VERSION 5.5 ;
NAMESCASESENSITIVE ON ;
BUSBITCHARS "[]" ;
DIVIDERCHAR "/" ;

PROPERTYDEFINITIONS
  LAYER routingPitch REAL ;
END PROPERTYDEFINITIONS

UNITS
  DATABASE MICRONS 1000 ;
END UNITS
MANUFACTURINGGRID 0.01 ;
LAYER POLY1
  TYPE MASTERSLICE ;
END POLY1

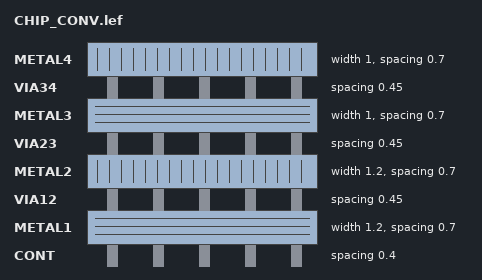
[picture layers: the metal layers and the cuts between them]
LAYER CONT
  TYPE CUT ;
  SPACING 0.4 ;
END CONT

LAYER METAL1
  TYPE ROUTING ;
  DIRECTION HORIZONTAL ;
  PITCH 0 ;
  WIDTH 1.2 ;
  SPACING 0.7 ;
  PROPERTY routingPitch 1.25 ;
END METAL1

LAYER VIA12
  TYPE CUT ;
  SPACING 0.45 ;
END VIA12

LAYER METAL2
  TYPE ROUTING ;
  DIRECTION VERTICAL ;
  PITCH 0 ;
  WIDTH 1.2 ;
  SPACING 0.7 ;
  PROPERTY routingPitch 1.4 ;
END METAL2

LAYER VIA23
  TYPE CUT ;
  SPACING 0.45 ;
END VIA23

LAYER METAL3
  TYPE ROUTING ;
  DIRECTION HORIZONTAL ;
  PITCH 0 ;
  WIDTH 1 ;
  SPACING 0.7 ;
  PROPERTY routingPitch 1.25 ;
END METAL3

LAYER VIA34
  TYPE CUT ;
  SPACING 0.45 ;
END VIA34

LAYER METAL4
  TYPE ROUTING ;
  DIRECTION VERTICAL ;
  PITCH 0 ;
  WIDTH 1 ;
  SPACING 0.7 ;
  PROPERTY routingPitch 1.4 ;
END METAL4

LAYER OVERLAP
  TYPE OVERLAP ;
END OVERLAP

VIARULE M4_M3 GENERATE
  LAYER METAL3 ;
    ENCLOSURE 0.2 0.2 ;
  LAYER METAL4 ;
    ENCLOSURE 0.15 0.15 ;
  LAYER VIA34 ;
    RECT -0.25 -0.25 0.25 0.25 ;
    SPACING 1 BY 1 ;
END M4_M3

VIARULE M3_M2 GENERATE
  LAYER METAL2 ;
    ENCLOSURE 0.2 0.2 ;
  LAYER METAL3 ;
    ENCLOSURE 0.15 0.15 ;
  LAYER VIA23 ;
    RECT -0.25 -0.25 0.25 0.25 ;
    SPACING 1 BY 1 ;
END M3_M2

VIARULE M2_M1 GENERATE
  LAYER METAL1 ;
    ENCLOSURE 0.2 0.2 ;
  LAYER METAL2 ;
    ENCLOSURE 0.15 0.15 ;
  LAYER VIA12 ;
    RECT -0.25 -0.25 0.25 0.25 ;
    SPACING 1 BY 1 ;
END M2_M1

VIARULE M1_POLY1 GENERATE
  LAYER POLY1 ;
    ENCLOSURE 0.2 0.2 ;
  LAYER METAL1 ;
    ENCLOSURE 0.15 0.15 ;
  LAYER CONT ;
    RECT -0.2 -0.2 0.2 0.2 ;
    SPACING 1 BY 1 ;
END M1_POLY1

VIA M1_POLY1
  LAYER CONT ;
    RECT -0.2 -0.2 0.2 0.2 ;
  LAYER POLY1 ;
    RECT -0.4 -0.4 0.4 0.4 ;
  LAYER METAL1 ;
    RECT -0.35 -0.35 0.35 0.35 ;
END M1_POLY1

VIA M2_M1
  LAYER VIA12 ;
    RECT -0.25 -0.25 0.25 0.25 ;
  LAYER METAL2 ;
    RECT -0.4 -0.4 0.4 0.4 ;
  LAYER METAL1 ;
    RECT -0.45 -0.45 0.45 0.45 ;
END M2_M1

VIA M3_M2
  LAYER VIA23 ;
    RECT -0.25 -0.25 0.25 0.25 ;
  LAYER METAL3 ;
    RECT -0.4 -0.4 0.4 0.4 ;
  LAYER METAL2 ;
    RECT -0.45 -0.45 0.45 0.45 ;
END M3_M2

VIA M4_M3
  LAYER VIA34 ;
    RECT -0.25 -0.25 0.25 0.25 ;
  LAYER METAL4 ;
    RECT -0.4 -0.4 0.4 0.4 ;
  LAYER METAL3 ;
    RECT -0.45 -0.45 0.45 0.45 ;
END M4_M3


MACRO Full_Macro_2p0_abstract
  PIN smclk_per_ext
    DIRECTION INOUT ;
    USE SIGNAL ;
    PORT
      LAYER METAL2 ;
        RECT 4738.52 82.5 4739.52 83.5 ;
    END
  END smclk_per_ext
  PIN unused_AN_MUX
    DIRECTION INOUT ;
    USE SIGNAL ;
    PORT
      LAYER METAL2 ;
        RECT 4784.2 45.0 4784.8 45.6 ;
    END
  END unused_AN_MUX
  PIN SystemDrainline<0>
    DIRECTION INOUT ;
    USE SIGNAL ;
    PORT
      LAYER METAL2 ;
        RECT 5600.2 45.0 5601.2 46.0 ;
    END
  END SystemDrainline<0>
  PIN SystemDrainline<1>
    DIRECTION INOUT ;
    USE SIGNAL ;
    PORT
      LAYER METAL2 ;
        RECT 5551.2 45.0 5552.2 46.0 ;
    END
  END SystemDrainline<1>
  PIN SystemDrainline<2>
    DIRECTION INOUT ;
    USE SIGNAL ;
    PORT
      LAYER METAL2 ;
        RECT 5500.8 45.0 5501.8 46.0 ;
    END
  END SystemDrainline<2>
  PIN V_IO
    DIRECTION INOUT ;
    USE SIGNAL ;
    PORT
      LAYER METAL2 ;
        RECT 5649.2 45.0 5650.2 46.0 ;
    END
  END V_IO
  PIN VTUN_AM
    DIRECTION INOUT ;
    USE SIGNAL ;
    PORT
      LAYER METAL2 ;
        RECT 5699.6 45.0 5700.6 46.0 ;
    END
  END VTUN_AM
  PIN VG_IO
    DIRECTION INOUT ;
    USE SIGNAL ;
    PORT
      LAYER METAL2 ;
        RECT 5748.6 45.0 5749.6 46.0 ;
    END
  END VG_IO
  PIN VGRUN
    DIRECTION INOUT ;
    USE SIGNAL ;
    PORT
      LAYER METAL2 ;
        RECT 5799.0 45.0 5800.0 46.0 ;
    END
  END VGRUN
  PIN VGPROG_IO
    DIRECTION INOUT ;
    USE SIGNAL ;
    PORT
      LAYER METAL2 ;
        RECT 5848.0 45.0 5849.0 46.0 ;
    END
  END VGPROG_IO
  PIN VGPROG
    DIRECTION INOUT ;
    USE SIGNAL ;
    PORT
      LAYER METAL2 ;
        RECT 5897.0 45.0 5898.0 46.0 ;
    END
  END VGPROG
  PIN VD_IO
    DIRECTION INOUT ;
    USE SIGNAL ;
    PORT
      LAYER METAL2 ;
        RECT 5947.4 45.0 5948.4 46.0 ;
    END
  END VD_IO
  PIN I_IO
    DIRECTION INOUT ;
    USE SIGNAL ;
    PORT
      LAYER METAL2 ;
        RECT 5996.4 45.0 5997.4 46.0 ;
    END
  END I_IO
  PIN Debug_IO
    DIRECTION INOUT ;
    USE SIGNAL ;
    PORT
      LAYER METAL2 ;
        RECT 6046.8 45.0 6047.8 46.0 ;
    END
  END Debug_IO
  PIN Cal_Vin
    DIRECTION INOUT ;
    USE SIGNAL ;
    PORT
      LAYER METAL2 ;
        RECT 6095.8 45.0 6096.8 46.0 ;
    END
  END Cal_Vin
  PIN Cal_IO
    DIRECTION INOUT ;
    USE SIGNAL ;
    PORT
      LAYER METAL2 ;
        RECT 6269.4 293.75 6270.4 294.35 ;
    END
  END Cal_IO
  PIN Bias_Trim
    DIRECTION INOUT ;
    USE SIGNAL ;
    PORT
      LAYER METAL2 ;
        RECT 6195.2 45.0 6196.2 46.0 ;
    END
  END Bias_Trim
  PIN AVDD
    DIRECTION INOUT ;
    USE SIGNAL ;
    PORT
      LAYER METAL2 ;
        RECT 6293.2 293.75 6294.2 294.75 ;
    END
  END AVDD
  PIN VINJ
    DIRECTION INOUT ;
    USE SIGNAL ;
    PORT
      LAYER METAL2 ;
        RECT 6253.39 293.75 6254.39 294.75 ;
    END
  END VINJ
  PIN DVDD
    DIRECTION INOUT ;
    USE SIGNAL ;
    PORT
      LAYER METAL2 ;
        RECT 4833.0 45.0 4834.0 46.0 ;
    END
  END DVDD
  PIN VTUN_fgmem
    DIRECTION INOUT ;
    USE SIGNAL ;
    PORT
      LAYER METAL2 ;
        RECT 4856.8 45.0 4857.8 46.0 ;
    END
  END VTUN_fgmem
  PIN Signal_DAC_out<0>
    DIRECTION INOUT ;
    USE SIGNAL ;
    PORT
      LAYER METAL2 ;
        RECT 5401.4 45.0 5402.4 46.0 ;
    END
  END Signal_DAC_out<0>
  PIN Signal_DAC_out<1>
    DIRECTION INOUT ;
    USE SIGNAL ;
    PORT
      LAYER METAL2 ;
        RECT 5352.4 45.0 5353.4 46.0 ;
    END
  END Signal_DAC_out<1>
  PIN Signal_DAC_out<2>
    DIRECTION INOUT ;
    USE SIGNAL ;
    PORT
      LAYER METAL2 ;
        RECT 5303.4 45.0 5304.4 46.0 ;
    END
  END Signal_DAC_out<2>
  PIN RUN_HV
    DIRECTION INOUT ;
    USE SIGNAL ;
    PORT
      LAYER METAL2 ;
        RECT 1.6 195.0 2.6 196.0 ;
    END
  END RUN_HV
  PIN PROG_HV
    DIRECTION INOUT ;
    USE SIGNAL ;
    PORT
      LAYER METAL2 ;
        RECT 50.6 195.0 51.6 196.0 ;
    END
  END PROG_HV
  PIN pulse_fr_drain
    DIRECTION INOUT ;
    USE SIGNAL ;
    PORT
      LAYER METAL2 ;
        RECT 5451.8 45.0 5452.8 46.0 ;
    END
  END pulse_fr_drain
  PIN mmio_reg_10_bout<0>
    DIRECTION INOUT ;
    USE SIGNAL ;
    PORT
      LAYER METAL2 ;
        RECT 3518.4 82.5 3519.4 83.5 ;
    END
  END mmio_reg_10_bout<0>
  PIN mmio_reg_10_bout<1>
    DIRECTION INOUT ;
    USE SIGNAL ;
    PORT
      LAYER METAL2 ;
        RECT 3469.4 82.5 3470.4 83.5 ;
    END
  END mmio_reg_10_bout<1>
  PIN mmio_reg_10_bout<2>
    DIRECTION INOUT ;
    USE SIGNAL ;
    PORT
      LAYER METAL2 ;
        RECT 3420.4 82.5 3421.4 83.5 ;
    END
  END mmio_reg_10_bout<2>
  PIN mmio_reg_10_bout<3>
    DIRECTION INOUT ;
    USE SIGNAL ;
    PORT
      LAYER METAL2 ;
        RECT 3370.0 82.5 3371.0 83.5 ;
    END
  END mmio_reg_10_bout<3>
  PIN mmio_reg_10_bout<4>
    DIRECTION INOUT ;
    USE SIGNAL ;
    PORT
      LAYER METAL2 ;
        RECT 3321.0 82.5 3322.0 83.5 ;
    END
  END mmio_reg_10_bout<4>
  PIN mmio_reg_10_bout<5>
    DIRECTION INOUT ;
    USE SIGNAL ;
    PORT
      LAYER METAL2 ;
        RECT 3270.6 82.5 3271.6 83.5 ;
    END
  END mmio_reg_10_bout<5>
  PIN mmio_reg_10_bout<6>
    DIRECTION INOUT ;
    USE SIGNAL ;
    PORT
      LAYER METAL2 ;
        RECT 3221.6 82.5 3222.6 83.5 ;
    END
  END mmio_reg_10_bout<6>
  PIN mmio_reg_10_bout<7>
    DIRECTION INOUT ;
    USE SIGNAL ;
    PORT
      LAYER METAL2 ;
        RECT 3172.6 82.5 3173.6 83.5 ;
    END
  END mmio_reg_10_bout<7>
  PIN mmio_reg_10_bout<8>
    DIRECTION INOUT ;
    USE SIGNAL ;
    PORT
      LAYER METAL2 ;
        RECT 3122.2 82.5 3123.2 83.5 ;
    END
  END mmio_reg_10_bout<8>
  PIN mmio_reg_10_bout<9>
    DIRECTION INOUT ;
    USE SIGNAL ;
    PORT
      LAYER METAL2 ;
        RECT 3073.2 82.5 3074.2 83.5 ;
    END
  END mmio_reg_10_bout<9>
  PIN mmio_reg_10_bout<10>
    DIRECTION INOUT ;
    USE SIGNAL ;
    PORT
      LAYER METAL2 ;
        RECT 3024.2 82.5 3025.2 83.5 ;
    END
  END mmio_reg_10_bout<10>
  PIN mmio_reg_10_bout<11>
    DIRECTION INOUT ;
    USE SIGNAL ;
    PORT
      LAYER METAL2 ;
        RECT 2973.8 82.5 2974.8 83.5 ;
    END
  END mmio_reg_10_bout<11>
  PIN mmio_reg_10_bout<12>
    DIRECTION INOUT ;
    USE SIGNAL ;
    PORT
      LAYER METAL2 ;
        RECT 2924.8 82.5 2925.8 83.5 ;
    END
  END mmio_reg_10_bout<12>
  PIN mmio_reg_10_bout<13>
    DIRECTION INOUT ;
    USE SIGNAL ;
    PORT
      LAYER METAL2 ;
        RECT 2874.4 82.5 2875.4 83.5 ;
    END
  END mmio_reg_10_bout<13>
  PIN mmio_reg_10_bout<14>
    DIRECTION INOUT ;
    USE SIGNAL ;
    PORT
      LAYER METAL2 ;
        RECT 2825.4 82.5 2826.4 83.5 ;
    END
  END mmio_reg_10_bout<14>
  PIN mmio_reg_10_bout<15>
    DIRECTION INOUT ;
    USE SIGNAL ;
    PORT
      LAYER METAL2 ;
        RECT 2776.4 82.5 2777.4 83.5 ;
    END
  END mmio_reg_10_bout<15>
  PIN mmio_reg_9_bout<0>
    DIRECTION INOUT ;
    USE SIGNAL ;
    PORT
      LAYER METAL2 ;
        RECT 4312.2 82.5 4313.2 83.5 ;
    END
  END mmio_reg_9_bout<0>
  PIN mmio_reg_9_bout<1>
    DIRECTION INOUT ;
    USE SIGNAL ;
    PORT
      LAYER METAL2 ;
        RECT 4261.8 82.5 4262.8 83.5 ;
    END
  END mmio_reg_9_bout<1>
  PIN mmio_reg_9_bout<2>
    DIRECTION INOUT ;
    USE SIGNAL ;
    PORT
      LAYER METAL2 ;
        RECT 4212.8 82.5 4213.8 83.5 ;
    END
  END mmio_reg_9_bout<2>
  PIN mmio_reg_9_bout<3>
    DIRECTION INOUT ;
    USE SIGNAL ;
    PORT
      LAYER METAL2 ;
        RECT 4163.8 82.5 4164.8 83.5 ;
    END
  END mmio_reg_9_bout<3>
  PIN mmio_reg_9_bout<4>
    DIRECTION INOUT ;
    USE SIGNAL ;
    PORT
      LAYER METAL2 ;
        RECT 4113.4 82.5 4114.4 83.5 ;
    END
  END mmio_reg_9_bout<4>
  PIN mmio_reg_9_bout<5>
    DIRECTION INOUT ;
    USE SIGNAL ;
    PORT
      LAYER METAL2 ;
        RECT 4064.4 82.5 4065.4 83.5 ;
    END
  END mmio_reg_9_bout<5>
  PIN mmio_reg_9_bout<6>
    DIRECTION INOUT ;
    USE SIGNAL ;
    PORT
      LAYER METAL2 ;
        RECT 4014.0 82.5 4015.0 83.5 ;
    END
  END mmio_reg_9_bout<6>
  PIN mmio_reg_9_bout<7>
    DIRECTION INOUT ;
    USE SIGNAL ;
    PORT
      LAYER METAL2 ;
        RECT 3965.0 82.5 3966.0 83.5 ;
    END
  END mmio_reg_9_bout<7>
  PIN mmio_reg_9_bout<8>
    DIRECTION INOUT ;
    USE SIGNAL ;
    PORT
      LAYER METAL2 ;
        RECT 3916.0 82.5 3917.0 83.5 ;
    END
  END mmio_reg_9_bout<8>
  PIN mmio_reg_9_bout<9>
    DIRECTION INOUT ;
    USE SIGNAL ;
    PORT
      LAYER METAL2 ;
        RECT 3865.6 82.5 3866.6 83.5 ;
    END
  END mmio_reg_9_bout<9>
  PIN mmio_reg_9_bout<10>
    DIRECTION INOUT ;
    USE SIGNAL ;
    PORT
      LAYER METAL2 ;
        RECT 3816.6 82.5 3817.6 83.5 ;
    END
  END mmio_reg_9_bout<10>
  PIN mmio_reg_9_bout<11>
    DIRECTION INOUT ;
    USE SIGNAL ;
    PORT
      LAYER METAL2 ;
        RECT 3766.2 82.5 3767.2 83.5 ;
    END
  END mmio_reg_9_bout<11>
  PIN mmio_reg_9_bout<12>
    DIRECTION INOUT ;
    USE SIGNAL ;
    PORT
      LAYER METAL2 ;
        RECT 3717.2 82.5 3718.2 83.5 ;
    END
  END mmio_reg_9_bout<12>
  PIN mmio_reg_9_bout<13>
    DIRECTION INOUT ;
    USE SIGNAL ;
    PORT
      LAYER METAL2 ;
        RECT 3668.2 82.5 3669.2 83.5 ;
    END
  END mmio_reg_9_bout<13>
  PIN mmio_reg_9_bout<14>
    DIRECTION INOUT ;
    USE SIGNAL ;
    PORT
      LAYER METAL2 ;
        RECT 3617.8 82.5 3618.8 83.5 ;
    END
  END mmio_reg_9_bout<14>
  PIN mmio_reg_9_bout<15>
    DIRECTION INOUT ;
    USE SIGNAL ;
    PORT
      LAYER METAL2 ;
        RECT 3568.8 82.5 3569.8 83.5 ;
    END
  END mmio_reg_9_bout<15>
  PIN mmio_reg_5_vinj<0>
    DIRECTION INOUT ;
    USE SIGNAL ;
    PORT
      LAYER METAL2 ;
        RECT 4807.8 45.0 4808.8 46.0 ;
    END
  END mmio_reg_5_vinj<0>
  PIN mmio_reg_5_vinj<1>
    DIRECTION INOUT ;
    USE SIGNAL ;
    PORT
      LAYER METAL2 ;
        RECT 4757.4 82.5 4758.4 83.5 ;
    END
  END mmio_reg_5_vinj<1>
  PIN mmio_reg_5_vinj<2>
    DIRECTION INOUT ;
    USE SIGNAL ;
    PORT
      LAYER METAL2 ;
        RECT 4708.4 82.5 4709.4 83.5 ;
    END
  END mmio_reg_5_vinj<2>
  PIN mmio_reg_5_vinj<3>
    DIRECTION INOUT ;
    USE SIGNAL ;
    PORT
      LAYER METAL2 ;
        RECT 4659.4 82.5 4660.4 83.5 ;
    END
  END mmio_reg_5_vinj<3>
  PIN mmio_reg_5_vinj<4>
    DIRECTION INOUT ;
    USE SIGNAL ;
    PORT
      LAYER METAL2 ;
        RECT 4609.0 82.5 4610.0 83.5 ;
    END
  END mmio_reg_5_vinj<4>
  PIN mmio_reg_5_vinj<5>
    DIRECTION INOUT ;
    USE SIGNAL ;
    PORT
      LAYER METAL2 ;
        RECT 4560.0 82.5 4561.0 83.5 ;
    END
  END mmio_reg_5_vinj<5>
  PIN mmio_reg_5_vinj<6>
    DIRECTION INOUT ;
    USE SIGNAL ;
    PORT
      LAYER METAL2 ;
        RECT 4509.6 82.5 4510.6 83.5 ;
    END
  END mmio_reg_5_vinj<6>
  PIN mmio_reg_5_vinj<7>
    DIRECTION INOUT ;
    USE SIGNAL ;
    PORT
      LAYER METAL2 ;
        RECT 4460.6 82.5 4461.6 83.5 ;
    END
  END mmio_reg_5_vinj<7>
  PIN mmio_reg_5_vinj<8>
    DIRECTION INOUT ;
    USE SIGNAL ;
    PORT
      LAYER METAL2 ;
        RECT 4411.6 82.5 4412.6 83.5 ;
    END
  END mmio_reg_5_vinj<8>
  PIN mmio_reg_5_vinj<9>
    DIRECTION INOUT ;
    USE SIGNAL ;
    PORT
      LAYER METAL2 ;
        RECT 4361.2 82.5 4362.2 83.5 ;
    END
  END mmio_reg_5_vinj<9>
  PIN prog_lv
    DIRECTION INOUT ;
    USE SIGNAL ;
    PORT
      LAYER METAL2 ;
        RECT 99.6 195.0 100.6 196.0 ;
    END
  END prog_lv
  PIN puc_rst_bout
    DIRECTION INOUT ;
    USE SIGNAL ;
    PORT
      LAYER METAL2 ;
        RECT 2726.0 82.5 2727.0 83.5 ;
    END
  END puc_rst_bout
  PIN per_we_bout<0>
    DIRECTION INOUT ;
    USE SIGNAL ;
    PORT
      LAYER METAL2 ;
        RECT 2626.6 82.5 2627.6 83.5 ;
    END
  END per_we_bout<0>
  PIN per_we_bout<1>
    DIRECTION INOUT ;
    USE SIGNAL ;
    PORT
      LAYER METAL2 ;
        RECT 2577.6 82.5 2578.6 83.5 ;
    END
  END per_we_bout<1>
  PIN per_en_bout
    DIRECTION INOUT ;
    USE SIGNAL ;
    PORT
      LAYER METAL2 ;
        RECT 2677.0 82.5 2678.0 83.5 ;
    END
  END per_en_bout
  PIN per_din_bout<0>
    DIRECTION INOUT ;
    USE SIGNAL ;
    PORT
      LAYER METAL2 ;
        RECT 2528.6 82.5 2529.6 83.5 ;
    END
  END per_din_bout<0>
  PIN per_din_bout<1>
    DIRECTION INOUT ;
    USE SIGNAL ;
    PORT
      LAYER METAL2 ;
        RECT 2478.2 82.5 2479.2 83.5 ;
    END
  END per_din_bout<1>
  PIN per_din_bout<2>
    DIRECTION INOUT ;
    USE SIGNAL ;
    PORT
      LAYER METAL2 ;
        RECT 2429.2 82.5 2430.2 83.5 ;
    END
  END per_din_bout<2>
  PIN per_din_bout<3>
    DIRECTION INOUT ;
    USE SIGNAL ;
    PORT
      LAYER METAL2 ;
        RECT 2378.8 82.5 2379.8 83.5 ;
    END
  END per_din_bout<3>
  PIN per_din_bout<4>
    DIRECTION INOUT ;
    USE SIGNAL ;
    PORT
      LAYER METAL2 ;
        RECT 2329.8 82.5 2330.8 83.5 ;
    END
  END per_din_bout<4>
  PIN per_din_bout<5>
    DIRECTION INOUT ;
    USE SIGNAL ;
    PORT
      LAYER METAL2 ;
        RECT 2280.8 82.5 2281.8 83.5 ;
    END
  END per_din_bout<5>
  PIN per_din_bout<6>
    DIRECTION INOUT ;
    USE SIGNAL ;
    PORT
      LAYER METAL2 ;
        RECT 2230.4 82.5 2231.4 83.5 ;
    END
  END per_din_bout<6>
  PIN per_din_bout<7>
    DIRECTION INOUT ;
    USE SIGNAL ;
    PORT
      LAYER METAL2 ;
        RECT 2181.4 82.5 2182.4 83.5 ;
    END
  END per_din_bout<7>
  PIN per_din_bout<8>
    DIRECTION INOUT ;
    USE SIGNAL ;
    PORT
      LAYER METAL2 ;
        RECT 2131.0 82.5 2132.0 83.5 ;
    END
  END per_din_bout<8>
  PIN per_din_bout<9>
    DIRECTION INOUT ;
    USE SIGNAL ;
    PORT
      LAYER METAL2 ;
        RECT 2082.0 82.5 2083.0 83.5 ;
    END
  END per_din_bout<9>
  PIN per_din_bout<10>
    DIRECTION INOUT ;
    USE SIGNAL ;
    PORT
      LAYER METAL2 ;
        RECT 2033.0 82.5 2034.0 83.5 ;
    END
  END per_din_bout<10>
  PIN per_din_bout<11>
    DIRECTION INOUT ;
    USE SIGNAL ;
    PORT
      LAYER METAL2 ;
        RECT 1982.6 82.5 1983.6 83.5 ;
    END
  END per_din_bout<11>
  PIN per_din_bout<12>
    DIRECTION INOUT ;
    USE SIGNAL ;
    PORT
      LAYER METAL2 ;
        RECT 1933.6 82.5 1934.6 83.5 ;
    END
  END per_din_bout<12>
  PIN per_din_bout<13>
    DIRECTION INOUT ;
    USE SIGNAL ;
    PORT
      LAYER METAL2 ;
        RECT 1883.2 82.5 1884.2 83.5 ;
    END
  END per_din_bout<13>
  PIN per_din_bout<14>
    DIRECTION INOUT ;
    USE SIGNAL ;
    PORT
      LAYER METAL2 ;
        RECT 1834.2 82.5 1835.2 83.5 ;
    END
  END per_din_bout<14>
  PIN per_din_bout<15>
    DIRECTION INOUT ;
    USE SIGNAL ;
    PORT
      LAYER METAL2 ;
        RECT 1785.2 82.5 1786.2 83.5 ;
    END
  END per_din_bout<15>
  PIN per_addr_bout<0>
    DIRECTION INOUT ;
    USE SIGNAL ;
    PORT
      LAYER METAL2 ;
        RECT 1734.8 82.5 1735.8 83.5 ;
    END
  END per_addr_bout<0>
  PIN per_addr_bout<1>
    DIRECTION INOUT ;
    USE SIGNAL ;
    PORT
      LAYER METAL2 ;
        RECT 1685.8 82.5 1686.8 83.5 ;
    END
  END per_addr_bout<1>
  PIN per_addr_bout<2>
    DIRECTION INOUT ;
    USE SIGNAL ;
    PORT
      LAYER METAL2 ;
        RECT 1635.4 82.5 1636.4 83.5 ;
    END
  END per_addr_bout<2>
  PIN per_addr_bout<3>
    DIRECTION INOUT ;
    USE SIGNAL ;
    PORT
      LAYER METAL2 ;
        RECT 1586.4 82.5 1587.4 83.5 ;
    END
  END per_addr_bout<3>
  PIN per_addr_bout<4>
    DIRECTION INOUT ;
    USE SIGNAL ;
    PORT
      LAYER METAL2 ;
        RECT 1537.4 82.5 1538.4 83.5 ;
    END
  END per_addr_bout<4>
  PIN per_addr_bout<5>
    DIRECTION INOUT ;
    USE SIGNAL ;
    PORT
      LAYER METAL2 ;
        RECT 1487.0 82.5 1488.0 83.5 ;
    END
  END per_addr_bout<5>
  PIN per_addr_bout<6>
    DIRECTION INOUT ;
    USE SIGNAL ;
    PORT
      LAYER METAL2 ;
        RECT 1438.0 82.5 1439.0 83.5 ;
    END
  END per_addr_bout<6>
  PIN per_addr_bout<7>
    DIRECTION INOUT ;
    USE SIGNAL ;
    PORT
      LAYER METAL2 ;
        RECT 1389.0 195.0 1390.0 196.0 ;
    END
  END per_addr_bout<7>
  PIN per_addr_bout<8>
    DIRECTION INOUT ;
    USE SIGNAL ;
    PORT
      LAYER METAL2 ;
        RECT 1338.6 195.0 1339.6 196.0 ;
    END
  END per_addr_bout<8>
  PIN per_addr_bout<9>
    DIRECTION INOUT ;
    USE SIGNAL ;
    PORT
      LAYER METAL2 ;
        RECT 1289.6 195.0 1290.6 196.0 ;
    END
  END per_addr_bout<9>
  PIN per_addr_bout<10>
    DIRECTION INOUT ;
    USE SIGNAL ;
    PORT
      LAYER METAL2 ;
        RECT 1239.2 195.0 1240.2 196.0 ;
    END
  END per_addr_bout<10>
  PIN per_addr_bout<11>
    DIRECTION INOUT ;
    USE SIGNAL ;
    PORT
      LAYER METAL2 ;
        RECT 1190.2 195.0 1191.2 196.0 ;
    END
  END per_addr_bout<11>
  PIN per_addr_bout<12>
    DIRECTION INOUT ;
    USE SIGNAL ;
    PORT
      LAYER METAL2 ;
        RECT 1141.2 195.0 1142.2 196.0 ;
    END
  END per_addr_bout<12>
  PIN per_addr_bout<13>
    DIRECTION INOUT ;
    USE SIGNAL ;
    PORT
      LAYER METAL2 ;
        RECT 1090.8 195.0 1091.8 196.0 ;
    END
  END per_addr_bout<13>
  PIN dbg_uart_txd
    DIRECTION INOUT ;
    USE SIGNAL ;
    PORT
      LAYER METAL2 ;
        RECT 4194.6 1414.0 4195.6 1415.0 ;
    END
  END dbg_uart_txd
  PIN Signal_RampADC_inp<0>
    DIRECTION INOUT ;
    USE SIGNAL ;
    PORT
      LAYER METAL2 ;
        RECT 5153.6 45.0 5154.6 46.0 ;
    END
  END Signal_RampADC_inp<0>
  PIN Signal_RampADC_inp<1>
    DIRECTION INOUT ;
    USE SIGNAL ;
    PORT
      LAYER METAL2 ;
        RECT 5104.6 45.0 5105.6 46.0 ;
    END
  END Signal_RampADC_inp<1>
  PIN Signal_RampADC_inp<2>
    DIRECTION INOUT ;
    USE SIGNAL ;
    PORT
      LAYER METAL2 ;
        RECT 5055.6 45.0 5056.6 46.0 ;
    END
  END Signal_RampADC_inp<2>
  PIN Signal_RampADC_inp<3>
    DIRECTION INOUT ;
    USE SIGNAL ;
    PORT
      LAYER METAL2 ;
        RECT 5005.2 45.0 5006.2 46.0 ;
    END
  END Signal_RampADC_inp<3>
  PIN Signal_RampADC_inp<4>
    DIRECTION INOUT ;
    USE SIGNAL ;
    PORT
      LAYER METAL2 ;
        RECT 4956.2 45.0 4957.2 46.0 ;
    END
  END Signal_RampADC_inp<4>
  PIN Signal_RampADC_inp<5>
    DIRECTION INOUT ;
    USE SIGNAL ;
    PORT
      LAYER METAL2 ;
        RECT 4905.8 45.0 4906.8 46.0 ;
    END
  END Signal_RampADC_inp<5>
  PIN fast_clk
    DIRECTION INOUT ;
    USE SIGNAL ;
    PORT
      LAYER METAL2 ;
        RECT 418.8 1414.0 419.8 1415.0 ;
    END
  END fast_clk
  PIN scan_in2
    DIRECTION INOUT ;
    USE SIGNAL ;
    PORT
      LAYER METAL2 ;
        RECT 5873.2 1414.0 5874.2 1415.0 ;
    END
  END scan_in2
  PIN scan_in1
    DIRECTION INOUT ;
    USE SIGNAL ;
    PORT
      LAYER METAL2 ;
        RECT 5453.2 1414.0 5454.2 1415.0 ;
    END
  END scan_in1
  PIN wkup
    DIRECTION INOUT ;
    USE SIGNAL ;
    PORT
      LAYER METAL2 ;
        RECT 5033.2 1414.0 5034.2 1415.0 ;
    END
  END wkup
  PIN scan_mode
    DIRECTION INOUT ;
    USE SIGNAL ;
    PORT
      LAYER METAL2 ;
        RECT 4614.6 1414.0 4615.6 1415.0 ;
    END
  END scan_mode
  PIN scan_enable
    DIRECTION INOUT ;
    USE SIGNAL ;
    PORT
      LAYER METAL2 ;
        RECT 3776.0 1414.0 3777.0 1415.0 ;
    END
  END scan_enable
  PIN reset_n
    DIRECTION INOUT ;
    USE SIGNAL ;
    PORT
      LAYER METAL2 ;
        RECT 3356.0 1414.0 3357.0 1415.0 ;
    END
  END reset_n
  PIN per_dout_ext<0>
    DIRECTION INOUT ;
    USE SIGNAL ;
    PORT
      LAYER METAL2 ;
        RECT 1041.8 195.0 1042.8 196.0 ;
    END
  END per_dout_ext<0>
  PIN per_dout_ext<1>
    DIRECTION INOUT ;
    USE SIGNAL ;
    PORT
      LAYER METAL2 ;
        RECT 991.4 195.0 992.4 196.0 ;
    END
  END per_dout_ext<1>
  PIN per_dout_ext<2>
    DIRECTION INOUT ;
    USE SIGNAL ;
    PORT
      LAYER METAL2 ;
        RECT 942.4 195.0 943.4 196.0 ;
    END
  END per_dout_ext<2>
  PIN per_dout_ext<3>
    DIRECTION INOUT ;
    USE SIGNAL ;
    PORT
      LAYER METAL2 ;
        RECT 893.4 195.0 894.4 196.0 ;
    END
  END per_dout_ext<3>
  PIN per_dout_ext<4>
    DIRECTION INOUT ;
    USE SIGNAL ;
    PORT
      LAYER METAL2 ;
        RECT 843.0 195.0 844.0 196.0 ;
    END
  END per_dout_ext<4>
  PIN per_dout_ext<5>
    DIRECTION INOUT ;
    USE SIGNAL ;
    PORT
      LAYER METAL2 ;
        RECT 794.0 195.0 795.0 196.0 ;
    END
  END per_dout_ext<5>
  PIN per_dout_ext<6>
    DIRECTION INOUT ;
    USE SIGNAL ;
    PORT
      LAYER METAL2 ;
        RECT 743.6 195.0 744.6 196.0 ;
    END
  END per_dout_ext<6>
  PIN per_dout_ext<7>
    DIRECTION INOUT ;
    USE SIGNAL ;
    PORT
      LAYER METAL2 ;
        RECT 694.6 195.0 695.6 196.0 ;
    END
  END per_dout_ext<7>
  PIN per_dout_ext<8>
    DIRECTION INOUT ;
    USE SIGNAL ;
    PORT
      LAYER METAL2 ;
        RECT 645.6 195.0 646.6 196.0 ;
    END
  END per_dout_ext<8>
  PIN per_dout_ext<9>
    DIRECTION INOUT ;
    USE SIGNAL ;
    PORT
      LAYER METAL2 ;
        RECT 595.2 195.0 596.2 196.0 ;
    END
  END per_dout_ext<9>
  PIN per_dout_ext<10>
    DIRECTION INOUT ;
    USE SIGNAL ;
    PORT
      LAYER METAL2 ;
        RECT 546.2 195.0 547.2 196.0 ;
    END
  END per_dout_ext<10>
  PIN per_dout_ext<11>
    DIRECTION INOUT ;
    USE SIGNAL ;
    PORT
      LAYER METAL2 ;
        RECT 495.8 195.0 496.8 196.0 ;
    END
  END per_dout_ext<11>
  PIN per_dout_ext<12>
    DIRECTION INOUT ;
    USE SIGNAL ;
    PORT
      LAYER METAL2 ;
        RECT 446.8 195.0 447.8 196.0 ;
    END
  END per_dout_ext<12>
  PIN per_dout_ext<13>
    DIRECTION INOUT ;
    USE SIGNAL ;
    PORT
      LAYER METAL2 ;
        RECT 397.8 195.0 398.8 196.0 ;
    END
  END per_dout_ext<13>
  PIN per_dout_ext<14>
    DIRECTION INOUT ;
    USE SIGNAL ;
    PORT
      LAYER METAL2 ;
        RECT 347.4 195.0 348.4 196.0 ;
    END
  END per_dout_ext<14>
  PIN per_dout_ext<15>
    DIRECTION INOUT ;
    USE SIGNAL ;
    PORT
      LAYER METAL2 ;
        RECT 298.4 195.0 299.4 196.0 ;
    END
  END per_dout_ext<15>
  PIN nmi
    DIRECTION INOUT ;
    USE SIGNAL ;
    PORT
      LAYER METAL2 ;
        RECT 2936.0 1414.0 2937.0 1415.0 ;
    END
  END nmi
  PIN lfxt_clk
    DIRECTION INOUT ;
    USE SIGNAL ;
    PORT
      LAYER METAL2 ;
        RECT 0.2 1414.0 1.2 1415.0 ;
    END
  END lfxt_clk
  PIN irq<0>
    DIRECTION INOUT ;
    USE SIGNAL ;
    PORT
      LAYER METAL2 ;
        RECT 838.8 1414.0 839.8 1415.0 ;
    END
  END irq<0>
  PIN irq<1>
    DIRECTION INOUT ;
    USE SIGNAL ;
    PORT
      LAYER METAL2 ;
        RECT 1258.8 1414.0 1259.8 1415.0 ;
    END
  END irq<1>
  PIN irq<2>
    DIRECTION INOUT ;
    USE SIGNAL ;
    PORT
      LAYER METAL2 ;
        RECT 248.0 195.0 249.0 196.0 ;
    END
  END irq<2>
  PIN irq<3>
    DIRECTION INOUT ;
    USE SIGNAL ;
    PORT
      LAYER METAL2 ;
        RECT 199.0 195.0 200.0 196.0 ;
    END
  END irq<3>
  PIN irq<4>
    DIRECTION INOUT ;
    USE SIGNAL ;
    PORT
      LAYER METAL2 ;
        RECT 150.0 195.0 151.0 196.0 ;
    END
  END irq<4>
  PIN dco_clk
    DIRECTION INOUT ;
    USE SIGNAL ;
    PORT
      LAYER METAL2 ;
        RECT 6293.2 1414.0 6294.2 1415.0 ;
    END
  END dco_clk
  PIN dbg_uart_rxd
    DIRECTION INOUT ;
    USE SIGNAL ;
    PORT
      LAYER METAL2 ;
        RECT 2517.4 1414.0 2518.4 1415.0 ;
    END
  END dbg_uart_rxd
  PIN dbg_en
    DIRECTION INOUT ;
    USE SIGNAL ;
    PORT
      LAYER METAL2 ;
        RECT 2097.4 1414.0 2098.4 1415.0 ;
    END
  END dbg_en
  PIN cpu_en
    DIRECTION INOUT ;
    USE SIGNAL ;
    PORT
      LAYER METAL2 ;
        RECT 1677.4 1414.0 1678.4 1415.0 ;
    END
  END cpu_en
  PIN sram_CS_VBIAS
    DIRECTION INOUT ;
    USE SIGNAL ;
    PORT
      LAYER METAL3 ;
        RECT 4779.6 48.25 4780.6 49.25 ;
    END
  END sram_CS_VBIAS
  PIN fgmem_CS_VBIAS
    DIRECTION INOUT ;
    USE SIGNAL ;
    PORT
      LAYER METAL3 ;
        RECT 0.0 1005.75 1.0 1006.75 ;
    END
  END fgmem_CS_VBIAS
  PIN Macro_dbg_Scan_Vout
    DIRECTION INOUT ;
    USE SIGNAL ;
    PORT
      LAYER METAL3 ;
        RECT 0.0 742.0 1.0 743.0 ;
    END
  END Macro_dbg_Scan_Vout
  PIN mmio_reg_7_bout<0>
    DIRECTION INOUT ;
    USE SIGNAL ;
    PORT
      LAYER METAL3 ;
        RECT 0.0 383.25 1.0 384.25 ;
    END
  END mmio_reg_7_bout<0>
  PIN mmio_reg_7_bout<1>
    DIRECTION INOUT ;
    USE SIGNAL ;
    PORT
      LAYER METAL3 ;
        RECT 0.0 407.0 1.0 408.0 ;
    END
  END mmio_reg_7_bout<1>
  PIN mmio_reg_7_bout<2>
    DIRECTION INOUT ;
    USE SIGNAL ;
    PORT
      LAYER METAL3 ;
        RECT 0.0 430.75 1.0 431.75 ;
    END
  END mmio_reg_7_bout<2>
  PIN mmio_reg_7_bout<3>
    DIRECTION INOUT ;
    USE SIGNAL ;
    PORT
      LAYER METAL3 ;
        RECT 0.0 454.5 1.0 455.5 ;
    END
  END mmio_reg_7_bout<3>
  PIN mmio_reg_7_bout<4>
    DIRECTION INOUT ;
    USE SIGNAL ;
    PORT
      LAYER METAL3 ;
        RECT 0.0 479.5 1.0 480.5 ;
    END
  END mmio_reg_7_bout<4>
  PIN mmio_reg_7_bout<5>
    DIRECTION INOUT ;
    USE SIGNAL ;
    PORT
      LAYER METAL3 ;
        RECT 0.0 503.25 1.0 504.25 ;
    END
  END mmio_reg_7_bout<5>
  PIN mmio_reg_7_bout<6>
    DIRECTION INOUT ;
    USE SIGNAL ;
    PORT
      LAYER METAL3 ;
        RECT 0.0 527.0 1.0 528.0 ;
    END
  END mmio_reg_7_bout<6>
  PIN mmio_reg_7_bout<7>
    DIRECTION INOUT ;
    USE SIGNAL ;
    PORT
      LAYER METAL3 ;
        RECT 0.0 550.75 1.0 551.75 ;
    END
  END mmio_reg_7_bout<7>
  PIN mmio_reg_7_bout<8>
    DIRECTION INOUT ;
    USE SIGNAL ;
    PORT
      LAYER METAL3 ;
        RECT 0.0 574.5 1.0 575.5 ;
    END
  END mmio_reg_7_bout<8>
  PIN mmio_reg_7_bout<9>
    DIRECTION INOUT ;
    USE SIGNAL ;
    PORT
      LAYER METAL3 ;
        RECT 0.0 598.25 1.0 599.25 ;
    END
  END mmio_reg_7_bout<9>
  PIN mmio_reg_7_bout<10>
    DIRECTION INOUT ;
    USE SIGNAL ;
    PORT
      LAYER METAL3 ;
        RECT 0.0 622.0 1.0 623.0 ;
    END
  END mmio_reg_7_bout<10>
  PIN mmio_reg_7_bout<11>
    DIRECTION INOUT ;
    USE SIGNAL ;
    PORT
      LAYER METAL3 ;
        RECT 0.0 647.0 1.0 648.0 ;
    END
  END mmio_reg_7_bout<11>
  PIN mmio_reg_7_bout<12>
    DIRECTION INOUT ;
    USE SIGNAL ;
    PORT
      LAYER METAL3 ;
        RECT 0.0 670.75 1.0 671.75 ;
    END
  END mmio_reg_7_bout<12>
  PIN mmio_reg_7_bout<13>
    DIRECTION INOUT ;
    USE SIGNAL ;
    PORT
      LAYER METAL3 ;
        RECT 0.0 694.5 1.0 695.5 ;
    END
  END mmio_reg_7_bout<13>
  PIN mmio_reg_7_bout<14>
    DIRECTION INOUT ;
    USE SIGNAL ;
    PORT
      LAYER METAL3 ;
        RECT 0.0 718.25 1.0 719.25 ;
    END
  END mmio_reg_7_bout<14>
  PIN mmio_reg_3_vinj_b0
    DIRECTION INOUT ;
    USE SIGNAL ;
    PORT
      LAYER METAL3 ;
        RECT 0.0 1413.25 1.0 1414.25 ;
    END
  END mmio_reg_3_vinj_b0
  PIN peri_spi_mstr_cs_n_3
    DIRECTION INOUT ;
    USE SIGNAL ;
    PORT
      LAYER METAL3 ;
        RECT 0.0 359.5 1.0 360.5 ;
    END
  END peri_spi_mstr_cs_n_3
  PIN peri_spi_mstr_cs_n_2
    DIRECTION INOUT ;
    USE SIGNAL ;
    PORT
      LAYER METAL3 ;
        RECT 0.0 335.75 1.0 336.75 ;
    END
  END peri_spi_mstr_cs_n_2
  PIN peri_spi_mstr_cs_n_1
    DIRECTION INOUT ;
    USE SIGNAL ;
    PORT
      LAYER METAL3 ;
        RECT 0.0 310.75 1.0 311.75 ;
    END
  END peri_spi_mstr_cs_n_1
  PIN peri_spi_mstr_cs_n_0
    DIRECTION INOUT ;
    USE SIGNAL ;
    PORT
      LAYER METAL3 ;
        RECT 0.0 287.0 1.0 288.0 ;
    END
  END peri_spi_mstr_cs_n_0
  PIN peri_spi_mstr_mosi
    DIRECTION INOUT ;
    USE SIGNAL ;
    PORT
      LAYER METAL3 ;
        RECT 0.0 263.25 1.0 264.25 ;
    END
  END peri_spi_mstr_mosi
  PIN peri_spi_mstr_spiclk
    DIRECTION INOUT ;
    USE SIGNAL ;
    PORT
      LAYER METAL3 ;
        RECT 0.0 215.75 1.0 216.75 ;
    END
  END peri_spi_mstr_spiclk
  PIN peri_spi_slave_miso
    DIRECTION INOUT ;
    USE SIGNAL ;
    PORT
      LAYER METAL3 ;
        RECT 1411.2 143.25 1412.2 144.25 ;
    END
  END peri_spi_slave_miso
  PIN scan_out2_bout
    DIRECTION INOUT ;
    USE SIGNAL ;
    PORT
      LAYER METAL3 ;
        RECT 0.0 958.25 1.0 959.25 ;
    END
  END scan_out2_bout
  PIN scan_out1_bout
    DIRECTION INOUT ;
    USE SIGNAL ;
    PORT
      LAYER METAL3 ;
        RECT 0.0 982.0 1.0 983.0 ;
    END
  END scan_out1_bout
  PIN lfxt_wkup_bout
    DIRECTION INOUT ;
    USE SIGNAL ;
    PORT
      LAYER METAL3 ;
        RECT 0.0 933.25 1.0 934.25 ;
    END
  END lfxt_wkup_bout
  PIN lfxt_enable_bout
    DIRECTION INOUT ;
    USE SIGNAL ;
    PORT
      LAYER METAL3 ;
        RECT 0.0 909.5 1.0 910.5 ;
    END
  END lfxt_enable_bout
  PIN dco_wkup_bout
    DIRECTION INOUT ;
    USE SIGNAL ;
    PORT
      LAYER METAL3 ;
        RECT 0.0 885.75 1.0 886.75 ;
    END
  END dco_wkup_bout
  PIN dco_enable_bout
    DIRECTION INOUT ;
    USE SIGNAL ;
    PORT
      LAYER METAL3 ;
        RECT 0.0 862.0 1.0 863.0 ;
    END
  END dco_enable_bout
  PIN dbg_freeze_bout
    DIRECTION INOUT ;
    USE SIGNAL ;
    PORT
      LAYER METAL3 ;
        RECT 0.0 838.25 1.0 839.25 ;
    END
  END dbg_freeze_bout
  PIN Macro_dbg_Scan_RST
    DIRECTION INOUT ;
    USE SIGNAL ;
    PORT
      LAYER METAL3 ;
        RECT 0.0 814.5 1.0 815.5 ;
    END
  END Macro_dbg_Scan_RST
  PIN Macro_dbg_Scan_Din
    DIRECTION INOUT ;
    USE SIGNAL ;
    PORT
      LAYER METAL3 ;
        RECT 0.0 790.75 1.0 791.75 ;
    END
  END Macro_dbg_Scan_Din
  PIN Macro_dbg_Scan_CLK
    DIRECTION INOUT ;
    USE SIGNAL ;
    PORT
      LAYER METAL3 ;
        RECT 0.0 765.75 1.0 766.75 ;
    END
  END Macro_dbg_Scan_CLK
  PIN mmio_reg_in_5<0>
    DIRECTION INOUT ;
    USE SIGNAL ;
    PORT
      LAYER METAL3 ;
        RECT 0.0 1029.5 1.0 1030.5 ;
    END
  END mmio_reg_in_5<0>
  PIN mmio_reg_in_5<1>
    DIRECTION INOUT ;
    USE SIGNAL ;
    PORT
      LAYER METAL3 ;
        RECT 0.0 1053.25 1.0 1054.25 ;
    END
  END mmio_reg_in_5<1>
  PIN mmio_reg_in_5<2>
    DIRECTION INOUT ;
    USE SIGNAL ;
    PORT
      LAYER METAL3 ;
        RECT 0.0 1077.0 1.0 1078.0 ;
    END
  END mmio_reg_in_5<2>
  PIN mmio_reg_in_5<3>
    DIRECTION INOUT ;
    USE SIGNAL ;
    PORT
      LAYER METAL3 ;
        RECT 0.0 1102.0 1.0 1103.0 ;
    END
  END mmio_reg_in_5<3>
  PIN mmio_reg_in_5<4>
    DIRECTION INOUT ;
    USE SIGNAL ;
    PORT
      LAYER METAL3 ;
        RECT 0.0 1125.75 1.0 1126.75 ;
    END
  END mmio_reg_in_5<4>
  PIN mmio_reg_in_5<5>
    DIRECTION INOUT ;
    USE SIGNAL ;
    PORT
      LAYER METAL3 ;
        RECT 0.0 1149.5 1.0 1150.5 ;
    END
  END mmio_reg_in_5<5>
  PIN mmio_reg_in_5<6>
    DIRECTION INOUT ;
    USE SIGNAL ;
    PORT
      LAYER METAL3 ;
        RECT 0.0 1173.25 1.0 1174.25 ;
    END
  END mmio_reg_in_5<6>
  PIN mmio_reg_in_5<7>
    DIRECTION INOUT ;
    USE SIGNAL ;
    PORT
      LAYER METAL3 ;
        RECT 0.0 1197.0 1.0 1198.0 ;
    END
  END mmio_reg_in_5<7>
  PIN mmio_reg_in_5<8>
    DIRECTION INOUT ;
    USE SIGNAL ;
    PORT
      LAYER METAL3 ;
        RECT 0.0 1220.75 1.0 1221.75 ;
    END
  END mmio_reg_in_5<8>
  PIN mmio_reg_in_5<9>
    DIRECTION INOUT ;
    USE SIGNAL ;
    PORT
      LAYER METAL3 ;
        RECT 0.0 1244.5 1.0 1245.5 ;
    END
  END mmio_reg_in_5<9>
  PIN mmio_reg_in_5<10>
    DIRECTION INOUT ;
    USE SIGNAL ;
    PORT
      LAYER METAL3 ;
        RECT 0.0 1269.5 1.0 1270.5 ;
    END
  END mmio_reg_in_5<10>
  PIN mmio_reg_in_5<11>
    DIRECTION INOUT ;
    USE SIGNAL ;
    PORT
      LAYER METAL3 ;
        RECT 0.0 1293.25 1.0 1294.25 ;
    END
  END mmio_reg_in_5<11>
  PIN mmio_reg_in_5<12>
    DIRECTION INOUT ;
    USE SIGNAL ;
    PORT
      LAYER METAL3 ;
        RECT 0.0 1317.0 1.0 1318.0 ;
    END
  END mmio_reg_in_5<12>
  PIN mmio_reg_in_5<13>
    DIRECTION INOUT ;
    USE SIGNAL ;
    PORT
      LAYER METAL3 ;
        RECT 0.0 1340.75 1.0 1341.75 ;
    END
  END mmio_reg_in_5<13>
  PIN mmio_reg_in_5<14>
    DIRECTION INOUT ;
    USE SIGNAL ;
    PORT
      LAYER METAL3 ;
        RECT 0.0 1364.5 1.0 1365.5 ;
    END
  END mmio_reg_in_5<14>
  PIN mmio_reg_in_5<15>
    DIRECTION INOUT ;
    USE SIGNAL ;
    PORT
      LAYER METAL3 ;
        RECT 0.0 1388.25 1.0 1389.25 ;
    END
  END mmio_reg_in_5<15>
  PIN peri_spi_mstr_miso
    DIRECTION INOUT ;
    USE SIGNAL ;
    PORT
      LAYER METAL3 ;
        RECT 0.0 239.5 1.0 240.5 ;
    END
  END peri_spi_mstr_miso
  PIN peri_spi_slave_cs_n
    DIRECTION INOUT ;
    USE SIGNAL ;
    PORT
      LAYER METAL3 ;
        RECT 1411.2 192.0 1412.2 193.0 ;
    END
  END peri_spi_slave_cs_n
  PIN peri_spi_slave_mosi
    DIRECTION INOUT ;
    USE SIGNAL ;
    PORT
      LAYER METAL3 ;
        RECT 1411.2 168.25 1412.2 169.25 ;
    END
  END peri_spi_slave_mosi
  PIN peri_spi_slave_clk
    DIRECTION INOUT ;
    USE SIGNAL ;
    PORT
      LAYER METAL3 ;
        RECT 1411.2 119.5 1412.2 120.5 ;
    END
  END peri_spi_slave_clk
  PIN peri_spi_cpu_clk
    DIRECTION INOUT ;
    USE SIGNAL ;
    PORT
      LAYER METAL3 ;
        RECT 1411.2 95.75 1412.2 96.75 ;
    END
  END peri_spi_cpu_clk
  PIN peri_use_uP
    DIRECTION INOUT ;
    USE SIGNAL ;
    PORT
      LAYER METAL3 ;
        RECT 4779.6 72.0 4780.6 73.0 ;
    END
  END peri_use_uP
  PIN ADC_Trim
    DIRECTION INOUT ;
    USE SIGNAL ;
    PORT
      LAYER METAL4 ;
        RECT 6241.24 293.75 6242.24 294.75 ;
    END
  END ADC_Trim
  PIN GND
    DIRECTION INOUT ;
    USE SIGNAL ;
    PORT
      LAYER METAL4 ;
        RECT 4879.46 45.0 4880.46 46.0 ;
    END
  END GND
END Full_Macro_2p0_abstract

MACRO ConvNN_AvgPool
  PIN n_Kvmm_AP_Dr_bit<9>
    DIRECTION INOUT ;
    USE SIGNAL ;
    PORT
      LAYER METAL3 ;
        RECT 671.3 1946.49 672.7 1948.73 ;
    END
  END n_Kvmm_AP_Dr_bit<9>
  PIN n_Kvmm_AP_Dr_bit<8>
    DIRECTION INOUT ;
    USE SIGNAL ;
    PORT
      LAYER METAL3 ;
        RECT 657.3 1946.49 658.7 1948.73 ;
    END
  END n_Kvmm_AP_Dr_bit<8>
  PIN n_SR_k_col_CLKB
    DIRECTION INOUT ;
    USE SIGNAL ;
    PORT
      LAYER METAL3 ;
        RECT 643.3 1946.49 644.7 1948.73 ;
    END
  END n_SR_k_col_CLKB
  PIN e_sub_img_out<37>
    DIRECTION INOUT ;
    USE SIGNAL ;
    PORT
      LAYER METAL3 ;
        RECT 1894.72 1375.24 1897.02 1376.64 ;
    END
  END e_sub_img_out<37>
  PIN e_sub_img_out<36>
    DIRECTION INOUT ;
    USE SIGNAL ;
    PORT
      LAYER METAL3 ;
        RECT 1894.72 1389.24 1897.02 1390.64 ;
    END
  END e_sub_img_out<36>
  PIN e_sub_img_out<35>
    DIRECTION INOUT ;
    USE SIGNAL ;
    PORT
      LAYER METAL3 ;
        RECT 1894.72 1403.24 1897.02 1404.64 ;
    END
  END e_sub_img_out<35>
  PIN e_sub_img_out<34>
    DIRECTION INOUT ;
    USE SIGNAL ;
    PORT
      LAYER METAL3 ;
        RECT 1894.72 1417.24 1897.02 1418.64 ;
    END
  END e_sub_img_out<34>
  PIN e_sub_img_out<33>
    DIRECTION INOUT ;
    USE SIGNAL ;
    PORT
      LAYER METAL3 ;
        RECT 1894.72 1431.24 1897.02 1432.64 ;
    END
  END e_sub_img_out<33>
  PIN e_sub_img_out<32>
    DIRECTION INOUT ;
    USE SIGNAL ;
    PORT
      LAYER METAL3 ;
        RECT 1894.72 1445.24 1897.02 1446.64 ;
    END
  END e_sub_img_out<32>
  PIN e_sub_img_out<31>
    DIRECTION INOUT ;
    USE SIGNAL ;
    PORT
      LAYER METAL3 ;
        RECT 1894.72 1459.24 1897.02 1460.64 ;
    END
  END e_sub_img_out<31>
  PIN e_sub_img_out<30>
    DIRECTION INOUT ;
    USE SIGNAL ;
    PORT
      LAYER METAL3 ;
        RECT 1894.72 1473.24 1897.02 1474.64 ;
    END
  END e_sub_img_out<30>
  PIN e_sub_img_out<29>
    DIRECTION INOUT ;
    USE SIGNAL ;
    PORT
      LAYER METAL3 ;
        RECT 1894.72 1487.24 1897.02 1488.64 ;
    END
  END e_sub_img_out<29>
  PIN e_sub_img_out<28>
    DIRECTION INOUT ;
    USE SIGNAL ;
    PORT
      LAYER METAL3 ;
        RECT 1894.72 1501.24 1897.02 1502.64 ;
    END
  END e_sub_img_out<28>
  PIN e_sub_img_out<27>
    DIRECTION INOUT ;
    USE SIGNAL ;
    PORT
      LAYER METAL3 ;
        RECT 1894.72 1515.24 1897.02 1516.64 ;
    END
  END e_sub_img_out<27>
  PIN e_sub_img_out<26>
    DIRECTION INOUT ;
    USE SIGNAL ;
    PORT
      LAYER METAL3 ;
        RECT 1894.72 1529.24 1897.02 1530.64 ;
    END
  END e_sub_img_out<26>
  PIN e_sub_img_out<25>
    DIRECTION INOUT ;
    USE SIGNAL ;
    PORT
      LAYER METAL3 ;
        RECT 1894.72 1543.24 1897.02 1544.64 ;
    END
  END e_sub_img_out<25>
  PIN e_sub_img_out<24>
    DIRECTION INOUT ;
    USE SIGNAL ;
    PORT
      LAYER METAL3 ;
        RECT 1894.72 1557.24 1897.02 1558.64 ;
    END
  END e_sub_img_out<24>
  PIN e_sub_img_out<23>
    DIRECTION INOUT ;
    USE SIGNAL ;
    PORT
      LAYER METAL3 ;
        RECT 1894.72 1571.24 1897.02 1572.64 ;
    END
  END e_sub_img_out<23>
  PIN e_sub_img_out<22>
    DIRECTION INOUT ;
    USE SIGNAL ;
    PORT
      LAYER METAL3 ;
        RECT 1894.72 1585.24 1897.02 1586.64 ;
    END
  END e_sub_img_out<22>
  PIN e_sub_img_out<21>
    DIRECTION INOUT ;
    USE SIGNAL ;
    PORT
      LAYER METAL3 ;
        RECT 1894.72 1599.24 1897.02 1600.64 ;
    END
  END e_sub_img_out<21>
  PIN e_sub_img_out<20>
    DIRECTION INOUT ;
    USE SIGNAL ;
    PORT
      LAYER METAL3 ;
        RECT 1894.72 1613.24 1897.02 1614.64 ;
    END
  END e_sub_img_out<20>
  PIN e_sub_img_out<19>
    DIRECTION INOUT ;
    USE SIGNAL ;
    PORT
      LAYER METAL3 ;
        RECT 1894.72 1627.24 1897.02 1628.64 ;
    END
  END e_sub_img_out<19>
  PIN e_sub_img_out<18>
    DIRECTION INOUT ;
    USE SIGNAL ;
    PORT
      LAYER METAL3 ;
        RECT 1894.72 1641.24 1897.02 1642.64 ;
    END
  END e_sub_img_out<18>
  PIN e_sub_img_out<17>
    DIRECTION INOUT ;
    USE SIGNAL ;
    PORT
      LAYER METAL3 ;
        RECT 1894.72 1655.24 1897.02 1656.64 ;
    END
  END e_sub_img_out<17>
  PIN e_sub_img_out<16>
    DIRECTION INOUT ;
    USE SIGNAL ;
    PORT
      LAYER METAL3 ;
        RECT 1894.72 1669.24 1897.02 1670.64 ;
    END
  END e_sub_img_out<16>
  PIN e_sub_img_out<15>
    DIRECTION INOUT ;
    USE SIGNAL ;
    PORT
      LAYER METAL3 ;
        RECT 1894.72 1683.24 1897.02 1684.64 ;
    END
  END e_sub_img_out<15>
  PIN e_sub_img_out<14>
    DIRECTION INOUT ;
    USE SIGNAL ;
    PORT
      LAYER METAL3 ;
        RECT 1894.72 1697.24 1897.02 1698.64 ;
    END
  END e_sub_img_out<14>
  PIN e_sub_img_out<13>
    DIRECTION INOUT ;
    USE SIGNAL ;
    PORT
      LAYER METAL3 ;
        RECT 1894.72 1711.24 1897.02 1712.64 ;
    END
  END e_sub_img_out<13>
  PIN e_sub_img_out<12>
    DIRECTION INOUT ;
    USE SIGNAL ;
    PORT
      LAYER METAL3 ;
        RECT 1894.72 1725.24 1897.02 1726.64 ;
    END
  END e_sub_img_out<12>
  PIN e_sub_img_out<11>
    DIRECTION INOUT ;
    USE SIGNAL ;
    PORT
      LAYER METAL3 ;
        RECT 1894.72 1739.24 1897.02 1740.64 ;
    END
  END e_sub_img_out<11>
  PIN e_sub_img_out<10>
    DIRECTION INOUT ;
    USE SIGNAL ;
    PORT
      LAYER METAL3 ;
        RECT 1894.72 1753.24 1897.02 1754.64 ;
    END
  END e_sub_img_out<10>
  PIN e_sub_img_out<9>
    DIRECTION INOUT ;
    USE SIGNAL ;
    PORT
      LAYER METAL3 ;
        RECT 1894.72 1767.24 1897.02 1768.64 ;
    END
  END e_sub_img_out<9>
  PIN e_sub_img_out<8>
    DIRECTION INOUT ;
    USE SIGNAL ;
    PORT
      LAYER METAL3 ;
        RECT 1894.72 1781.24 1897.02 1782.64 ;
    END
  END e_sub_img_out<8>
  PIN e_sub_img_out<7>
    DIRECTION INOUT ;
    USE SIGNAL ;
    PORT
      LAYER METAL3 ;
        RECT 1894.72 1795.24 1897.02 1796.64 ;
    END
  END e_sub_img_out<7>
  PIN e_sub_img_out<6>
    DIRECTION INOUT ;
    USE SIGNAL ;
    PORT
      LAYER METAL3 ;
        RECT 1894.72 1809.24 1897.02 1810.64 ;
    END
  END e_sub_img_out<6>
  PIN e_sub_img_out<5>
    DIRECTION INOUT ;
    USE SIGNAL ;
    PORT
      LAYER METAL3 ;
        RECT 1894.72 1823.24 1897.02 1824.64 ;
    END
  END e_sub_img_out<5>
  PIN e_sub_img_out<4>
    DIRECTION INOUT ;
    USE SIGNAL ;
    PORT
      LAYER METAL3 ;
        RECT 1894.72 1837.24 1897.02 1838.64 ;
    END
  END e_sub_img_out<4>
  PIN e_sub_img_out<3>
    DIRECTION INOUT ;
    USE SIGNAL ;
    PORT
      LAYER METAL3 ;
        RECT 1894.72 1851.24 1897.02 1852.64 ;
    END
  END e_sub_img_out<3>
  PIN e_sub_img_out<2>
    DIRECTION INOUT ;
    USE SIGNAL ;
    PORT
      LAYER METAL3 ;
        RECT 1894.72 1865.24 1897.02 1866.64 ;
    END
  END e_sub_img_out<2>
  PIN e_sub_img_out<1>
    DIRECTION INOUT ;
    USE SIGNAL ;
    PORT
      LAYER METAL3 ;
        RECT 1894.72 1879.24 1897.02 1880.64 ;
    END
  END e_sub_img_out<1>
  PIN e_sub_img_out<0>
    DIRECTION INOUT ;
    USE SIGNAL ;
    PORT
      LAYER METAL3 ;
        RECT 1894.72 1893.24 1897.02 1894.64 ;
    END
  END e_sub_img_out<0>
  PIN n_Global_rst_b
    DIRECTION INOUT ;
    USE SIGNAL ;
    PORT
      LAYER METAL3 ;
        RECT 629.3 1946.49 630.7 1948.73 ;
    END
  END n_Global_rst_b
  PIN n_AVDD_by_2
    DIRECTION INOUT ;
    USE SIGNAL ;
    PORT
      LAYER METAL3 ;
        RECT 615.3 1946.49 616.7 1948.73 ;
    END
  END n_AVDD_by_2
  PIN n_run_hv
    DIRECTION INOUT ;
    USE SIGNAL ;
    PORT
      LAYER METAL3 ;
        RECT 601.3 1946.49 602.7 1948.73 ;
    END
  END n_run_hv
  PIN n_prog_hv
    DIRECTION INOUT ;
    USE SIGNAL ;
    PORT
      LAYER METAL3 ;
        RECT 587.3 1946.49 588.7 1948.73 ;
    END
  END n_prog_hv
  PIN n_VGPROG
    DIRECTION INOUT ;
    USE SIGNAL ;
    PORT
      LAYER METAL3 ;
        RECT 573.3 1946.49 574.7 1948.73 ;
    END
  END n_VGPROG
  PIN n_VINJ
    DIRECTION INOUT ;
    USE SIGNAL ;
    PORT
      LAYER METAL3 ;
        RECT 559.3 1946.49 560.7 1948.73 ;
    END
  END n_VINJ
  PIN n_GND
    DIRECTION INOUT ;
    USE SIGNAL ;
    PORT
      LAYER METAL3 ;
        RECT 545.3 1946.49 546.7 1948.73 ;
    END
  END n_GND
  PIN n_AVDD
    DIRECTION INOUT ;
    USE SIGNAL ;
    PORT
      LAYER METAL3 ;
        RECT 531.3 1946.49 532.7 1948.73 ;
    END
  END n_AVDD
  PIN n_DVDD
    DIRECTION INOUT ;
    USE SIGNAL ;
    PORT
      LAYER METAL3 ;
        RECT 517.3 1946.49 518.7 1948.73 ;
    END
  END n_DVDD
  PIN n_VTUN
    DIRECTION INOUT ;
    USE SIGNAL ;
    PORT
      LAYER METAL3 ;
        RECT 503.3 1946.49 504.7 1948.73 ;
    END
  END n_VTUN
  PIN n_AP_Relu_Vb
    DIRECTION INOUT ;
    USE SIGNAL ;
    PORT
      LAYER METAL3 ;
        RECT 489.3 1946.49 490.7 1948.73 ;
    END
  END n_AP_Relu_Vb
  PIN n_SR_k_rw_CLK
    DIRECTION INOUT ;
    USE SIGNAL ;
    PORT
      LAYER METAL3 ;
        RECT 475.3 1946.49 476.7 1948.73 ;
    END
  END n_SR_k_rw_CLK
  PIN n_SR_k_rw_RST_B
    DIRECTION INOUT ;
    USE SIGNAL ;
    PORT
      LAYER METAL3 ;
        RECT 461.3 1946.49 462.7 1948.73 ;
    END
  END n_SR_k_rw_RST_B
  PIN n_SR_k_rw_CLKB
    DIRECTION INOUT ;
    USE SIGNAL ;
    PORT
      LAYER METAL3 ;
        RECT 447.3 1946.49 448.7 1948.73 ;
    END
  END n_SR_k_rw_CLKB
  PIN n_SR_k_rw_Din
    DIRECTION INOUT ;
    USE SIGNAL ;
    PORT
      LAYER METAL3 ;
        RECT 433.3 1946.49 434.7 1948.73 ;
    END
  END n_SR_k_rw_Din
  PIN n_SR_Intg_CLKB
    DIRECTION INOUT ;
    USE SIGNAL ;
    PORT
      LAYER METAL3 ;
        RECT 419.3 1946.49 420.7 1948.73 ;
    END
  END n_SR_Intg_CLKB
  PIN n_SR_Intg_CLK
    DIRECTION INOUT ;
    USE SIGNAL ;
    PORT
      LAYER METAL3 ;
        RECT 405.3 1946.49 406.7 1948.73 ;
    END
  END n_SR_Intg_CLK
  PIN n_SR_Intg_Din
    DIRECTION INOUT ;
    USE SIGNAL ;
    PORT
      LAYER METAL3 ;
        RECT 391.3 1946.49 392.7 1948.73 ;
    END
  END n_SR_Intg_Din
  PIN n_SR_Intg_RST_B
    DIRECTION INOUT ;
    USE SIGNAL ;
    PORT
      LAYER METAL3 ;
        RECT 377.3 1946.49 378.7 1948.73 ;
    END
  END n_SR_Intg_RST_B
  PIN n_Vin_inp_Ch<2>
    DIRECTION INOUT ;
    USE SIGNAL ;
    PORT
      LAYER METAL3 ;
        RECT 363.3 1946.49 364.7 1948.73 ;
    END
  END n_Vin_inp_Ch<2>
  PIN n_Vin_inp_Ch<1>
    DIRECTION INOUT ;
    USE SIGNAL ;
    PORT
      LAYER METAL3 ;
        RECT 349.3 1946.49 350.7 1948.73 ;
    END
  END n_Vin_inp_Ch<1>
  PIN n_Vin_inp_Ch<0>
    DIRECTION INOUT ;
    USE SIGNAL ;
    PORT
      LAYER METAL3 ;
        RECT 335.3 1946.49 336.7 1948.73 ;
    END
  END n_Vin_inp_Ch<0>
  PIN n_SR_k_col_CLK
    DIRECTION INOUT ;
    USE SIGNAL ;
    PORT
      LAYER METAL3 ;
        RECT 321.3 1946.49 322.7 1948.73 ;
    END
  END n_SR_k_col_CLK
  PIN n_SR_k_col_RST_B
    DIRECTION INOUT ;
    USE SIGNAL ;
    PORT
      LAYER METAL3 ;
        RECT 307.3 1946.49 308.7 1948.73 ;
    END
  END n_SR_k_col_RST_B
  PIN n_SR_k_col_Din
    DIRECTION INOUT ;
    USE SIGNAL ;
    PORT
      LAYER METAL3 ;
        RECT 293.3 1946.49 294.7 1948.73 ;
    END
  END n_SR_k_col_Din
  PIN n_Kvmm_AP_Run_Drln
    DIRECTION INOUT ;
    USE SIGNAL ;
    PORT
      LAYER METAL3 ;
        RECT 279.3 1946.49 280.7 1948.73 ;
    END
  END n_Kvmm_AP_Run_Drln
  PIN n_Kvmm_AP_Prog_Drln
    DIRECTION INOUT ;
    USE SIGNAL ;
    PORT
      LAYER METAL3 ;
        RECT 265.3 1946.49 266.7 1948.73 ;
    END
  END n_Kvmm_AP_Prog_Drln
  PIN n_Kvmm_AP_Dr_bit<7>
    DIRECTION INOUT ;
    USE SIGNAL ;
    PORT
      LAYER METAL3 ;
        RECT 251.3 1946.49 252.7 1948.73 ;
    END
  END n_Kvmm_AP_Dr_bit<7>
  PIN n_Kvmm_AP_Dr_bit<6>
    DIRECTION INOUT ;
    USE SIGNAL ;
    PORT
      LAYER METAL3 ;
        RECT 237.3 1946.49 238.7 1948.73 ;
    END
  END n_Kvmm_AP_Dr_bit<6>
  PIN n_Kvmm_AP_Dr_bit<5>
    DIRECTION INOUT ;
    USE SIGNAL ;
    PORT
      LAYER METAL3 ;
        RECT 223.3 1946.49 224.7 1948.73 ;
    END
  END n_Kvmm_AP_Dr_bit<5>
  PIN n_Kvmm_AP_Dr_bit<4>
    DIRECTION INOUT ;
    USE SIGNAL ;
    PORT
      LAYER METAL3 ;
        RECT 209.3 1946.49 210.7 1948.73 ;
    END
  END n_Kvmm_AP_Dr_bit<4>
  PIN n_Kvmm_AP_Dr_bit<3>
    DIRECTION INOUT ;
    USE SIGNAL ;
    PORT
      LAYER METAL3 ;
        RECT 195.3 1946.49 196.7 1948.73 ;
    END
  END n_Kvmm_AP_Dr_bit<3>
  PIN n_Kvmm_AP_Dr_bit<2>
    DIRECTION INOUT ;
    USE SIGNAL ;
    PORT
      LAYER METAL3 ;
        RECT 181.3 1946.49 182.7 1948.73 ;
    END
  END n_Kvmm_AP_Dr_bit<2>
  PIN n_Kvmm_AP_Dr_bit<1>
    DIRECTION INOUT ;
    USE SIGNAL ;
    PORT
      LAYER METAL3 ;
        RECT 167.3 1946.49 168.7 1948.73 ;
    END
  END n_Kvmm_AP_Dr_bit<1>
  PIN n_Kvmm_AP_Dr_bit<0>
    DIRECTION INOUT ;
    USE SIGNAL ;
    PORT
      LAYER METAL3 ;
        RECT 153.3 1946.49 154.7 1948.73 ;
    END
  END n_Kvmm_AP_Dr_bit<0>
  PIN n_Kvmm_AP_Dr_En
    DIRECTION INOUT ;
    USE SIGNAL ;
    PORT
      LAYER METAL3 ;
        RECT 139.3 1946.49 140.7 1948.73 ;
    END
  END n_Kvmm_AP_Dr_En
  PIN n_AP_G_bit<2>
    DIRECTION INOUT ;
    USE SIGNAL ;
    PORT
      LAYER METAL3 ;
        RECT 125.3 1946.49 126.7 1948.73 ;
    END
  END n_AP_G_bit<2>
  PIN n_AP_G_bit<1>
    DIRECTION INOUT ;
    USE SIGNAL ;
    PORT
      LAYER METAL3 ;
        RECT 111.3 1946.49 112.7 1948.73 ;
    END
  END n_AP_G_bit<1>
  PIN n_AP_G_bit<0>
    DIRECTION INOUT ;
    USE SIGNAL ;
    PORT
      LAYER METAL3 ;
        RECT 97.3 1946.49 98.7 1948.73 ;
    END
  END n_AP_G_bit<0>
  PIN n_AP_G_En
    DIRECTION INOUT ;
    USE SIGNAL ;
    PORT
      LAYER METAL3 ;
        RECT 83.3 1946.49 84.7 1948.73 ;
    END
  END n_AP_G_En
  PIN n_Kvmm_G_bit<3>
    DIRECTION INOUT ;
    USE SIGNAL ;
    PORT
      LAYER METAL3 ;
        RECT 69.3 1946.49 70.7 1948.73 ;
    END
  END n_Kvmm_G_bit<3>
  PIN n_Kvmm_G_bit<2>
    DIRECTION INOUT ;
    USE SIGNAL ;
    PORT
      LAYER METAL3 ;
        RECT 55.3 1946.49 56.7 1948.73 ;
    END
  END n_Kvmm_G_bit<2>
  PIN n_Kvmm_G_bit<1>
    DIRECTION INOUT ;
    USE SIGNAL ;
    PORT
      LAYER METAL3 ;
        RECT 41.3 1946.49 42.7 1948.73 ;
    END
  END n_Kvmm_G_bit<1>
  PIN n_Kvmm_G_bit<0>
    DIRECTION INOUT ;
    USE SIGNAL ;
    PORT
      LAYER METAL3 ;
        RECT 27.3 1946.49 28.7 1948.73 ;
    END
  END n_Kvmm_G_bit<0>
  PIN n_Kvmm_G_En
    DIRECTION INOUT ;
    USE SIGNAL ;
    PORT
      LAYER METAL3 ;
        RECT 13.3 1946.49 14.7 1948.73 ;
    END
  END n_Kvmm_G_En
  PIN n_Final_rw_dbg
    DIRECTION INOUT ;
    USE SIGNAL ;
    PORT
      LAYER METAL3 ;
        RECT 769.3 1946.49 770.7 1948.73 ;
    END
  END n_Final_rw_dbg
  PIN n_AP_col_ctrl_dbg<0>
    DIRECTION INOUT ;
    USE SIGNAL ;
    PORT
      LAYER METAL3 ;
        RECT 685.3 1946.49 686.7 1948.73 ;
    END
  END n_AP_col_ctrl_dbg<0>
  PIN n_AP_col_ctrl_dbg<1>
    DIRECTION INOUT ;
    USE SIGNAL ;
    PORT
      LAYER METAL3 ;
        RECT 699.3 1946.49 700.7 1948.73 ;
    END
  END n_AP_col_ctrl_dbg<1>
  PIN n_Relu_en_b_dbg<0>
    DIRECTION INOUT ;
    USE SIGNAL ;
    PORT
      LAYER METAL3 ;
        RECT 713.3 1946.49 714.7 1948.73 ;
    END
  END n_Relu_en_b_dbg<0>
  PIN n_Relu_en_b_dbg<1>
    DIRECTION INOUT ;
    USE SIGNAL ;
    PORT
      LAYER METAL3 ;
        RECT 727.3 1946.49 728.7 1948.73 ;
    END
  END n_Relu_en_b_dbg<1>
  PIN n_intg_nxt_rw_dbg
    DIRECTION INOUT ;
    USE SIGNAL ;
    PORT
      LAYER METAL3 ;
        RECT 783.3 1946.49 784.7 1948.73 ;
    END
  END n_intg_nxt_rw_dbg
  PIN n_int_rst_dbg<0>
    DIRECTION INOUT ;
    USE SIGNAL ;
    PORT
      LAYER METAL3 ;
        RECT 741.3 1946.49 742.7 1948.73 ;
    END
  END n_int_rst_dbg<0>
  PIN n_int_rst_dbg<1>
    DIRECTION INOUT ;
    USE SIGNAL ;
    PORT
      LAYER METAL3 ;
        RECT 755.3 1946.49 756.7 1948.73 ;
    END
  END n_int_rst_dbg<1>
  PIN n_SR_int_dbg_Q<2>
    DIRECTION INOUT ;
    USE SIGNAL ;
    PORT
      LAYER METAL3 ;
        RECT 825.3 1946.49 826.7 1948.73 ;
    END
  END n_SR_int_dbg_Q<2>
  PIN n_SR_int_dbg_Q<3>
    DIRECTION INOUT ;
    USE SIGNAL ;
    PORT
      LAYER METAL3 ;
        RECT 839.3 1946.49 840.7 1948.73 ;
    END
  END n_SR_int_dbg_Q<3>
  PIN n_SR_int_dbg_Q<1>
    DIRECTION INOUT ;
    USE SIGNAL ;
    PORT
      LAYER METAL3 ;
        RECT 811.3 1946.49 812.7 1948.73 ;
    END
  END n_SR_int_dbg_Q<1>
  PIN n_SR_int_dbg_Q<0>
    DIRECTION INOUT ;
    USE SIGNAL ;
    PORT
      LAYER METAL3 ;
        RECT 797.3 1946.49 798.7 1948.73 ;
    END
  END n_SR_int_dbg_Q<0>
  PIN n_Vint_dbg<0>
    DIRECTION INOUT ;
    USE SIGNAL ;
    PORT
      LAYER METAL3 ;
        RECT 853.3 1946.49 854.7 1948.73 ;
    END
  END n_Vint_dbg<0>
  PIN n_Vint_dbg<1>
    DIRECTION INOUT ;
    USE SIGNAL ;
    PORT
      LAYER METAL3 ;
        RECT 867.3 1946.49 868.7 1948.73 ;
    END
  END n_Vint_dbg<1>
END ConvNN_AvgPool

MACRO ConvNN
  PIN n_SR_k_col_CLKB
    DIRECTION INOUT ;
    USE SIGNAL ;
    PORT
      LAYER METAL3 ;
        RECT 601.3 1527.93 602.7 1530.17 ;
    END
  END n_SR_k_col_CLKB
  PIN n_Global_rst_b
    DIRECTION INOUT ;
    USE SIGNAL ;
    PORT
      LAYER METAL3 ;
        RECT 559.3 1527.93 560.7 1530.17 ;
    END
  END n_Global_rst_b
  PIN n_AVDD_by_2
    DIRECTION INOUT ;
    USE SIGNAL ;
    PORT
      LAYER METAL3 ;
        RECT 545.3 1527.93 546.7 1530.17 ;
    END
  END n_AVDD_by_2
  PIN n_int_rst_dbg<1>
    DIRECTION INOUT ;
    USE SIGNAL ;
    PORT
      LAYER METAL3 ;
        RECT 657.3 1527.93 658.7 1530.17 ;
    END
  END n_int_rst_dbg<1>
  PIN n_SR_int_0_Q2_dbg
    DIRECTION INOUT ;
    USE SIGNAL ;
    PORT
      LAYER METAL3 ;
        RECT 629.3 1527.93 630.7 1530.17 ;
    END
  END n_SR_int_0_Q2_dbg
  PIN n_SR_Intg_dbg_Q<0>
    DIRECTION INOUT ;
    USE SIGNAL ;
    PORT
      LAYER METAL3 ;
        RECT 713.3 1527.93 714.7 1530.17 ;
    END
  END n_SR_Intg_dbg_Q<0>
  PIN n_sample_nxt_rw_dbg
    DIRECTION INOUT ;
    USE SIGNAL ;
    PORT
      LAYER METAL3 ;
        RECT 671.3 1527.93 672.7 1530.17 ;
    END
  END n_sample_nxt_rw_dbg
  PIN n_Out_En_dbg<0>
    DIRECTION INOUT ;
    USE SIGNAL ;
    PORT
      LAYER METAL3 ;
        RECT 685.3 1527.93 686.7 1530.17 ;
    END
  END n_Out_En_dbg<0>
  PIN n_Vint_dbg<1>
    DIRECTION INOUT ;
    USE SIGNAL ;
    PORT
      LAYER METAL3 ;
        RECT 755.3 1527.93 756.7 1530.17 ;
    END
  END n_Vint_dbg<1>
  PIN n_SR_Intg_dbg_Q<1>
    DIRECTION INOUT ;
    USE SIGNAL ;
    PORT
      LAYER METAL3 ;
        RECT 727.3 1527.93 728.7 1530.17 ;
    END
  END n_SR_Intg_dbg_Q<1>
  PIN n_Vint_dbg<0>
    DIRECTION INOUT ;
    USE SIGNAL ;
    PORT
      LAYER METAL3 ;
        RECT 741.3 1527.93 742.7 1530.17 ;
    END
  END n_Vint_dbg<0>
  PIN n_Rdout_flag_dbg
    DIRECTION INOUT ;
    USE SIGNAL ;
    PORT
      LAYER METAL3 ;
        RECT 615.3 1527.93 616.7 1530.17 ;
    END
  END n_Rdout_flag_dbg
  PIN n_Out_En_dbg<1>
    DIRECTION INOUT ;
    USE SIGNAL ;
    PORT
      LAYER METAL3 ;
        RECT 699.3 1527.93 700.7 1530.17 ;
    END
  END n_Out_En_dbg<1>
  PIN n_int_rst_dbg<0>
    DIRECTION INOUT ;
    USE SIGNAL ;
    PORT
      LAYER METAL3 ;
        RECT 643.3 1527.93 644.7 1530.17 ;
    END
  END n_int_rst_dbg<0>
  PIN n_sample_buf_Vb
    DIRECTION INOUT ;
    USE SIGNAL ;
    PORT
      LAYER METAL3 ;
        RECT 573.3 1527.93 574.7 1530.17 ;
    END
  END n_sample_buf_Vb
  PIN n_Relu_Vb
    DIRECTION INOUT ;
    USE SIGNAL ;
    PORT
      LAYER METAL3 ;
        RECT 587.3 1527.93 588.7 1530.17 ;
    END
  END n_Relu_Vb
  PIN w_Vin_inp_Ch<8>
    DIRECTION INOUT ;
    USE SIGNAL ;
    PORT
      LAYER METAL3 ;
        RECT 0.0 1369.52 2.8 1370.92 ;
    END
  END w_Vin_inp_Ch<8>
  PIN w_Vin_inp_Ch<7>
    DIRECTION INOUT ;
    USE SIGNAL ;
    PORT
      LAYER METAL3 ;
        RECT 0.0 1383.52 2.8 1384.92 ;
    END
  END w_Vin_inp_Ch<7>
  PIN w_Vin_inp_Ch<6>
    DIRECTION INOUT ;
    USE SIGNAL ;
    PORT
      LAYER METAL3 ;
        RECT 0.0 1397.52 2.8 1398.92 ;
    END
  END w_Vin_inp_Ch<6>
  PIN w_Vin_inp_Ch<5>
    DIRECTION INOUT ;
    USE SIGNAL ;
    PORT
      LAYER METAL3 ;
        RECT 0.0 1411.52 2.8 1412.92 ;
    END
  END w_Vin_inp_Ch<5>
  PIN w_Vin_inp_Ch<4>
    DIRECTION INOUT ;
    USE SIGNAL ;
    PORT
      LAYER METAL3 ;
        RECT 0.0 1425.52 2.8 1426.92 ;
    END
  END w_Vin_inp_Ch<4>
  PIN w_Vin_inp_Ch<3>
    DIRECTION INOUT ;
    USE SIGNAL ;
    PORT
      LAYER METAL3 ;
        RECT 0.0 1439.52 2.8 1440.92 ;
    END
  END w_Vin_inp_Ch<3>
  PIN w_Vin_inp_Ch<2>
    DIRECTION INOUT ;
    USE SIGNAL ;
    PORT
      LAYER METAL3 ;
        RECT 0.0 1453.52 2.8 1454.92 ;
    END
  END w_Vin_inp_Ch<2>
  PIN w_Vin_inp_Ch<1>
    DIRECTION INOUT ;
    USE SIGNAL ;
    PORT
      LAYER METAL3 ;
        RECT 0.0 1467.52 2.8 1468.92 ;
    END
  END w_Vin_inp_Ch<1>
  PIN w_Vin_inp_Ch<0>
    DIRECTION INOUT ;
    USE SIGNAL ;
    PORT
      LAYER METAL3 ;
        RECT 0.0 1481.52 2.8 1482.92 ;
    END
  END w_Vin_inp_Ch<0>
  PIN w_Vin_inp_Ch<23>
    DIRECTION INOUT ;
    USE SIGNAL ;
    PORT
      LAYER METAL3 ;
        RECT 0.0 1159.52 2.8 1160.92 ;
    END
  END w_Vin_inp_Ch<23>
  PIN w_Vin_inp_Ch<22>
    DIRECTION INOUT ;
    USE SIGNAL ;
    PORT
      LAYER METAL3 ;
        RECT 0.0 1173.52 2.8 1174.92 ;
    END
  END w_Vin_inp_Ch<22>
  PIN n_run_hv
    DIRECTION INOUT ;
    USE SIGNAL ;
    PORT
      LAYER METAL3 ;
        RECT 531.3 1527.93 532.7 1530.17 ;
    END
  END n_run_hv
  PIN n_prog_hv
    DIRECTION INOUT ;
    USE SIGNAL ;
    PORT
      LAYER METAL3 ;
        RECT 517.3 1527.93 518.7 1530.17 ;
    END
  END n_prog_hv
  PIN n_VGPROG
    DIRECTION INOUT ;
    USE SIGNAL ;
    PORT
      LAYER METAL3 ;
        RECT 503.3 1527.93 504.7 1530.17 ;
    END
  END n_VGPROG
  PIN n_VINJ
    DIRECTION INOUT ;
    USE SIGNAL ;
    PORT
      LAYER METAL3 ;
        RECT 489.3 1527.93 490.7 1530.17 ;
    END
  END n_VINJ
  PIN n_GND
    DIRECTION INOUT ;
    USE SIGNAL ;
    PORT
      LAYER METAL3 ;
        RECT 475.3 1527.93 476.7 1530.17 ;
    END
  END n_GND
  PIN n_AVDD
    DIRECTION INOUT ;
    USE SIGNAL ;
    PORT
      LAYER METAL3 ;
        RECT 461.3 1527.93 462.7 1530.17 ;
    END
  END n_AVDD
  PIN n_DVDD
    DIRECTION INOUT ;
    USE SIGNAL ;
    PORT
      LAYER METAL3 ;
        RECT 447.3 1527.93 448.7 1530.17 ;
    END
  END n_DVDD
  PIN n_VTUN
    DIRECTION INOUT ;
    USE SIGNAL ;
    PORT
      LAYER METAL3 ;
        RECT 433.3 1527.93 434.7 1530.17 ;
    END
  END n_VTUN
  PIN n_SR_k_rw_CLK
    DIRECTION INOUT ;
    USE SIGNAL ;
    PORT
      LAYER METAL3 ;
        RECT 419.3 1527.93 420.7 1530.17 ;
    END
  END n_SR_k_rw_CLK
  PIN n_SR_k_rw_RST_B
    DIRECTION INOUT ;
    USE SIGNAL ;
    PORT
      LAYER METAL3 ;
        RECT 405.3 1527.93 406.7 1530.17 ;
    END
  END n_SR_k_rw_RST_B
  PIN n_SR_k_rw_CLKB
    DIRECTION INOUT ;
    USE SIGNAL ;
    PORT
      LAYER METAL3 ;
        RECT 391.3 1527.93 392.7 1530.17 ;
    END
  END n_SR_k_rw_CLKB
  PIN n_SR_k_rw_Din
    DIRECTION INOUT ;
    USE SIGNAL ;
    PORT
      LAYER METAL3 ;
        RECT 377.3 1527.93 378.7 1530.17 ;
    END
  END n_SR_k_rw_Din
  PIN n_SR_Intg_CLKB
    DIRECTION INOUT ;
    USE SIGNAL ;
    PORT
      LAYER METAL3 ;
        RECT 363.3 1527.93 364.7 1530.17 ;
    END
  END n_SR_Intg_CLKB
  PIN n_SR_Intg_CLK
    DIRECTION INOUT ;
    USE SIGNAL ;
    PORT
      LAYER METAL3 ;
        RECT 349.3 1527.93 350.7 1530.17 ;
    END
  END n_SR_Intg_CLK
  PIN n_SR_Intg_Din
    DIRECTION INOUT ;
    USE SIGNAL ;
    PORT
      LAYER METAL3 ;
        RECT 335.3 1527.93 336.7 1530.17 ;
    END
  END n_SR_Intg_Din
  PIN n_SR_Intg_RST_B
    DIRECTION INOUT ;
    USE SIGNAL ;
    PORT
      LAYER METAL3 ;
        RECT 321.3 1527.93 322.7 1530.17 ;
    END
  END n_SR_Intg_RST_B
  PIN n_SR_k_col_CLK
    DIRECTION INOUT ;
    USE SIGNAL ;
    PORT
      LAYER METAL3 ;
        RECT 307.3 1527.93 308.7 1530.17 ;
    END
  END n_SR_k_col_CLK
  PIN n_SR_k_col_RST_B
    DIRECTION INOUT ;
    USE SIGNAL ;
    PORT
      LAYER METAL3 ;
        RECT 293.3 1527.93 294.7 1530.17 ;
    END
  END n_SR_k_col_RST_B
  PIN n_SR_k_col_Din
    DIRECTION INOUT ;
    USE SIGNAL ;
    PORT
      LAYER METAL3 ;
        RECT 279.3 1527.93 280.7 1530.17 ;
    END
  END n_SR_k_col_Din
  PIN n_Kvmm_Run_Drln
    DIRECTION INOUT ;
    USE SIGNAL ;
    PORT
      LAYER METAL3 ;
        RECT 265.3 1527.93 266.7 1530.17 ;
    END
  END n_Kvmm_Run_Drln
  PIN n_Kvmm_Prog_Drln
    DIRECTION INOUT ;
    USE SIGNAL ;
    PORT
      LAYER METAL3 ;
        RECT 251.3 1527.93 252.7 1530.17 ;
    END
  END n_Kvmm_Prog_Drln
  PIN n_Kvmm_Dr_bit<7>
    DIRECTION INOUT ;
    USE SIGNAL ;
    PORT
      LAYER METAL3 ;
        RECT 237.3 1527.93 238.7 1530.17 ;
    END
  END n_Kvmm_Dr_bit<7>
  PIN n_Kvmm_Dr_bit<6>
    DIRECTION INOUT ;
    USE SIGNAL ;
    PORT
      LAYER METAL3 ;
        RECT 223.3 1527.93 224.7 1530.17 ;
    END
  END n_Kvmm_Dr_bit<6>
  PIN n_Kvmm_Dr_bit<5>
    DIRECTION INOUT ;
    USE SIGNAL ;
    PORT
      LAYER METAL3 ;
        RECT 209.3 1527.93 210.7 1530.17 ;
    END
  END n_Kvmm_Dr_bit<5>
  PIN n_Kvmm_Dr_bit<4>
    DIRECTION INOUT ;
    USE SIGNAL ;
    PORT
      LAYER METAL3 ;
        RECT 195.3 1527.93 196.7 1530.17 ;
    END
  END n_Kvmm_Dr_bit<4>
  PIN n_Kvmm_Dr_bit<3>
    DIRECTION INOUT ;
    USE SIGNAL ;
    PORT
      LAYER METAL3 ;
        RECT 181.3 1527.93 182.7 1530.17 ;
    END
  END n_Kvmm_Dr_bit<3>
  PIN n_Kvmm_Dr_bit<2>
    DIRECTION INOUT ;
    USE SIGNAL ;
    PORT
      LAYER METAL3 ;
        RECT 167.3 1527.93 168.7 1530.17 ;
    END
  END n_Kvmm_Dr_bit<2>
  PIN n_Kvmm_Dr_bit<1>
    DIRECTION INOUT ;
    USE SIGNAL ;
    PORT
      LAYER METAL3 ;
        RECT 153.3 1527.93 154.7 1530.17 ;
    END
  END n_Kvmm_Dr_bit<1>
  PIN n_Kvmm_Dr_bit<0>
    DIRECTION INOUT ;
    USE SIGNAL ;
    PORT
      LAYER METAL3 ;
        RECT 139.3 1527.93 140.7 1530.17 ;
    END
  END n_Kvmm_Dr_bit<0>
  PIN n_Kvmm_Dr_En
    DIRECTION INOUT ;
    USE SIGNAL ;
    PORT
      LAYER METAL3 ;
        RECT 125.3 1527.93 126.7 1530.17 ;
    END
  END n_Kvmm_Dr_En
  PIN n_Kvmm_G_bit<6>
    DIRECTION INOUT ;
    USE SIGNAL ;
    PORT
      LAYER METAL3 ;
        RECT 111.3 1527.93 112.7 1530.17 ;
    END
  END n_Kvmm_G_bit<6>
  PIN n_Kvmm_G_bit<5>
    DIRECTION INOUT ;
    USE SIGNAL ;
    PORT
      LAYER METAL3 ;
        RECT 97.3 1527.93 98.7 1530.17 ;
    END
  END n_Kvmm_G_bit<5>
  PIN n_Kvmm_G_bit<4>
    DIRECTION INOUT ;
    USE SIGNAL ;
    PORT
      LAYER METAL3 ;
        RECT 83.3 1527.93 84.7 1530.17 ;
    END
  END n_Kvmm_G_bit<4>
  PIN n_Kvmm_G_bit<3>
    DIRECTION INOUT ;
    USE SIGNAL ;
    PORT
      LAYER METAL3 ;
        RECT 69.3 1527.93 70.7 1530.17 ;
    END
  END n_Kvmm_G_bit<3>
  PIN n_Kvmm_G_bit<2>
    DIRECTION INOUT ;
    USE SIGNAL ;
    PORT
      LAYER METAL3 ;
        RECT 55.3 1527.93 56.7 1530.17 ;
    END
  END n_Kvmm_G_bit<2>
  PIN n_Kvmm_G_bit<1>
    DIRECTION INOUT ;
    USE SIGNAL ;
    PORT
      LAYER METAL3 ;
        RECT 41.3 1527.93 42.7 1530.17 ;
    END
  END n_Kvmm_G_bit<1>
  PIN n_Kvmm_G_bit<0>
    DIRECTION INOUT ;
    USE SIGNAL ;
    PORT
      LAYER METAL3 ;
        RECT 27.3 1527.93 28.7 1530.17 ;
    END
  END n_Kvmm_G_bit<0>
  PIN n_Kvmm_G_En
    DIRECTION INOUT ;
    USE SIGNAL ;
    PORT
      LAYER METAL3 ;
        RECT 13.3 1527.93 14.7 1530.17 ;
    END
  END n_Kvmm_G_En
  PIN w_Vin_inp_Ch<21>
    DIRECTION INOUT ;
    USE SIGNAL ;
    PORT
      LAYER METAL3 ;
        RECT 0.0 1187.52 2.8 1188.92 ;
    END
  END w_Vin_inp_Ch<21>
  PIN w_Vin_inp_Ch<20>
    DIRECTION INOUT ;
    USE SIGNAL ;
    PORT
      LAYER METAL3 ;
        RECT 0.0 1201.52 2.8 1202.92 ;
    END
  END w_Vin_inp_Ch<20>
  PIN w_Vin_inp_Ch<19>
    DIRECTION INOUT ;
    USE SIGNAL ;
    PORT
      LAYER METAL3 ;
        RECT 0.0 1215.52 2.8 1216.92 ;
    END
  END w_Vin_inp_Ch<19>
  PIN w_Vin_inp_Ch<18>
    DIRECTION INOUT ;
    USE SIGNAL ;
    PORT
      LAYER METAL3 ;
        RECT 0.0 1229.52 2.8 1230.92 ;
    END
  END w_Vin_inp_Ch<18>
  PIN w_Vin_inp_Ch<17>
    DIRECTION INOUT ;
    USE SIGNAL ;
    PORT
      LAYER METAL3 ;
        RECT 0.0 1243.52 2.8 1244.92 ;
    END
  END w_Vin_inp_Ch<17>
  PIN w_Vin_inp_Ch<16>
    DIRECTION INOUT ;
    USE SIGNAL ;
    PORT
      LAYER METAL3 ;
        RECT 0.0 1257.52 2.8 1258.92 ;
    END
  END w_Vin_inp_Ch<16>
  PIN w_Vin_inp_Ch<15>
    DIRECTION INOUT ;
    USE SIGNAL ;
    PORT
      LAYER METAL3 ;
        RECT 0.0 1271.52 2.8 1272.92 ;
    END
  END w_Vin_inp_Ch<15>
  PIN w_Vin_inp_Ch<14>
    DIRECTION INOUT ;
    USE SIGNAL ;
    PORT
      LAYER METAL3 ;
        RECT 0.0 1285.52 2.8 1286.92 ;
    END
  END w_Vin_inp_Ch<14>
  PIN w_Vin_inp_Ch<13>
    DIRECTION INOUT ;
    USE SIGNAL ;
    PORT
      LAYER METAL3 ;
        RECT 0.0 1299.52 2.8 1300.92 ;
    END
  END w_Vin_inp_Ch<13>
  PIN w_Vin_inp_Ch<12>
    DIRECTION INOUT ;
    USE SIGNAL ;
    PORT
      LAYER METAL3 ;
        RECT 0.0 1313.52 2.8 1314.92 ;
    END
  END w_Vin_inp_Ch<12>
  PIN w_Vin_inp_Ch<11>
    DIRECTION INOUT ;
    USE SIGNAL ;
    PORT
      LAYER METAL3 ;
        RECT 0.0 1327.52 2.8 1328.92 ;
    END
  END w_Vin_inp_Ch<11>
  PIN w_Vin_inp_Ch<10>
    DIRECTION INOUT ;
    USE SIGNAL ;
    PORT
      LAYER METAL3 ;
        RECT 0.0 1341.52 2.8 1342.92 ;
    END
  END w_Vin_inp_Ch<10>
  PIN w_Vin_inp_Ch<9>
    DIRECTION INOUT ;
    USE SIGNAL ;
    PORT
      LAYER METAL3 ;
        RECT 0.0 1355.52 2.8 1356.92 ;
    END
  END w_Vin_inp_Ch<9>
  PIN w_Vin_inp_Ch<30>
    DIRECTION INOUT ;
    USE SIGNAL ;
    PORT
      LAYER METAL3 ;
        RECT 0.0 1061.52 2.8 1062.92 ;
    END
  END w_Vin_inp_Ch<30>
  PIN w_Vin_inp_Ch<29>
    DIRECTION INOUT ;
    USE SIGNAL ;
    PORT
      LAYER METAL3 ;
        RECT 0.0 1075.52 2.8 1076.92 ;
    END
  END w_Vin_inp_Ch<29>
  PIN w_Vin_inp_Ch<28>
    DIRECTION INOUT ;
    USE SIGNAL ;
    PORT
      LAYER METAL3 ;
        RECT 0.0 1089.52 2.8 1090.92 ;
    END
  END w_Vin_inp_Ch<28>
  PIN w_Vin_inp_Ch<27>
    DIRECTION INOUT ;
    USE SIGNAL ;
    PORT
      LAYER METAL3 ;
        RECT 0.0 1103.52 2.8 1104.92 ;
    END
  END w_Vin_inp_Ch<27>
  PIN w_Vin_inp_Ch<26>
    DIRECTION INOUT ;
    USE SIGNAL ;
    PORT
      LAYER METAL3 ;
        RECT 0.0 1117.52 2.8 1118.92 ;
    END
  END w_Vin_inp_Ch<26>
  PIN w_Vin_inp_Ch<25>
    DIRECTION INOUT ;
    USE SIGNAL ;
    PORT
      LAYER METAL3 ;
        RECT 0.0 1131.52 2.8 1132.92 ;
    END
  END w_Vin_inp_Ch<25>
  PIN w_Vin_inp_Ch<24>
    DIRECTION INOUT ;
    USE SIGNAL ;
    PORT
      LAYER METAL3 ;
        RECT 0.0 1145.52 2.8 1146.92 ;
    END
  END w_Vin_inp_Ch<24>
  PIN w_sub_img_out<15>
    DIRECTION INOUT ;
    USE SIGNAL ;
    PORT
      LAYER METAL3 ;
        RECT 0.0 767.52 2.8 768.92 ;
    END
  END w_sub_img_out<15>
  PIN w_sub_img_out<14>
    DIRECTION INOUT ;
    USE SIGNAL ;
    PORT
      LAYER METAL3 ;
        RECT 0.0 781.52 2.8 782.92 ;
    END
  END w_sub_img_out<14>
  PIN w_sub_img_out<13>
    DIRECTION INOUT ;
    USE SIGNAL ;
    PORT
      LAYER METAL3 ;
        RECT 0.0 795.52 2.8 796.92 ;
    END
  END w_sub_img_out<13>
  PIN w_sub_img_out<12>
    DIRECTION INOUT ;
    USE SIGNAL ;
    PORT
      LAYER METAL3 ;
        RECT 0.0 809.52 2.8 810.92 ;
    END
  END w_sub_img_out<12>
  PIN w_sub_img_out<11>
    DIRECTION INOUT ;
    USE SIGNAL ;
    PORT
      LAYER METAL3 ;
        RECT 0.0 823.52 2.8 824.92 ;
    END
  END w_sub_img_out<11>
  PIN w_sub_img_out<10>
    DIRECTION INOUT ;
    USE SIGNAL ;
    PORT
      LAYER METAL3 ;
        RECT 0.0 837.52 2.8 838.92 ;
    END
  END w_sub_img_out<10>
  PIN w_sub_img_out<9>
    DIRECTION INOUT ;
    USE SIGNAL ;
    PORT
      LAYER METAL3 ;
        RECT 0.0 851.52 2.8 852.92 ;
    END
  END w_sub_img_out<9>
  PIN w_sub_img_out<8>
    DIRECTION INOUT ;
    USE SIGNAL ;
    PORT
      LAYER METAL3 ;
        RECT 0.0 865.52 2.8 866.92 ;
    END
  END w_sub_img_out<8>
  PIN w_sub_img_out<7>
    DIRECTION INOUT ;
    USE SIGNAL ;
    PORT
      LAYER METAL3 ;
        RECT 0.0 879.52 2.8 880.92 ;
    END
  END w_sub_img_out<7>
  PIN w_sub_img_out<6>
    DIRECTION INOUT ;
    USE SIGNAL ;
    PORT
      LAYER METAL3 ;
        RECT 0.0 893.52 2.8 894.92 ;
    END
  END w_sub_img_out<6>
  PIN w_sub_img_out<5>
    DIRECTION INOUT ;
    USE SIGNAL ;
    PORT
      LAYER METAL3 ;
        RECT 0.0 907.52 2.8 908.92 ;
    END
  END w_sub_img_out<5>
  PIN w_sub_img_out<4>
    DIRECTION INOUT ;
    USE SIGNAL ;
    PORT
      LAYER METAL3 ;
        RECT 0.0 921.52 2.8 922.92 ;
    END
  END w_sub_img_out<4>
  PIN w_sub_img_out<3>
    DIRECTION INOUT ;
    USE SIGNAL ;
    PORT
      LAYER METAL3 ;
        RECT 0.0 935.52 2.8 936.92 ;
    END
  END w_sub_img_out<3>
  PIN w_sub_img_out<2>
    DIRECTION INOUT ;
    USE SIGNAL ;
    PORT
      LAYER METAL3 ;
        RECT 0.0 949.52 2.8 950.92 ;
    END
  END w_sub_img_out<2>
  PIN w_sub_img_out<1>
    DIRECTION INOUT ;
    USE SIGNAL ;
    PORT
      LAYER METAL3 ;
        RECT 0.0 963.52 2.8 964.92 ;
    END
  END w_sub_img_out<1>
  PIN w_sub_img_out<0>
    DIRECTION INOUT ;
    USE SIGNAL ;
    PORT
      LAYER METAL3 ;
        RECT 0.0 977.52 2.8 978.92 ;
    END
  END w_sub_img_out<0>
  PIN w_Vin_inp_Ch<35>
    DIRECTION INOUT ;
    USE SIGNAL ;
    PORT
      LAYER METAL3 ;
        RECT 0.0 991.52 2.8 992.92 ;
    END
  END w_Vin_inp_Ch<35>
  PIN w_Vin_inp_Ch<34>
    DIRECTION INOUT ;
    USE SIGNAL ;
    PORT
      LAYER METAL3 ;
        RECT 0.0 1005.52 2.8 1006.92 ;
    END
  END w_Vin_inp_Ch<34>
  PIN w_Vin_inp_Ch<33>
    DIRECTION INOUT ;
    USE SIGNAL ;
    PORT
      LAYER METAL3 ;
        RECT 0.0 1019.52 2.8 1020.92 ;
    END
  END w_Vin_inp_Ch<33>
  PIN w_Vin_inp_Ch<32>
    DIRECTION INOUT ;
    USE SIGNAL ;
    PORT
      LAYER METAL3 ;
        RECT 0.0 1033.52 2.8 1034.92 ;
    END
  END w_Vin_inp_Ch<32>
  PIN w_Vin_inp_Ch<31>
    DIRECTION INOUT ;
    USE SIGNAL ;
    PORT
      LAYER METAL3 ;
        RECT 0.0 1047.52 2.8 1048.92 ;
    END
  END w_Vin_inp_Ch<31>
  PIN s_sub_img_out<37>
    DIRECTION INOUT ;
    USE SIGNAL ;
    PORT
      LAYER METAL3 ;
        RECT 531.3 0.0 532.7 2.82 ;
    END
  END s_sub_img_out<37>
  PIN s_sub_img_out<36>
    DIRECTION INOUT ;
    USE SIGNAL ;
    PORT
      LAYER METAL3 ;
        RECT 517.3 0.0 518.7 2.82 ;
    END
  END s_sub_img_out<36>
  PIN s_sub_img_out<35>
    DIRECTION INOUT ;
    USE SIGNAL ;
    PORT
      LAYER METAL3 ;
        RECT 503.3 0.0 504.7 2.82 ;
    END
  END s_sub_img_out<35>
  PIN s_sub_img_out<34>
    DIRECTION INOUT ;
    USE SIGNAL ;
    PORT
      LAYER METAL3 ;
        RECT 489.3 0.0 490.7 2.82 ;
    END
  END s_sub_img_out<34>
  PIN s_sub_img_out<33>
    DIRECTION INOUT ;
    USE SIGNAL ;
    PORT
      LAYER METAL3 ;
        RECT 475.3 0.0 476.7 2.82 ;
    END
  END s_sub_img_out<33>
  PIN s_sub_img_out<32>
    DIRECTION INOUT ;
    USE SIGNAL ;
    PORT
      LAYER METAL3 ;
        RECT 461.3 0.0 462.7 2.82 ;
    END
  END s_sub_img_out<32>
  PIN s_sub_img_out<31>
    DIRECTION INOUT ;
    USE SIGNAL ;
    PORT
      LAYER METAL3 ;
        RECT 447.3 0.0 448.7 2.82 ;
    END
  END s_sub_img_out<31>
  PIN s_sub_img_out<30>
    DIRECTION INOUT ;
    USE SIGNAL ;
    PORT
      LAYER METAL3 ;
        RECT 433.3 0.0 434.7 2.82 ;
    END
  END s_sub_img_out<30>
  PIN s_sub_img_out<29>
    DIRECTION INOUT ;
    USE SIGNAL ;
    PORT
      LAYER METAL3 ;
        RECT 419.3 0.0 420.7 2.82 ;
    END
  END s_sub_img_out<29>
  PIN s_sub_img_out<28>
    DIRECTION INOUT ;
    USE SIGNAL ;
    PORT
      LAYER METAL3 ;
        RECT 405.3 0.0 406.7 2.82 ;
    END
  END s_sub_img_out<28>
  PIN s_sub_img_out<27>
    DIRECTION INOUT ;
    USE SIGNAL ;
    PORT
      LAYER METAL3 ;
        RECT 391.3 0.0 392.7 2.82 ;
    END
  END s_sub_img_out<27>
  PIN s_sub_img_out<26>
    DIRECTION INOUT ;
    USE SIGNAL ;
    PORT
      LAYER METAL3 ;
        RECT 377.3 0.0 378.7 2.82 ;
    END
  END s_sub_img_out<26>
  PIN s_sub_img_out<25>
    DIRECTION INOUT ;
    USE SIGNAL ;
    PORT
      LAYER METAL3 ;
        RECT 363.3 0.0 364.7 2.82 ;
    END
  END s_sub_img_out<25>
  PIN s_sub_img_out<24>
    DIRECTION INOUT ;
    USE SIGNAL ;
    PORT
      LAYER METAL3 ;
        RECT 349.3 0.0 350.7 2.82 ;
    END
  END s_sub_img_out<24>
  PIN s_sub_img_out<23>
    DIRECTION INOUT ;
    USE SIGNAL ;
    PORT
      LAYER METAL3 ;
        RECT 335.3 0.0 336.7 2.82 ;
    END
  END s_sub_img_out<23>
  PIN s_sub_img_out<22>
    DIRECTION INOUT ;
    USE SIGNAL ;
    PORT
      LAYER METAL3 ;
        RECT 321.3 0.0 322.7 2.82 ;
    END
  END s_sub_img_out<22>
  PIN s_sub_img_out<21>
    DIRECTION INOUT ;
    USE SIGNAL ;
    PORT
      LAYER METAL3 ;
        RECT 307.3 0.0 308.7 2.82 ;
    END
  END s_sub_img_out<21>
  PIN s_sub_img_out<20>
    DIRECTION INOUT ;
    USE SIGNAL ;
    PORT
      LAYER METAL3 ;
        RECT 293.3 0.0 294.7 2.82 ;
    END
  END s_sub_img_out<20>
  PIN s_sub_img_out<19>
    DIRECTION INOUT ;
    USE SIGNAL ;
    PORT
      LAYER METAL3 ;
        RECT 279.3 0.0 280.7 2.82 ;
    END
  END s_sub_img_out<19>
  PIN s_sub_img_out<18>
    DIRECTION INOUT ;
    USE SIGNAL ;
    PORT
      LAYER METAL3 ;
        RECT 265.3 0.0 266.7 2.82 ;
    END
  END s_sub_img_out<18>
  PIN s_sub_img_out<17>
    DIRECTION INOUT ;
    USE SIGNAL ;
    PORT
      LAYER METAL3 ;
        RECT 251.3 0.0 252.7 2.82 ;
    END
  END s_sub_img_out<17>
  PIN s_sub_img_out<16>
    DIRECTION INOUT ;
    USE SIGNAL ;
    PORT
      LAYER METAL3 ;
        RECT 237.3 0.0 238.7 2.82 ;
    END
  END s_sub_img_out<16>
  PIN s_sub_img_out<15>
    DIRECTION INOUT ;
    USE SIGNAL ;
    PORT
      LAYER METAL3 ;
        RECT 223.3 0.0 224.7 2.82 ;
    END
  END s_sub_img_out<15>
  PIN s_sub_img_out<14>
    DIRECTION INOUT ;
    USE SIGNAL ;
    PORT
      LAYER METAL3 ;
        RECT 209.3 0.0 210.7 2.82 ;
    END
  END s_sub_img_out<14>
  PIN s_sub_img_out<13>
    DIRECTION INOUT ;
    USE SIGNAL ;
    PORT
      LAYER METAL3 ;
        RECT 195.3 0.0 196.7 2.82 ;
    END
  END s_sub_img_out<13>
  PIN s_sub_img_out<12>
    DIRECTION INOUT ;
    USE SIGNAL ;
    PORT
      LAYER METAL3 ;
        RECT 181.3 0.0 182.7 2.82 ;
    END
  END s_sub_img_out<12>
  PIN s_sub_img_out<11>
    DIRECTION INOUT ;
    USE SIGNAL ;
    PORT
      LAYER METAL3 ;
        RECT 167.3 0.0 168.7 2.82 ;
    END
  END s_sub_img_out<11>
  PIN s_sub_img_out<10>
    DIRECTION INOUT ;
    USE SIGNAL ;
    PORT
      LAYER METAL3 ;
        RECT 153.3 0.0 154.7 2.82 ;
    END
  END s_sub_img_out<10>
  PIN s_sub_img_out<9>
    DIRECTION INOUT ;
    USE SIGNAL ;
    PORT
      LAYER METAL3 ;
        RECT 139.3 0.0 140.7 2.82 ;
    END
  END s_sub_img_out<9>
  PIN s_sub_img_out<8>
    DIRECTION INOUT ;
    USE SIGNAL ;
    PORT
      LAYER METAL3 ;
        RECT 125.3 0.0 126.7 2.82 ;
    END
  END s_sub_img_out<8>
  PIN s_sub_img_out<7>
    DIRECTION INOUT ;
    USE SIGNAL ;
    PORT
      LAYER METAL3 ;
        RECT 111.3 0.0 112.7 2.82 ;
    END
  END s_sub_img_out<7>
  PIN s_sub_img_out<6>
    DIRECTION INOUT ;
    USE SIGNAL ;
    PORT
      LAYER METAL3 ;
        RECT 97.3 0.0 98.7 2.82 ;
    END
  END s_sub_img_out<6>
  PIN s_sub_img_out<5>
    DIRECTION INOUT ;
    USE SIGNAL ;
    PORT
      LAYER METAL3 ;
        RECT 83.3 0.0 84.7 2.82 ;
    END
  END s_sub_img_out<5>
  PIN s_sub_img_out<4>
    DIRECTION INOUT ;
    USE SIGNAL ;
    PORT
      LAYER METAL3 ;
        RECT 69.3 0.0 70.7 2.82 ;
    END
  END s_sub_img_out<4>
  PIN s_sub_img_out<3>
    DIRECTION INOUT ;
    USE SIGNAL ;
    PORT
      LAYER METAL3 ;
        RECT 55.3 0.0 56.7 2.82 ;
    END
  END s_sub_img_out<3>
  PIN s_sub_img_out<2>
    DIRECTION INOUT ;
    USE SIGNAL ;
    PORT
      LAYER METAL3 ;
        RECT 41.3 0.0 42.7 2.82 ;
    END
  END s_sub_img_out<2>
  PIN s_sub_img_out<1>
    DIRECTION INOUT ;
    USE SIGNAL ;
    PORT
      LAYER METAL3 ;
        RECT 27.3 0.0 28.7 2.82 ;
    END
  END s_sub_img_out<1>
  PIN s_sub_img_out<0>
    DIRECTION INOUT ;
    USE SIGNAL ;
    PORT
      LAYER METAL3 ;
        RECT 13.3 0.0 14.7 2.82 ;
    END
  END s_sub_img_out<0>
  PIN w_sub_img_out<19>
    DIRECTION INOUT ;
    USE SIGNAL ;
    PORT
      LAYER METAL3 ;
        RECT 0.0 711.52 2.8 712.92 ;
    END
  END w_sub_img_out<19>
  PIN w_sub_img_out<18>
    DIRECTION INOUT ;
    USE SIGNAL ;
    PORT
      LAYER METAL3 ;
        RECT 0.0 725.52 2.8 726.92 ;
    END
  END w_sub_img_out<18>
  PIN w_sub_img_out<17>
    DIRECTION INOUT ;
    USE SIGNAL ;
    PORT
      LAYER METAL3 ;
        RECT 0.0 739.52 2.8 740.92 ;
    END
  END w_sub_img_out<17>
  PIN w_sub_img_out<16>
    DIRECTION INOUT ;
    USE SIGNAL ;
    PORT
      LAYER METAL3 ;
        RECT 0.0 753.52 2.8 754.92 ;
    END
  END w_sub_img_out<16>
  PIN w_sub_img_out<29>
    DIRECTION INOUT ;
    USE SIGNAL ;
    PORT
      LAYER METAL3 ;
        RECT 0.0 571.52 2.8 572.92 ;
    END
  END w_sub_img_out<29>
  PIN w_sub_img_out<28>
    DIRECTION INOUT ;
    USE SIGNAL ;
    PORT
      LAYER METAL3 ;
        RECT 0.0 585.52 2.8 586.92 ;
    END
  END w_sub_img_out<28>
  PIN w_sub_img_out<27>
    DIRECTION INOUT ;
    USE SIGNAL ;
    PORT
      LAYER METAL3 ;
        RECT 0.0 599.52 2.8 600.92 ;
    END
  END w_sub_img_out<27>
  PIN w_sub_img_out<26>
    DIRECTION INOUT ;
    USE SIGNAL ;
    PORT
      LAYER METAL3 ;
        RECT 0.0 613.52 2.8 614.92 ;
    END
  END w_sub_img_out<26>
  PIN w_sub_img_out<25>
    DIRECTION INOUT ;
    USE SIGNAL ;
    PORT
      LAYER METAL3 ;
        RECT 0.0 627.52 2.8 628.92 ;
    END
  END w_sub_img_out<25>
  PIN w_sub_img_out<24>
    DIRECTION INOUT ;
    USE SIGNAL ;
    PORT
      LAYER METAL3 ;
        RECT 0.0 641.52 2.8 642.92 ;
    END
  END w_sub_img_out<24>
  PIN w_sub_img_out<23>
    DIRECTION INOUT ;
    USE SIGNAL ;
    PORT
      LAYER METAL3 ;
        RECT 0.0 655.52 2.8 656.92 ;
    END
  END w_sub_img_out<23>
  PIN w_sub_img_out<22>
    DIRECTION INOUT ;
    USE SIGNAL ;
    PORT
      LAYER METAL3 ;
        RECT 0.0 669.52 2.8 670.92 ;
    END
  END w_sub_img_out<22>
  PIN w_sub_img_out<21>
    DIRECTION INOUT ;
    USE SIGNAL ;
    PORT
      LAYER METAL3 ;
        RECT 0.0 683.52 2.8 684.92 ;
    END
  END w_sub_img_out<21>
  PIN w_sub_img_out<20>
    DIRECTION INOUT ;
    USE SIGNAL ;
    PORT
      LAYER METAL3 ;
        RECT 0.0 697.52 2.8 698.92 ;
    END
  END w_sub_img_out<20>
  PIN s_sub_img_out<76>
    DIRECTION INOUT ;
    USE SIGNAL ;
    PORT
      LAYER METAL3 ;
        RECT 1077.3 0.0 1078.7 2.82 ;
    END
  END s_sub_img_out<76>
  PIN s_sub_img_out<75>
    DIRECTION INOUT ;
    USE SIGNAL ;
    PORT
      LAYER METAL3 ;
        RECT 1063.3 0.0 1064.7 2.82 ;
    END
  END s_sub_img_out<75>
  PIN s_sub_img_out<74>
    DIRECTION INOUT ;
    USE SIGNAL ;
    PORT
      LAYER METAL3 ;
        RECT 1049.3 0.0 1050.7 2.82 ;
    END
  END s_sub_img_out<74>
  PIN s_sub_img_out<73>
    DIRECTION INOUT ;
    USE SIGNAL ;
    PORT
      LAYER METAL3 ;
        RECT 1035.3 0.0 1036.7 2.82 ;
    END
  END s_sub_img_out<73>
  PIN s_sub_img_out<72>
    DIRECTION INOUT ;
    USE SIGNAL ;
    PORT
      LAYER METAL3 ;
        RECT 1021.3 0.0 1022.7 2.82 ;
    END
  END s_sub_img_out<72>
  PIN s_sub_img_out<71>
    DIRECTION INOUT ;
    USE SIGNAL ;
    PORT
      LAYER METAL3 ;
        RECT 1007.3 0.0 1008.7 2.82 ;
    END
  END s_sub_img_out<71>
  PIN s_sub_img_out<70>
    DIRECTION INOUT ;
    USE SIGNAL ;
    PORT
      LAYER METAL3 ;
        RECT 993.3 0.0 994.7 2.82 ;
    END
  END s_sub_img_out<70>
  PIN s_sub_img_out<69>
    DIRECTION INOUT ;
    USE SIGNAL ;
    PORT
      LAYER METAL3 ;
        RECT 979.3 0.0 980.7 2.82 ;
    END
  END s_sub_img_out<69>
  PIN s_sub_img_out<68>
    DIRECTION INOUT ;
    USE SIGNAL ;
    PORT
      LAYER METAL3 ;
        RECT 965.3 0.0 966.7 2.82 ;
    END
  END s_sub_img_out<68>
  PIN s_sub_img_out<67>
    DIRECTION INOUT ;
    USE SIGNAL ;
    PORT
      LAYER METAL3 ;
        RECT 951.3 0.0 952.7 2.82 ;
    END
  END s_sub_img_out<67>
  PIN s_sub_img_out<66>
    DIRECTION INOUT ;
    USE SIGNAL ;
    PORT
      LAYER METAL3 ;
        RECT 937.3 0.0 938.7 2.82 ;
    END
  END s_sub_img_out<66>
  PIN s_sub_img_out<65>
    DIRECTION INOUT ;
    USE SIGNAL ;
    PORT
      LAYER METAL3 ;
        RECT 923.3 0.0 924.7 2.82 ;
    END
  END s_sub_img_out<65>
  PIN s_sub_img_out<64>
    DIRECTION INOUT ;
    USE SIGNAL ;
    PORT
      LAYER METAL3 ;
        RECT 909.3 0.0 910.7 2.82 ;
    END
  END s_sub_img_out<64>
  PIN s_sub_img_out<63>
    DIRECTION INOUT ;
    USE SIGNAL ;
    PORT
      LAYER METAL3 ;
        RECT 895.3 0.0 896.7 2.82 ;
    END
  END s_sub_img_out<63>
  PIN s_sub_img_out<62>
    DIRECTION INOUT ;
    USE SIGNAL ;
    PORT
      LAYER METAL3 ;
        RECT 881.3 0.0 882.7 2.82 ;
    END
  END s_sub_img_out<62>
  PIN s_sub_img_out<61>
    DIRECTION INOUT ;
    USE SIGNAL ;
    PORT
      LAYER METAL3 ;
        RECT 867.3 0.0 868.7 2.82 ;
    END
  END s_sub_img_out<61>
  PIN s_sub_img_out<60>
    DIRECTION INOUT ;
    USE SIGNAL ;
    PORT
      LAYER METAL3 ;
        RECT 853.3 0.0 854.7 2.82 ;
    END
  END s_sub_img_out<60>
  PIN s_sub_img_out<59>
    DIRECTION INOUT ;
    USE SIGNAL ;
    PORT
      LAYER METAL3 ;
        RECT 839.3 0.0 840.7 2.82 ;
    END
  END s_sub_img_out<59>
  PIN s_sub_img_out<58>
    DIRECTION INOUT ;
    USE SIGNAL ;
    PORT
      LAYER METAL3 ;
        RECT 825.3 0.0 826.7 2.82 ;
    END
  END s_sub_img_out<58>
  PIN s_sub_img_out<57>
    DIRECTION INOUT ;
    USE SIGNAL ;
    PORT
      LAYER METAL3 ;
        RECT 811.3 0.0 812.7 2.82 ;
    END
  END s_sub_img_out<57>
  PIN s_sub_img_out<56>
    DIRECTION INOUT ;
    USE SIGNAL ;
    PORT
      LAYER METAL3 ;
        RECT 797.3 0.0 798.7 2.82 ;
    END
  END s_sub_img_out<56>
  PIN s_sub_img_out<55>
    DIRECTION INOUT ;
    USE SIGNAL ;
    PORT
      LAYER METAL3 ;
        RECT 783.3 0.0 784.7 2.82 ;
    END
  END s_sub_img_out<55>
  PIN s_sub_img_out<54>
    DIRECTION INOUT ;
    USE SIGNAL ;
    PORT
      LAYER METAL3 ;
        RECT 769.3 0.0 770.7 2.82 ;
    END
  END s_sub_img_out<54>
  PIN s_sub_img_out<53>
    DIRECTION INOUT ;
    USE SIGNAL ;
    PORT
      LAYER METAL3 ;
        RECT 755.3 0.0 756.7 2.82 ;
    END
  END s_sub_img_out<53>
  PIN s_sub_img_out<52>
    DIRECTION INOUT ;
    USE SIGNAL ;
    PORT
      LAYER METAL3 ;
        RECT 741.3 0.0 742.7 2.82 ;
    END
  END s_sub_img_out<52>
  PIN s_sub_img_out<51>
    DIRECTION INOUT ;
    USE SIGNAL ;
    PORT
      LAYER METAL3 ;
        RECT 727.3 0.0 728.7 2.82 ;
    END
  END s_sub_img_out<51>
  PIN s_sub_img_out<50>
    DIRECTION INOUT ;
    USE SIGNAL ;
    PORT
      LAYER METAL3 ;
        RECT 713.3 0.0 714.7 2.82 ;
    END
  END s_sub_img_out<50>
  PIN s_sub_img_out<49>
    DIRECTION INOUT ;
    USE SIGNAL ;
    PORT
      LAYER METAL3 ;
        RECT 699.3 0.0 700.7 2.82 ;
    END
  END s_sub_img_out<49>
  PIN s_sub_img_out<48>
    DIRECTION INOUT ;
    USE SIGNAL ;
    PORT
      LAYER METAL3 ;
        RECT 685.3 0.0 686.7 2.82 ;
    END
  END s_sub_img_out<48>
  PIN s_sub_img_out<47>
    DIRECTION INOUT ;
    USE SIGNAL ;
    PORT
      LAYER METAL3 ;
        RECT 671.3 0.0 672.7 2.82 ;
    END
  END s_sub_img_out<47>
  PIN s_sub_img_out<46>
    DIRECTION INOUT ;
    USE SIGNAL ;
    PORT
      LAYER METAL3 ;
        RECT 657.3 0.0 658.7 2.82 ;
    END
  END s_sub_img_out<46>
  PIN s_sub_img_out<45>
    DIRECTION INOUT ;
    USE SIGNAL ;
    PORT
      LAYER METAL3 ;
        RECT 643.3 0.0 644.7 2.82 ;
    END
  END s_sub_img_out<45>
  PIN s_sub_img_out<44>
    DIRECTION INOUT ;
    USE SIGNAL ;
    PORT
      LAYER METAL3 ;
        RECT 629.3 0.0 630.7 2.82 ;
    END
  END s_sub_img_out<44>
  PIN s_sub_img_out<43>
    DIRECTION INOUT ;
    USE SIGNAL ;
    PORT
      LAYER METAL3 ;
        RECT 615.3 0.0 616.7 2.82 ;
    END
  END s_sub_img_out<43>
  PIN s_sub_img_out<42>
    DIRECTION INOUT ;
    USE SIGNAL ;
    PORT
      LAYER METAL3 ;
        RECT 601.3 0.0 602.7 2.82 ;
    END
  END s_sub_img_out<42>
  PIN s_sub_img_out<41>
    DIRECTION INOUT ;
    USE SIGNAL ;
    PORT
      LAYER METAL3 ;
        RECT 587.3 0.0 588.7 2.82 ;
    END
  END s_sub_img_out<41>
  PIN s_sub_img_out<40>
    DIRECTION INOUT ;
    USE SIGNAL ;
    PORT
      LAYER METAL3 ;
        RECT 573.3 0.0 574.7 2.82 ;
    END
  END s_sub_img_out<40>
  PIN s_sub_img_out<39>
    DIRECTION INOUT ;
    USE SIGNAL ;
    PORT
      LAYER METAL3 ;
        RECT 559.3 0.0 560.7 2.82 ;
    END
  END s_sub_img_out<39>
  PIN s_sub_img_out<38>
    DIRECTION INOUT ;
    USE SIGNAL ;
    PORT
      LAYER METAL3 ;
        RECT 545.3 0.0 546.7 2.82 ;
    END
  END s_sub_img_out<38>
  PIN s_sub_img_out<100>
    DIRECTION INOUT ;
    USE SIGNAL ;
    PORT
      LAYER METAL3 ;
        RECT 1413.3 0.0 1414.7 2.82 ;
    END
  END s_sub_img_out<100>
  PIN s_sub_img_out<99>
    DIRECTION INOUT ;
    USE SIGNAL ;
    PORT
      LAYER METAL3 ;
        RECT 1399.3 0.0 1400.7 2.82 ;
    END
  END s_sub_img_out<99>
  PIN s_sub_img_out<98>
    DIRECTION INOUT ;
    USE SIGNAL ;
    PORT
      LAYER METAL3 ;
        RECT 1385.3 0.0 1386.7 2.82 ;
    END
  END s_sub_img_out<98>
  PIN s_sub_img_out<97>
    DIRECTION INOUT ;
    USE SIGNAL ;
    PORT
      LAYER METAL3 ;
        RECT 1371.3 0.0 1372.7 2.82 ;
    END
  END s_sub_img_out<97>
  PIN s_sub_img_out<96>
    DIRECTION INOUT ;
    USE SIGNAL ;
    PORT
      LAYER METAL3 ;
        RECT 1357.3 0.0 1358.7 2.82 ;
    END
  END s_sub_img_out<96>
  PIN s_sub_img_out<95>
    DIRECTION INOUT ;
    USE SIGNAL ;
    PORT
      LAYER METAL3 ;
        RECT 1343.3 0.0 1344.7 2.82 ;
    END
  END s_sub_img_out<95>
  PIN s_sub_img_out<94>
    DIRECTION INOUT ;
    USE SIGNAL ;
    PORT
      LAYER METAL3 ;
        RECT 1329.3 0.0 1330.7 2.82 ;
    END
  END s_sub_img_out<94>
  PIN s_sub_img_out<93>
    DIRECTION INOUT ;
    USE SIGNAL ;
    PORT
      LAYER METAL3 ;
        RECT 1315.3 0.0 1316.7 2.82 ;
    END
  END s_sub_img_out<93>
  PIN s_sub_img_out<92>
    DIRECTION INOUT ;
    USE SIGNAL ;
    PORT
      LAYER METAL3 ;
        RECT 1301.3 0.0 1302.7 2.82 ;
    END
  END s_sub_img_out<92>
  PIN s_sub_img_out<91>
    DIRECTION INOUT ;
    USE SIGNAL ;
    PORT
      LAYER METAL3 ;
        RECT 1287.3 0.0 1288.7 2.82 ;
    END
  END s_sub_img_out<91>
  PIN s_sub_img_out<90>
    DIRECTION INOUT ;
    USE SIGNAL ;
    PORT
      LAYER METAL3 ;
        RECT 1273.3 0.0 1274.7 2.82 ;
    END
  END s_sub_img_out<90>
  PIN s_sub_img_out<89>
    DIRECTION INOUT ;
    USE SIGNAL ;
    PORT
      LAYER METAL3 ;
        RECT 1259.3 0.0 1260.7 2.82 ;
    END
  END s_sub_img_out<89>
  PIN s_sub_img_out<88>
    DIRECTION INOUT ;
    USE SIGNAL ;
    PORT
      LAYER METAL3 ;
        RECT 1245.3 0.0 1246.7 2.82 ;
    END
  END s_sub_img_out<88>
  PIN s_sub_img_out<87>
    DIRECTION INOUT ;
    USE SIGNAL ;
    PORT
      LAYER METAL3 ;
        RECT 1231.3 0.0 1232.7 2.82 ;
    END
  END s_sub_img_out<87>
  PIN s_sub_img_out<86>
    DIRECTION INOUT ;
    USE SIGNAL ;
    PORT
      LAYER METAL3 ;
        RECT 1217.3 0.0 1218.7 2.82 ;
    END
  END s_sub_img_out<86>
  PIN s_sub_img_out<85>
    DIRECTION INOUT ;
    USE SIGNAL ;
    PORT
      LAYER METAL3 ;
        RECT 1203.3 0.0 1204.7 2.82 ;
    END
  END s_sub_img_out<85>
  PIN s_sub_img_out<84>
    DIRECTION INOUT ;
    USE SIGNAL ;
    PORT
      LAYER METAL3 ;
        RECT 1189.3 0.0 1190.7 2.82 ;
    END
  END s_sub_img_out<84>
  PIN s_sub_img_out<83>
    DIRECTION INOUT ;
    USE SIGNAL ;
    PORT
      LAYER METAL3 ;
        RECT 1175.3 0.0 1176.7 2.82 ;
    END
  END s_sub_img_out<83>
  PIN s_sub_img_out<82>
    DIRECTION INOUT ;
    USE SIGNAL ;
    PORT
      LAYER METAL3 ;
        RECT 1161.3 0.0 1162.7 2.82 ;
    END
  END s_sub_img_out<82>
  PIN s_sub_img_out<81>
    DIRECTION INOUT ;
    USE SIGNAL ;
    PORT
      LAYER METAL3 ;
        RECT 1147.3 0.0 1148.7 2.82 ;
    END
  END s_sub_img_out<81>
  PIN s_sub_img_out<80>
    DIRECTION INOUT ;
    USE SIGNAL ;
    PORT
      LAYER METAL3 ;
        RECT 1133.3 0.0 1134.7 2.82 ;
    END
  END s_sub_img_out<80>
  PIN s_sub_img_out<79>
    DIRECTION INOUT ;
    USE SIGNAL ;
    PORT
      LAYER METAL3 ;
        RECT 1119.3 0.0 1120.7 2.82 ;
    END
  END s_sub_img_out<79>
  PIN s_sub_img_out<78>
    DIRECTION INOUT ;
    USE SIGNAL ;
    PORT
      LAYER METAL3 ;
        RECT 1105.3 0.0 1106.7 2.82 ;
    END
  END s_sub_img_out<78>
  PIN s_sub_img_out<77>
    DIRECTION INOUT ;
    USE SIGNAL ;
    PORT
      LAYER METAL3 ;
        RECT 1091.3 0.0 1092.7 2.82 ;
    END
  END s_sub_img_out<77>
  PIN s_sub_img_out<153>
    DIRECTION INOUT ;
    USE SIGNAL ;
    PORT
      LAYER METAL3 ;
        RECT 2155.3 0.0 2156.7 2.82 ;
    END
  END s_sub_img_out<153>
  PIN s_sub_img_out<152>
    DIRECTION INOUT ;
    USE SIGNAL ;
    PORT
      LAYER METAL3 ;
        RECT 2141.3 0.0 2142.7 2.82 ;
    END
  END s_sub_img_out<152>
  PIN s_sub_img_out<151>
    DIRECTION INOUT ;
    USE SIGNAL ;
    PORT
      LAYER METAL3 ;
        RECT 2127.3 0.0 2128.7 2.82 ;
    END
  END s_sub_img_out<151>
  PIN s_sub_img_out<150>
    DIRECTION INOUT ;
    USE SIGNAL ;
    PORT
      LAYER METAL3 ;
        RECT 2113.3 0.0 2114.7 2.82 ;
    END
  END s_sub_img_out<150>
  PIN s_sub_img_out<149>
    DIRECTION INOUT ;
    USE SIGNAL ;
    PORT
      LAYER METAL3 ;
        RECT 2099.3 0.0 2100.7 2.82 ;
    END
  END s_sub_img_out<149>
  PIN s_sub_img_out<148>
    DIRECTION INOUT ;
    USE SIGNAL ;
    PORT
      LAYER METAL3 ;
        RECT 2085.3 0.0 2086.7 2.82 ;
    END
  END s_sub_img_out<148>
  PIN s_sub_img_out<147>
    DIRECTION INOUT ;
    USE SIGNAL ;
    PORT
      LAYER METAL3 ;
        RECT 2071.3 0.0 2072.7 2.82 ;
    END
  END s_sub_img_out<147>
  PIN s_sub_img_out<146>
    DIRECTION INOUT ;
    USE SIGNAL ;
    PORT
      LAYER METAL3 ;
        RECT 2057.3 0.0 2058.7 2.82 ;
    END
  END s_sub_img_out<146>
  PIN s_sub_img_out<145>
    DIRECTION INOUT ;
    USE SIGNAL ;
    PORT
      LAYER METAL3 ;
        RECT 2043.3 0.0 2044.7 2.82 ;
    END
  END s_sub_img_out<145>
  PIN s_sub_img_out<144>
    DIRECTION INOUT ;
    USE SIGNAL ;
    PORT
      LAYER METAL3 ;
        RECT 2029.3 0.0 2030.7 2.82 ;
    END
  END s_sub_img_out<144>
  PIN s_sub_img_out<143>
    DIRECTION INOUT ;
    USE SIGNAL ;
    PORT
      LAYER METAL3 ;
        RECT 2015.3 0.0 2016.7 2.82 ;
    END
  END s_sub_img_out<143>
  PIN s_sub_img_out<142>
    DIRECTION INOUT ;
    USE SIGNAL ;
    PORT
      LAYER METAL3 ;
        RECT 2001.3 0.0 2002.7 2.82 ;
    END
  END s_sub_img_out<142>
  PIN s_sub_img_out<141>
    DIRECTION INOUT ;
    USE SIGNAL ;
    PORT
      LAYER METAL3 ;
        RECT 1987.3 0.0 1988.7 2.82 ;
    END
  END s_sub_img_out<141>
  PIN s_sub_img_out<140>
    DIRECTION INOUT ;
    USE SIGNAL ;
    PORT
      LAYER METAL3 ;
        RECT 1973.3 0.0 1974.7 2.82 ;
    END
  END s_sub_img_out<140>
  PIN s_sub_img_out<139>
    DIRECTION INOUT ;
    USE SIGNAL ;
    PORT
      LAYER METAL3 ;
        RECT 1959.3 0.0 1960.7 2.82 ;
    END
  END s_sub_img_out<139>
  PIN s_sub_img_out<138>
    DIRECTION INOUT ;
    USE SIGNAL ;
    PORT
      LAYER METAL3 ;
        RECT 1945.3 0.0 1946.7 2.82 ;
    END
  END s_sub_img_out<138>
  PIN s_sub_img_out<137>
    DIRECTION INOUT ;
    USE SIGNAL ;
    PORT
      LAYER METAL3 ;
        RECT 1931.3 0.0 1932.7 2.82 ;
    END
  END s_sub_img_out<137>
  PIN s_sub_img_out<136>
    DIRECTION INOUT ;
    USE SIGNAL ;
    PORT
      LAYER METAL3 ;
        RECT 1917.3 0.0 1918.7 2.82 ;
    END
  END s_sub_img_out<136>
  PIN s_sub_img_out<135>
    DIRECTION INOUT ;
    USE SIGNAL ;
    PORT
      LAYER METAL3 ;
        RECT 1903.3 0.0 1904.7 2.82 ;
    END
  END s_sub_img_out<135>
  PIN s_sub_img_out<134>
    DIRECTION INOUT ;
    USE SIGNAL ;
    PORT
      LAYER METAL3 ;
        RECT 1889.3 0.0 1890.7 2.82 ;
    END
  END s_sub_img_out<134>
  PIN s_sub_img_out<133>
    DIRECTION INOUT ;
    USE SIGNAL ;
    PORT
      LAYER METAL3 ;
        RECT 1875.3 0.0 1876.7 2.82 ;
    END
  END s_sub_img_out<133>
  PIN s_sub_img_out<132>
    DIRECTION INOUT ;
    USE SIGNAL ;
    PORT
      LAYER METAL3 ;
        RECT 1861.3 0.0 1862.7 2.82 ;
    END
  END s_sub_img_out<132>
  PIN s_sub_img_out<131>
    DIRECTION INOUT ;
    USE SIGNAL ;
    PORT
      LAYER METAL3 ;
        RECT 1847.3 0.0 1848.7 2.82 ;
    END
  END s_sub_img_out<131>
  PIN s_sub_img_out<130>
    DIRECTION INOUT ;
    USE SIGNAL ;
    PORT
      LAYER METAL3 ;
        RECT 1833.3 0.0 1834.7 2.82 ;
    END
  END s_sub_img_out<130>
  PIN s_sub_img_out<129>
    DIRECTION INOUT ;
    USE SIGNAL ;
    PORT
      LAYER METAL3 ;
        RECT 1819.3 0.0 1820.7 2.82 ;
    END
  END s_sub_img_out<129>
  PIN s_sub_img_out<128>
    DIRECTION INOUT ;
    USE SIGNAL ;
    PORT
      LAYER METAL3 ;
        RECT 1805.3 0.0 1806.7 2.82 ;
    END
  END s_sub_img_out<128>
  PIN s_sub_img_out<127>
    DIRECTION INOUT ;
    USE SIGNAL ;
    PORT
      LAYER METAL3 ;
        RECT 1791.3 0.0 1792.7 2.82 ;
    END
  END s_sub_img_out<127>
  PIN s_sub_img_out<126>
    DIRECTION INOUT ;
    USE SIGNAL ;
    PORT
      LAYER METAL3 ;
        RECT 1777.3 0.0 1778.7 2.82 ;
    END
  END s_sub_img_out<126>
  PIN s_sub_img_out<125>
    DIRECTION INOUT ;
    USE SIGNAL ;
    PORT
      LAYER METAL3 ;
        RECT 1763.3 0.0 1764.7 2.82 ;
    END
  END s_sub_img_out<125>
  PIN s_sub_img_out<124>
    DIRECTION INOUT ;
    USE SIGNAL ;
    PORT
      LAYER METAL3 ;
        RECT 1749.3 0.0 1750.7 2.82 ;
    END
  END s_sub_img_out<124>
  PIN s_sub_img_out<123>
    DIRECTION INOUT ;
    USE SIGNAL ;
    PORT
      LAYER METAL3 ;
        RECT 1735.3 0.0 1736.7 2.82 ;
    END
  END s_sub_img_out<123>
  PIN s_sub_img_out<122>
    DIRECTION INOUT ;
    USE SIGNAL ;
    PORT
      LAYER METAL3 ;
        RECT 1721.3 0.0 1722.7 2.82 ;
    END
  END s_sub_img_out<122>
  PIN s_sub_img_out<121>
    DIRECTION INOUT ;
    USE SIGNAL ;
    PORT
      LAYER METAL3 ;
        RECT 1707.3 0.0 1708.7 2.82 ;
    END
  END s_sub_img_out<121>
  PIN s_sub_img_out<120>
    DIRECTION INOUT ;
    USE SIGNAL ;
    PORT
      LAYER METAL3 ;
        RECT 1693.3 0.0 1694.7 2.82 ;
    END
  END s_sub_img_out<120>
  PIN s_sub_img_out<119>
    DIRECTION INOUT ;
    USE SIGNAL ;
    PORT
      LAYER METAL3 ;
        RECT 1679.3 0.0 1680.7 2.82 ;
    END
  END s_sub_img_out<119>
  PIN s_sub_img_out<118>
    DIRECTION INOUT ;
    USE SIGNAL ;
    PORT
      LAYER METAL3 ;
        RECT 1665.3 0.0 1666.7 2.82 ;
    END
  END s_sub_img_out<118>
  PIN s_sub_img_out<117>
    DIRECTION INOUT ;
    USE SIGNAL ;
    PORT
      LAYER METAL3 ;
        RECT 1651.3 0.0 1652.7 2.82 ;
    END
  END s_sub_img_out<117>
  PIN s_sub_img_out<116>
    DIRECTION INOUT ;
    USE SIGNAL ;
    PORT
      LAYER METAL3 ;
        RECT 1637.3 0.0 1638.7 2.82 ;
    END
  END s_sub_img_out<116>
  PIN s_sub_img_out<115>
    DIRECTION INOUT ;
    USE SIGNAL ;
    PORT
      LAYER METAL3 ;
        RECT 1623.3 0.0 1624.7 2.82 ;
    END
  END s_sub_img_out<115>
  PIN s_sub_img_out<114>
    DIRECTION INOUT ;
    USE SIGNAL ;
    PORT
      LAYER METAL3 ;
        RECT 1609.3 0.0 1610.7 2.82 ;
    END
  END s_sub_img_out<114>
  PIN s_sub_img_out<113>
    DIRECTION INOUT ;
    USE SIGNAL ;
    PORT
      LAYER METAL3 ;
        RECT 1595.3 0.0 1596.7 2.82 ;
    END
  END s_sub_img_out<113>
  PIN s_sub_img_out<112>
    DIRECTION INOUT ;
    USE SIGNAL ;
    PORT
      LAYER METAL3 ;
        RECT 1581.3 0.0 1582.7 2.82 ;
    END
  END s_sub_img_out<112>
  PIN s_sub_img_out<111>
    DIRECTION INOUT ;
    USE SIGNAL ;
    PORT
      LAYER METAL3 ;
        RECT 1567.3 0.0 1568.7 2.82 ;
    END
  END s_sub_img_out<111>
  PIN s_sub_img_out<110>
    DIRECTION INOUT ;
    USE SIGNAL ;
    PORT
      LAYER METAL3 ;
        RECT 1553.3 0.0 1554.7 2.82 ;
    END
  END s_sub_img_out<110>
  PIN s_sub_img_out<109>
    DIRECTION INOUT ;
    USE SIGNAL ;
    PORT
      LAYER METAL3 ;
        RECT 1539.3 0.0 1540.7 2.82 ;
    END
  END s_sub_img_out<109>
  PIN s_sub_img_out<108>
    DIRECTION INOUT ;
    USE SIGNAL ;
    PORT
      LAYER METAL3 ;
        RECT 1525.3 0.0 1526.7 2.82 ;
    END
  END s_sub_img_out<108>
  PIN s_sub_img_out<107>
    DIRECTION INOUT ;
    USE SIGNAL ;
    PORT
      LAYER METAL3 ;
        RECT 1511.3 0.0 1512.7 2.82 ;
    END
  END s_sub_img_out<107>
  PIN s_sub_img_out<106>
    DIRECTION INOUT ;
    USE SIGNAL ;
    PORT
      LAYER METAL3 ;
        RECT 1497.3 0.0 1498.7 2.82 ;
    END
  END s_sub_img_out<106>
  PIN s_sub_img_out<105>
    DIRECTION INOUT ;
    USE SIGNAL ;
    PORT
      LAYER METAL3 ;
        RECT 1483.3 0.0 1484.7 2.82 ;
    END
  END s_sub_img_out<105>
  PIN s_sub_img_out<104>
    DIRECTION INOUT ;
    USE SIGNAL ;
    PORT
      LAYER METAL3 ;
        RECT 1469.3 0.0 1470.7 2.82 ;
    END
  END s_sub_img_out<104>
  PIN s_sub_img_out<103>
    DIRECTION INOUT ;
    USE SIGNAL ;
    PORT
      LAYER METAL3 ;
        RECT 1455.3 0.0 1456.7 2.82 ;
    END
  END s_sub_img_out<103>
  PIN s_sub_img_out<102>
    DIRECTION INOUT ;
    USE SIGNAL ;
    PORT
      LAYER METAL3 ;
        RECT 1441.3 0.0 1442.7 2.82 ;
    END
  END s_sub_img_out<102>
  PIN s_sub_img_out<101>
    DIRECTION INOUT ;
    USE SIGNAL ;
    PORT
      LAYER METAL3 ;
        RECT 1427.3 0.0 1428.7 2.82 ;
    END
  END s_sub_img_out<101>
END ConvNN

MACRO FullyCon_NN
  PIN n_WTA_final_Vbias
    DIRECTION INOUT ;
    USE SIGNAL ;
    PORT
      LAYER METAL3 ;
        RECT 3274.45 1609.9 3275.85 1612.24 ;
    END
  END n_WTA_final_Vbias
  PIN n_WTA_final_Vmid
    DIRECTION INOUT ;
    USE SIGNAL ;
    PORT
      LAYER METAL3 ;
        RECT 3260.45 1609.9 3261.85 1612.24 ;
    END
  END n_WTA_final_Vmid
  PIN n_WTA_final_scan_Qout
    DIRECTION INOUT ;
    USE SIGNAL ;
    PORT
      LAYER METAL3 ;
        RECT 3246.45 1609.9 3247.85 1612.24 ;
    END
  END n_WTA_final_scan_Qout
  PIN n_WTA_final_scan_RSTB
    DIRECTION INOUT ;
    USE SIGNAL ;
    PORT
      LAYER METAL3 ;
        RECT 3232.45 1609.9 3233.85 1612.24 ;
    END
  END n_WTA_final_scan_RSTB
  PIN n_WTA_final_scan_CLK
    DIRECTION INOUT ;
    USE SIGNAL ;
    PORT
      LAYER METAL3 ;
        RECT 3218.45 1609.9 3219.85 1612.24 ;
    END
  END n_WTA_final_scan_CLK
  PIN n_WTA_final_scan_Din
    DIRECTION INOUT ;
    USE SIGNAL ;
    PORT
      LAYER METAL3 ;
        RECT 3204.45 1609.9 3205.85 1612.24 ;
    END
  END n_WTA_final_scan_Din
  PIN n_WTA_final_scan_out
    DIRECTION INOUT ;
    USE SIGNAL ;
    PORT
      LAYER METAL3 ;
        RECT 3190.45 1609.9 3191.85 1612.24 ;
    END
  END n_WTA_final_scan_out
  PIN n_FNN_final_Dr_En
    DIRECTION INOUT ;
    USE SIGNAL ;
    PORT
      LAYER METAL3 ;
        RECT 3176.45 1609.9 3177.85 1612.24 ;
    END
  END n_FNN_final_Dr_En
  PIN n_FNN_final_G_En
    DIRECTION INOUT ;
    USE SIGNAL ;
    PORT
      LAYER METAL3 ;
        RECT 3162.45 1609.9 3163.85 1612.24 ;
    END
  END n_FNN_final_G_En
  PIN n_Act_ly1_scan_Qout
    DIRECTION INOUT ;
    USE SIGNAL ;
    PORT
      LAYER METAL3 ;
        RECT 3148.45 1609.9 3149.85 1612.24 ;
    END
  END n_Act_ly1_scan_Qout
  PIN n_Act_ly1_scan_RSTB
    DIRECTION INOUT ;
    USE SIGNAL ;
    PORT
      LAYER METAL3 ;
        RECT 3134.45 1609.9 3135.85 1612.24 ;
    END
  END n_Act_ly1_scan_RSTB
  PIN n_Act_ly1_scan_CLK
    DIRECTION INOUT ;
    USE SIGNAL ;
    PORT
      LAYER METAL3 ;
        RECT 3120.45 1609.9 3121.85 1612.24 ;
    END
  END n_Act_ly1_scan_CLK
  PIN n_Act_ly1_scan_Din
    DIRECTION INOUT ;
    USE SIGNAL ;
    PORT
      LAYER METAL3 ;
        RECT 3106.45 1609.9 3107.85 1612.24 ;
    END
  END n_Act_ly1_scan_Din
  PIN n_Act_ly1_scan_out
    DIRECTION INOUT ;
    USE SIGNAL ;
    PORT
      LAYER METAL3 ;
        RECT 3092.45 1609.9 3093.85 1612.24 ;
    END
  END n_Act_ly1_scan_out
  PIN n_FNN_ly1_ActF_G_En
    DIRECTION INOUT ;
    USE SIGNAL ;
    PORT
      LAYER METAL3 ;
        RECT 3078.45 1609.9 3079.85 1612.24 ;
    END
  END n_FNN_ly1_ActF_G_En
  PIN n_FNN_ly1_Dr_En
    DIRECTION INOUT ;
    USE SIGNAL ;
    PORT
      LAYER METAL3 ;
        RECT 3064.45 1609.9 3065.85 1612.24 ;
    END
  END n_FNN_ly1_Dr_En
  PIN n_FNN_ly1_G_En
    DIRECTION INOUT ;
    USE SIGNAL ;
    PORT
      LAYER METAL3 ;
        RECT 3050.45 1609.9 3051.85 1612.24 ;
    END
  END n_FNN_ly1_G_En
  PIN n_Act_ly0_scan_Qout
    DIRECTION INOUT ;
    USE SIGNAL ;
    PORT
      LAYER METAL3 ;
        RECT 3036.45 1609.9 3037.85 1612.24 ;
    END
  END n_Act_ly0_scan_Qout
  PIN n_Act_ly0_scan_RSTB
    DIRECTION INOUT ;
    USE SIGNAL ;
    PORT
      LAYER METAL3 ;
        RECT 3022.45 1609.9 3023.85 1612.24 ;
    END
  END n_Act_ly0_scan_RSTB
  PIN n_Act_ly0_scan_CLK
    DIRECTION INOUT ;
    USE SIGNAL ;
    PORT
      LAYER METAL3 ;
        RECT 3008.45 1609.9 3009.85 1612.24 ;
    END
  END n_Act_ly0_scan_CLK
  PIN n_Act_ly0_scan_Din
    DIRECTION INOUT ;
    USE SIGNAL ;
    PORT
      LAYER METAL3 ;
        RECT 2994.45 1609.9 2995.85 1612.24 ;
    END
  END n_Act_ly0_scan_Din
  PIN n_Act_ly0_scan_out
    DIRECTION INOUT ;
    USE SIGNAL ;
    PORT
      LAYER METAL3 ;
        RECT 2980.45 1609.9 2981.85 1612.24 ;
    END
  END n_Act_ly0_scan_out
  PIN n_FNN_ly0_ActF_G_En
    DIRECTION INOUT ;
    USE SIGNAL ;
    PORT
      LAYER METAL3 ;
        RECT 2966.45 1609.9 2967.85 1612.24 ;
    END
  END n_FNN_ly0_ActF_G_En
  PIN n_FNN_input<176>
    DIRECTION INOUT ;
    USE SIGNAL ;
    PORT
      LAYER METAL3 ;
        RECT 2924.45 1609.9 2925.85 1612.24 ;
    END
  END n_FNN_input<176>
  PIN n_FNN_input<174>
    DIRECTION INOUT ;
    USE SIGNAL ;
    PORT
      LAYER METAL3 ;
        RECT 2910.45 1609.9 2911.85 1612.24 ;
    END
  END n_FNN_input<174>
  PIN n_FNN_input<173>
    DIRECTION INOUT ;
    USE SIGNAL ;
    PORT
      LAYER METAL3 ;
        RECT 2896.45 1609.9 2897.85 1612.24 ;
    END
  END n_FNN_input<173>
  PIN n_FNN_input<172>
    DIRECTION INOUT ;
    USE SIGNAL ;
    PORT
      LAYER METAL3 ;
        RECT 2882.45 1609.9 2883.85 1612.24 ;
    END
  END n_FNN_input<172>
  PIN n_FNN_input<171>
    DIRECTION INOUT ;
    USE SIGNAL ;
    PORT
      LAYER METAL3 ;
        RECT 2868.45 1609.9 2869.85 1612.24 ;
    END
  END n_FNN_input<171>
  PIN n_FNN_input<170>
    DIRECTION INOUT ;
    USE SIGNAL ;
    PORT
      LAYER METAL3 ;
        RECT 2854.45 1609.9 2855.85 1612.24 ;
    END
  END n_FNN_input<170>
  PIN n_FNN_input<169>
    DIRECTION INOUT ;
    USE SIGNAL ;
    PORT
      LAYER METAL3 ;
        RECT 2840.45 1609.9 2841.85 1612.24 ;
    END
  END n_FNN_input<169>
  PIN n_FNN_input<168>
    DIRECTION INOUT ;
    USE SIGNAL ;
    PORT
      LAYER METAL3 ;
        RECT 2826.45 1609.9 2827.85 1612.24 ;
    END
  END n_FNN_input<168>
  PIN n_FNN_input<167>
    DIRECTION INOUT ;
    USE SIGNAL ;
    PORT
      LAYER METAL3 ;
        RECT 2812.45 1609.9 2813.85 1612.24 ;
    END
  END n_FNN_input<167>
  PIN n_FNN_input<166>
    DIRECTION INOUT ;
    USE SIGNAL ;
    PORT
      LAYER METAL3 ;
        RECT 2798.45 1609.9 2799.85 1612.24 ;
    END
  END n_FNN_input<166>
  PIN n_FNN_input<165>
    DIRECTION INOUT ;
    USE SIGNAL ;
    PORT
      LAYER METAL3 ;
        RECT 2784.45 1609.9 2785.85 1612.24 ;
    END
  END n_FNN_input<165>
  PIN n_FNN_input<164>
    DIRECTION INOUT ;
    USE SIGNAL ;
    PORT
      LAYER METAL3 ;
        RECT 2770.45 1609.9 2771.85 1612.24 ;
    END
  END n_FNN_input<164>
  PIN n_FNN_input<163>
    DIRECTION INOUT ;
    USE SIGNAL ;
    PORT
      LAYER METAL3 ;
        RECT 2756.45 1609.9 2757.85 1612.24 ;
    END
  END n_FNN_input<163>
  PIN n_FNN_input<162>
    DIRECTION INOUT ;
    USE SIGNAL ;
    PORT
      LAYER METAL3 ;
        RECT 2742.45 1609.9 2743.85 1612.24 ;
    END
  END n_FNN_input<162>
  PIN n_FNN_input<161>
    DIRECTION INOUT ;
    USE SIGNAL ;
    PORT
      LAYER METAL3 ;
        RECT 2728.45 1609.9 2729.85 1612.24 ;
    END
  END n_FNN_input<161>
  PIN n_FNN_input<160>
    DIRECTION INOUT ;
    USE SIGNAL ;
    PORT
      LAYER METAL3 ;
        RECT 2714.45 1609.9 2715.85 1612.24 ;
    END
  END n_FNN_input<160>
  PIN n_FNN_input<159>
    DIRECTION INOUT ;
    USE SIGNAL ;
    PORT
      LAYER METAL3 ;
        RECT 2700.45 1609.9 2701.85 1612.24 ;
    END
  END n_FNN_input<159>
  PIN n_FNN_Vsel_dbg
    DIRECTION INOUT ;
    USE SIGNAL ;
    PORT
      LAYER METAL3 ;
        RECT 3302.45 1609.9 3303.85 1612.24 ;
    END
  END n_FNN_Vsel_dbg
  PIN n_FNN_ly0_out_95
    DIRECTION INOUT ;
    USE SIGNAL ;
    PORT
      LAYER METAL3 ;
        RECT 3288.45 1609.9 3289.85 1612.24 ;
    END
  END n_FNN_ly0_out_95
  PIN n_FNN_input<157>
    DIRECTION INOUT ;
    USE SIGNAL ;
    PORT
      LAYER METAL3 ;
        RECT 2672.45 1609.9 2673.85 1612.24 ;
    END
  END n_FNN_input<157>
  PIN n_FNN_input<156>
    DIRECTION INOUT ;
    USE SIGNAL ;
    PORT
      LAYER METAL3 ;
        RECT 2658.45 1609.9 2659.85 1612.24 ;
    END
  END n_FNN_input<156>
  PIN n_FNN_input<155>
    DIRECTION INOUT ;
    USE SIGNAL ;
    PORT
      LAYER METAL3 ;
        RECT 2644.45 1609.9 2645.85 1612.24 ;
    END
  END n_FNN_input<155>
  PIN n_FNN_input<154>
    DIRECTION INOUT ;
    USE SIGNAL ;
    PORT
      LAYER METAL3 ;
        RECT 2630.45 1609.9 2631.85 1612.24 ;
    END
  END n_FNN_input<154>
  PIN n_FNN_input<153>
    DIRECTION INOUT ;
    USE SIGNAL ;
    PORT
      LAYER METAL3 ;
        RECT 2616.45 1609.9 2617.85 1612.24 ;
    END
  END n_FNN_input<153>
  PIN n_FNN_input<152>
    DIRECTION INOUT ;
    USE SIGNAL ;
    PORT
      LAYER METAL3 ;
        RECT 2602.45 1609.9 2603.85 1612.24 ;
    END
  END n_FNN_input<152>
  PIN n_FNN_input<151>
    DIRECTION INOUT ;
    USE SIGNAL ;
    PORT
      LAYER METAL3 ;
        RECT 2588.45 1609.9 2589.85 1612.24 ;
    END
  END n_FNN_input<151>
  PIN n_FNN_input<150>
    DIRECTION INOUT ;
    USE SIGNAL ;
    PORT
      LAYER METAL3 ;
        RECT 2574.45 1609.9 2575.85 1612.24 ;
    END
  END n_FNN_input<150>
  PIN n_FNN_input<149>
    DIRECTION INOUT ;
    USE SIGNAL ;
    PORT
      LAYER METAL3 ;
        RECT 2560.45 1609.9 2561.85 1612.24 ;
    END
  END n_FNN_input<149>
  PIN n_FNN_input<148>
    DIRECTION INOUT ;
    USE SIGNAL ;
    PORT
      LAYER METAL3 ;
        RECT 2546.45 1609.9 2547.85 1612.24 ;
    END
  END n_FNN_input<148>
  PIN n_FNN_input<147>
    DIRECTION INOUT ;
    USE SIGNAL ;
    PORT
      LAYER METAL3 ;
        RECT 2532.45 1609.9 2533.85 1612.24 ;
    END
  END n_FNN_input<147>
  PIN n_FNN_input<146>
    DIRECTION INOUT ;
    USE SIGNAL ;
    PORT
      LAYER METAL3 ;
        RECT 2518.45 1609.9 2519.85 1612.24 ;
    END
  END n_FNN_input<146>
  PIN n_FNN_input<145>
    DIRECTION INOUT ;
    USE SIGNAL ;
    PORT
      LAYER METAL3 ;
        RECT 2504.45 1609.9 2505.85 1612.24 ;
    END
  END n_FNN_input<145>
  PIN n_FNN_input<144>
    DIRECTION INOUT ;
    USE SIGNAL ;
    PORT
      LAYER METAL3 ;
        RECT 2490.45 1609.9 2491.85 1612.24 ;
    END
  END n_FNN_input<144>
  PIN n_FNN_input<143>
    DIRECTION INOUT ;
    USE SIGNAL ;
    PORT
      LAYER METAL3 ;
        RECT 2476.45 1609.9 2477.85 1612.24 ;
    END
  END n_FNN_input<143>
  PIN n_FNN_input<142>
    DIRECTION INOUT ;
    USE SIGNAL ;
    PORT
      LAYER METAL3 ;
        RECT 2462.45 1609.9 2463.85 1612.24 ;
    END
  END n_FNN_input<142>
  PIN n_FNN_input<141>
    DIRECTION INOUT ;
    USE SIGNAL ;
    PORT
      LAYER METAL3 ;
        RECT 2448.45 1609.9 2449.85 1612.24 ;
    END
  END n_FNN_input<141>
  PIN n_FNN_input<140>
    DIRECTION INOUT ;
    USE SIGNAL ;
    PORT
      LAYER METAL3 ;
        RECT 2434.45 1609.9 2435.85 1612.24 ;
    END
  END n_FNN_input<140>
  PIN n_FNN_input<139>
    DIRECTION INOUT ;
    USE SIGNAL ;
    PORT
      LAYER METAL3 ;
        RECT 2420.45 1609.9 2421.85 1612.24 ;
    END
  END n_FNN_input<139>
  PIN n_FNN_input<138>
    DIRECTION INOUT ;
    USE SIGNAL ;
    PORT
      LAYER METAL3 ;
        RECT 2406.45 1609.9 2407.85 1612.24 ;
    END
  END n_FNN_input<138>
  PIN n_FNN_input<137>
    DIRECTION INOUT ;
    USE SIGNAL ;
    PORT
      LAYER METAL3 ;
        RECT 2392.45 1609.9 2393.85 1612.24 ;
    END
  END n_FNN_input<137>
  PIN n_FNN_input<136>
    DIRECTION INOUT ;
    USE SIGNAL ;
    PORT
      LAYER METAL3 ;
        RECT 2378.45 1609.9 2379.85 1612.24 ;
    END
  END n_FNN_input<136>
  PIN n_FNN_input<135>
    DIRECTION INOUT ;
    USE SIGNAL ;
    PORT
      LAYER METAL3 ;
        RECT 2364.45 1609.9 2365.85 1612.24 ;
    END
  END n_FNN_input<135>
  PIN n_FNN_input<134>
    DIRECTION INOUT ;
    USE SIGNAL ;
    PORT
      LAYER METAL3 ;
        RECT 2350.45 1609.9 2351.85 1612.24 ;
    END
  END n_FNN_input<134>
  PIN n_FNN_input<133>
    DIRECTION INOUT ;
    USE SIGNAL ;
    PORT
      LAYER METAL3 ;
        RECT 2336.45 1609.9 2337.85 1612.24 ;
    END
  END n_FNN_input<133>
  PIN n_FNN_input<132>
    DIRECTION INOUT ;
    USE SIGNAL ;
    PORT
      LAYER METAL3 ;
        RECT 2322.45 1609.9 2323.85 1612.24 ;
    END
  END n_FNN_input<132>
  PIN n_FNN_input<131>
    DIRECTION INOUT ;
    USE SIGNAL ;
    PORT
      LAYER METAL3 ;
        RECT 2308.45 1609.9 2309.85 1612.24 ;
    END
  END n_FNN_input<131>
  PIN n_FNN_input<130>
    DIRECTION INOUT ;
    USE SIGNAL ;
    PORT
      LAYER METAL3 ;
        RECT 2294.45 1609.9 2295.85 1612.24 ;
    END
  END n_FNN_input<130>
  PIN n_FNN_input<129>
    DIRECTION INOUT ;
    USE SIGNAL ;
    PORT
      LAYER METAL3 ;
        RECT 2280.45 1609.9 2281.85 1612.24 ;
    END
  END n_FNN_input<129>
  PIN n_FNN_input<128>
    DIRECTION INOUT ;
    USE SIGNAL ;
    PORT
      LAYER METAL3 ;
        RECT 2266.45 1609.9 2267.85 1612.24 ;
    END
  END n_FNN_input<128>
  PIN n_FNN_input<127>
    DIRECTION INOUT ;
    USE SIGNAL ;
    PORT
      LAYER METAL3 ;
        RECT 2252.45 1609.9 2253.85 1612.24 ;
    END
  END n_FNN_input<127>
  PIN n_FNN_input<126>
    DIRECTION INOUT ;
    USE SIGNAL ;
    PORT
      LAYER METAL3 ;
        RECT 2238.45 1609.9 2239.85 1612.24 ;
    END
  END n_FNN_input<126>
  PIN n_FNN_input<125>
    DIRECTION INOUT ;
    USE SIGNAL ;
    PORT
      LAYER METAL3 ;
        RECT 2224.45 1609.9 2225.85 1612.24 ;
    END
  END n_FNN_input<125>
  PIN n_FNN_input<124>
    DIRECTION INOUT ;
    USE SIGNAL ;
    PORT
      LAYER METAL3 ;
        RECT 2210.45 1609.9 2211.85 1612.24 ;
    END
  END n_FNN_input<124>
  PIN n_FNN_input<123>
    DIRECTION INOUT ;
    USE SIGNAL ;
    PORT
      LAYER METAL3 ;
        RECT 2196.45 1609.9 2197.85 1612.24 ;
    END
  END n_FNN_input<123>
  PIN n_FNN_input<122>
    DIRECTION INOUT ;
    USE SIGNAL ;
    PORT
      LAYER METAL3 ;
        RECT 2182.45 1609.9 2183.85 1612.24 ;
    END
  END n_FNN_input<122>
  PIN n_FNN_input<121>
    DIRECTION INOUT ;
    USE SIGNAL ;
    PORT
      LAYER METAL3 ;
        RECT 2168.45 1609.9 2169.85 1612.24 ;
    END
  END n_FNN_input<121>
  PIN n_FNN_input<120>
    DIRECTION INOUT ;
    USE SIGNAL ;
    PORT
      LAYER METAL3 ;
        RECT 2154.45 1609.9 2155.85 1612.24 ;
    END
  END n_FNN_input<120>
  PIN n_FNN_input<119>
    DIRECTION INOUT ;
    USE SIGNAL ;
    PORT
      LAYER METAL3 ;
        RECT 2140.45 1609.9 2141.85 1612.24 ;
    END
  END n_FNN_input<119>
  PIN n_FNN_input<118>
    DIRECTION INOUT ;
    USE SIGNAL ;
    PORT
      LAYER METAL3 ;
        RECT 2126.45 1609.9 2127.85 1612.24 ;
    END
  END n_FNN_input<118>
  PIN n_FNN_input<117>
    DIRECTION INOUT ;
    USE SIGNAL ;
    PORT
      LAYER METAL3 ;
        RECT 2112.45 1609.9 2113.85 1612.24 ;
    END
  END n_FNN_input<117>
  PIN n_FNN_input<116>
    DIRECTION INOUT ;
    USE SIGNAL ;
    PORT
      LAYER METAL3 ;
        RECT 2098.45 1609.9 2099.85 1612.24 ;
    END
  END n_FNN_input<116>
  PIN n_FNN_input<115>
    DIRECTION INOUT ;
    USE SIGNAL ;
    PORT
      LAYER METAL3 ;
        RECT 2084.45 1609.9 2085.85 1612.24 ;
    END
  END n_FNN_input<115>
  PIN n_FNN_input<114>
    DIRECTION INOUT ;
    USE SIGNAL ;
    PORT
      LAYER METAL3 ;
        RECT 2070.45 1609.9 2071.85 1612.24 ;
    END
  END n_FNN_input<114>
  PIN n_FNN_input<113>
    DIRECTION INOUT ;
    USE SIGNAL ;
    PORT
      LAYER METAL3 ;
        RECT 2056.45 1609.9 2057.85 1612.24 ;
    END
  END n_FNN_input<113>
  PIN n_FNN_input<112>
    DIRECTION INOUT ;
    USE SIGNAL ;
    PORT
      LAYER METAL3 ;
        RECT 2042.45 1609.9 2043.85 1612.24 ;
    END
  END n_FNN_input<112>
  PIN n_FNN_input<111>
    DIRECTION INOUT ;
    USE SIGNAL ;
    PORT
      LAYER METAL3 ;
        RECT 2028.45 1609.9 2029.85 1612.24 ;
    END
  END n_FNN_input<111>
  PIN n_FNN_input<110>
    DIRECTION INOUT ;
    USE SIGNAL ;
    PORT
      LAYER METAL3 ;
        RECT 2014.45 1609.9 2015.85 1612.24 ;
    END
  END n_FNN_input<110>
  PIN n_FNN_input<109>
    DIRECTION INOUT ;
    USE SIGNAL ;
    PORT
      LAYER METAL3 ;
        RECT 2000.45 1609.9 2001.85 1612.24 ;
    END
  END n_FNN_input<109>
  PIN n_FNN_input<108>
    DIRECTION INOUT ;
    USE SIGNAL ;
    PORT
      LAYER METAL3 ;
        RECT 1986.45 1609.9 1987.85 1612.24 ;
    END
  END n_FNN_input<108>
  PIN n_FNN_input<107>
    DIRECTION INOUT ;
    USE SIGNAL ;
    PORT
      LAYER METAL3 ;
        RECT 1972.45 1609.9 1973.85 1612.24 ;
    END
  END n_FNN_input<107>
  PIN n_FNN_input<106>
    DIRECTION INOUT ;
    USE SIGNAL ;
    PORT
      LAYER METAL3 ;
        RECT 1958.45 1609.9 1959.85 1612.24 ;
    END
  END n_FNN_input<106>
  PIN n_FNN_input<105>
    DIRECTION INOUT ;
    USE SIGNAL ;
    PORT
      LAYER METAL3 ;
        RECT 1944.45 1609.9 1945.85 1612.24 ;
    END
  END n_FNN_input<105>
  PIN n_FNN_input<104>
    DIRECTION INOUT ;
    USE SIGNAL ;
    PORT
      LAYER METAL3 ;
        RECT 1930.45 1609.9 1931.85 1612.24 ;
    END
  END n_FNN_input<104>
  PIN n_FNN_input<103>
    DIRECTION INOUT ;
    USE SIGNAL ;
    PORT
      LAYER METAL3 ;
        RECT 1916.45 1609.9 1917.85 1612.24 ;
    END
  END n_FNN_input<103>
  PIN n_FNN_input<102>
    DIRECTION INOUT ;
    USE SIGNAL ;
    PORT
      LAYER METAL3 ;
        RECT 1902.45 1609.9 1903.85 1612.24 ;
    END
  END n_FNN_input<102>
  PIN n_FNN_input<101>
    DIRECTION INOUT ;
    USE SIGNAL ;
    PORT
      LAYER METAL3 ;
        RECT 1888.45 1609.9 1889.85 1612.24 ;
    END
  END n_FNN_input<101>
  PIN n_FNN_input<100>
    DIRECTION INOUT ;
    USE SIGNAL ;
    PORT
      LAYER METAL3 ;
        RECT 1874.45 1609.9 1875.85 1612.24 ;
    END
  END n_FNN_input<100>
  PIN n_FNN_input<99>
    DIRECTION INOUT ;
    USE SIGNAL ;
    PORT
      LAYER METAL3 ;
        RECT 1860.45 1609.9 1861.85 1612.24 ;
    END
  END n_FNN_input<99>
  PIN n_FNN_input<98>
    DIRECTION INOUT ;
    USE SIGNAL ;
    PORT
      LAYER METAL3 ;
        RECT 1846.45 1609.9 1847.85 1612.24 ;
    END
  END n_FNN_input<98>
  PIN n_FNN_input<97>
    DIRECTION INOUT ;
    USE SIGNAL ;
    PORT
      LAYER METAL3 ;
        RECT 1832.45 1609.9 1833.85 1612.24 ;
    END
  END n_FNN_input<97>
  PIN n_FNN_input<96>
    DIRECTION INOUT ;
    USE SIGNAL ;
    PORT
      LAYER METAL3 ;
        RECT 1818.45 1609.9 1819.85 1612.24 ;
    END
  END n_FNN_input<96>
  PIN n_FNN_input<95>
    DIRECTION INOUT ;
    USE SIGNAL ;
    PORT
      LAYER METAL3 ;
        RECT 1804.45 1609.9 1805.85 1612.24 ;
    END
  END n_FNN_input<95>
  PIN n_FNN_input<94>
    DIRECTION INOUT ;
    USE SIGNAL ;
    PORT
      LAYER METAL3 ;
        RECT 1790.45 1609.9 1791.85 1612.24 ;
    END
  END n_FNN_input<94>
  PIN n_FNN_input<93>
    DIRECTION INOUT ;
    USE SIGNAL ;
    PORT
      LAYER METAL3 ;
        RECT 1776.45 1609.9 1777.85 1612.24 ;
    END
  END n_FNN_input<93>
  PIN n_FNN_input<92>
    DIRECTION INOUT ;
    USE SIGNAL ;
    PORT
      LAYER METAL3 ;
        RECT 1762.45 1609.9 1763.85 1612.24 ;
    END
  END n_FNN_input<92>
  PIN n_FNN_input<91>
    DIRECTION INOUT ;
    USE SIGNAL ;
    PORT
      LAYER METAL3 ;
        RECT 1748.45 1609.9 1749.85 1612.24 ;
    END
  END n_FNN_input<91>
  PIN n_FNN_input<90>
    DIRECTION INOUT ;
    USE SIGNAL ;
    PORT
      LAYER METAL3 ;
        RECT 1734.45 1609.9 1735.85 1612.24 ;
    END
  END n_FNN_input<90>
  PIN n_FNN_input<89>
    DIRECTION INOUT ;
    USE SIGNAL ;
    PORT
      LAYER METAL3 ;
        RECT 1720.45 1609.9 1721.85 1612.24 ;
    END
  END n_FNN_input<89>
  PIN n_FNN_input<88>
    DIRECTION INOUT ;
    USE SIGNAL ;
    PORT
      LAYER METAL3 ;
        RECT 1706.45 1609.9 1707.85 1612.24 ;
    END
  END n_FNN_input<88>
  PIN n_FNN_input<87>
    DIRECTION INOUT ;
    USE SIGNAL ;
    PORT
      LAYER METAL3 ;
        RECT 1692.45 1609.9 1693.85 1612.24 ;
    END
  END n_FNN_input<87>
  PIN n_FNN_input<86>
    DIRECTION INOUT ;
    USE SIGNAL ;
    PORT
      LAYER METAL3 ;
        RECT 1678.45 1609.9 1679.85 1612.24 ;
    END
  END n_FNN_input<86>
  PIN n_FNN_input<85>
    DIRECTION INOUT ;
    USE SIGNAL ;
    PORT
      LAYER METAL3 ;
        RECT 1664.45 1609.9 1665.85 1612.24 ;
    END
  END n_FNN_input<85>
  PIN n_FNN_input<84>
    DIRECTION INOUT ;
    USE SIGNAL ;
    PORT
      LAYER METAL3 ;
        RECT 1650.45 1609.9 1651.85 1612.24 ;
    END
  END n_FNN_input<84>
  PIN n_FNN_input<83>
    DIRECTION INOUT ;
    USE SIGNAL ;
    PORT
      LAYER METAL3 ;
        RECT 1636.45 1609.9 1637.85 1612.24 ;
    END
  END n_FNN_input<83>
  PIN n_FNN_input<82>
    DIRECTION INOUT ;
    USE SIGNAL ;
    PORT
      LAYER METAL3 ;
        RECT 1622.45 1609.9 1623.85 1612.24 ;
    END
  END n_FNN_input<82>
  PIN n_FNN_input<81>
    DIRECTION INOUT ;
    USE SIGNAL ;
    PORT
      LAYER METAL3 ;
        RECT 1608.45 1609.9 1609.85 1612.24 ;
    END
  END n_FNN_input<81>
  PIN n_FNN_input<80>
    DIRECTION INOUT ;
    USE SIGNAL ;
    PORT
      LAYER METAL3 ;
        RECT 1594.45 1609.9 1595.85 1612.24 ;
    END
  END n_FNN_input<80>
  PIN n_FNN_input<79>
    DIRECTION INOUT ;
    USE SIGNAL ;
    PORT
      LAYER METAL3 ;
        RECT 1580.45 1609.9 1581.85 1612.24 ;
    END
  END n_FNN_input<79>
  PIN n_FNN_input<78>
    DIRECTION INOUT ;
    USE SIGNAL ;
    PORT
      LAYER METAL3 ;
        RECT 1566.45 1609.9 1567.85 1612.24 ;
    END
  END n_FNN_input<78>
  PIN n_FNN_input<77>
    DIRECTION INOUT ;
    USE SIGNAL ;
    PORT
      LAYER METAL3 ;
        RECT 1552.45 1609.9 1553.85 1612.24 ;
    END
  END n_FNN_input<77>
  PIN n_FNN_input<76>
    DIRECTION INOUT ;
    USE SIGNAL ;
    PORT
      LAYER METAL3 ;
        RECT 1538.45 1609.9 1539.85 1612.24 ;
    END
  END n_FNN_input<76>
  PIN n_FNN_input<75>
    DIRECTION INOUT ;
    USE SIGNAL ;
    PORT
      LAYER METAL3 ;
        RECT 1524.45 1609.9 1525.85 1612.24 ;
    END
  END n_FNN_input<75>
  PIN n_FNN_input<74>
    DIRECTION INOUT ;
    USE SIGNAL ;
    PORT
      LAYER METAL3 ;
        RECT 1510.45 1609.9 1511.85 1612.24 ;
    END
  END n_FNN_input<74>
  PIN n_FNN_input<73>
    DIRECTION INOUT ;
    USE SIGNAL ;
    PORT
      LAYER METAL3 ;
        RECT 1496.45 1609.9 1497.85 1612.24 ;
    END
  END n_FNN_input<73>
  PIN n_FNN_input<72>
    DIRECTION INOUT ;
    USE SIGNAL ;
    PORT
      LAYER METAL3 ;
        RECT 1482.45 1609.9 1483.85 1612.24 ;
    END
  END n_FNN_input<72>
  PIN n_FNN_input<71>
    DIRECTION INOUT ;
    USE SIGNAL ;
    PORT
      LAYER METAL3 ;
        RECT 1468.45 1609.9 1469.85 1612.24 ;
    END
  END n_FNN_input<71>
  PIN n_FNN_input<70>
    DIRECTION INOUT ;
    USE SIGNAL ;
    PORT
      LAYER METAL3 ;
        RECT 1454.45 1609.9 1455.85 1612.24 ;
    END
  END n_FNN_input<70>
  PIN n_FNN_input<69>
    DIRECTION INOUT ;
    USE SIGNAL ;
    PORT
      LAYER METAL3 ;
        RECT 1440.45 1609.9 1441.85 1612.24 ;
    END
  END n_FNN_input<69>
  PIN n_FNN_input<68>
    DIRECTION INOUT ;
    USE SIGNAL ;
    PORT
      LAYER METAL3 ;
        RECT 1426.45 1609.9 1427.85 1612.24 ;
    END
  END n_FNN_input<68>
  PIN n_FNN_input<67>
    DIRECTION INOUT ;
    USE SIGNAL ;
    PORT
      LAYER METAL3 ;
        RECT 1412.45 1609.9 1413.85 1612.24 ;
    END
  END n_FNN_input<67>
  PIN n_FNN_input<66>
    DIRECTION INOUT ;
    USE SIGNAL ;
    PORT
      LAYER METAL3 ;
        RECT 1398.45 1609.9 1399.85 1612.24 ;
    END
  END n_FNN_input<66>
  PIN n_FNN_input<65>
    DIRECTION INOUT ;
    USE SIGNAL ;
    PORT
      LAYER METAL3 ;
        RECT 1384.45 1609.9 1385.85 1612.24 ;
    END
  END n_FNN_input<65>
  PIN n_FNN_input<64>
    DIRECTION INOUT ;
    USE SIGNAL ;
    PORT
      LAYER METAL3 ;
        RECT 1370.45 1609.9 1371.85 1612.24 ;
    END
  END n_FNN_input<64>
  PIN n_FNN_input<158>
    DIRECTION INOUT ;
    USE SIGNAL ;
    PORT
      LAYER METAL3 ;
        RECT 2686.45 1609.9 2687.85 1612.24 ;
    END
  END n_FNN_input<158>
  PIN n_FNN_input<62>
    DIRECTION INOUT ;
    USE SIGNAL ;
    PORT
      LAYER METAL3 ;
        RECT 1342.45 1609.9 1343.85 1612.24 ;
    END
  END n_FNN_input<62>
  PIN n_FNN_input<61>
    DIRECTION INOUT ;
    USE SIGNAL ;
    PORT
      LAYER METAL3 ;
        RECT 1328.45 1609.9 1329.85 1612.24 ;
    END
  END n_FNN_input<61>
  PIN n_FNN_input<60>
    DIRECTION INOUT ;
    USE SIGNAL ;
    PORT
      LAYER METAL3 ;
        RECT 1314.45 1609.9 1315.85 1612.24 ;
    END
  END n_FNN_input<60>
  PIN n_FNN_input<59>
    DIRECTION INOUT ;
    USE SIGNAL ;
    PORT
      LAYER METAL3 ;
        RECT 1300.45 1609.9 1301.85 1612.24 ;
    END
  END n_FNN_input<59>
  PIN n_FNN_input<58>
    DIRECTION INOUT ;
    USE SIGNAL ;
    PORT
      LAYER METAL3 ;
        RECT 1286.45 1609.9 1287.85 1612.24 ;
    END
  END n_FNN_input<58>
  PIN n_FNN_input<57>
    DIRECTION INOUT ;
    USE SIGNAL ;
    PORT
      LAYER METAL3 ;
        RECT 1272.45 1609.9 1273.85 1612.24 ;
    END
  END n_FNN_input<57>
  PIN n_FNN_input<56>
    DIRECTION INOUT ;
    USE SIGNAL ;
    PORT
      LAYER METAL3 ;
        RECT 1258.45 1609.9 1259.85 1612.24 ;
    END
  END n_FNN_input<56>
  PIN n_FNN_input<55>
    DIRECTION INOUT ;
    USE SIGNAL ;
    PORT
      LAYER METAL3 ;
        RECT 1244.45 1609.9 1245.85 1612.24 ;
    END
  END n_FNN_input<55>
  PIN n_FNN_input<54>
    DIRECTION INOUT ;
    USE SIGNAL ;
    PORT
      LAYER METAL3 ;
        RECT 1230.45 1609.9 1231.85 1612.24 ;
    END
  END n_FNN_input<54>
  PIN n_FNN_input<53>
    DIRECTION INOUT ;
    USE SIGNAL ;
    PORT
      LAYER METAL3 ;
        RECT 1216.45 1609.9 1217.85 1612.24 ;
    END
  END n_FNN_input<53>
  PIN n_FNN_input<52>
    DIRECTION INOUT ;
    USE SIGNAL ;
    PORT
      LAYER METAL3 ;
        RECT 1202.45 1609.9 1203.85 1612.24 ;
    END
  END n_FNN_input<52>
  PIN n_FNN_input<51>
    DIRECTION INOUT ;
    USE SIGNAL ;
    PORT
      LAYER METAL3 ;
        RECT 1188.45 1609.9 1189.85 1612.24 ;
    END
  END n_FNN_input<51>
  PIN n_FNN_input<50>
    DIRECTION INOUT ;
    USE SIGNAL ;
    PORT
      LAYER METAL3 ;
        RECT 1174.45 1609.9 1175.85 1612.24 ;
    END
  END n_FNN_input<50>
  PIN n_FNN_input<49>
    DIRECTION INOUT ;
    USE SIGNAL ;
    PORT
      LAYER METAL3 ;
        RECT 1160.45 1609.9 1161.85 1612.24 ;
    END
  END n_FNN_input<49>
  PIN n_FNN_input<48>
    DIRECTION INOUT ;
    USE SIGNAL ;
    PORT
      LAYER METAL3 ;
        RECT 1146.45 1609.9 1147.85 1612.24 ;
    END
  END n_FNN_input<48>
  PIN n_FNN_input<47>
    DIRECTION INOUT ;
    USE SIGNAL ;
    PORT
      LAYER METAL3 ;
        RECT 1132.45 1609.9 1133.85 1612.24 ;
    END
  END n_FNN_input<47>
  PIN n_FNN_input<46>
    DIRECTION INOUT ;
    USE SIGNAL ;
    PORT
      LAYER METAL3 ;
        RECT 1118.45 1609.9 1119.85 1612.24 ;
    END
  END n_FNN_input<46>
  PIN n_FNN_input<45>
    DIRECTION INOUT ;
    USE SIGNAL ;
    PORT
      LAYER METAL3 ;
        RECT 1104.45 1609.9 1105.85 1612.24 ;
    END
  END n_FNN_input<45>
  PIN n_FNN_input<44>
    DIRECTION INOUT ;
    USE SIGNAL ;
    PORT
      LAYER METAL3 ;
        RECT 1090.45 1609.9 1091.85 1612.24 ;
    END
  END n_FNN_input<44>
  PIN n_FNN_input<43>
    DIRECTION INOUT ;
    USE SIGNAL ;
    PORT
      LAYER METAL3 ;
        RECT 1076.45 1609.9 1077.85 1612.24 ;
    END
  END n_FNN_input<43>
  PIN n_FNN_input<42>
    DIRECTION INOUT ;
    USE SIGNAL ;
    PORT
      LAYER METAL3 ;
        RECT 1062.45 1609.9 1063.85 1612.24 ;
    END
  END n_FNN_input<42>
  PIN n_FNN_input<41>
    DIRECTION INOUT ;
    USE SIGNAL ;
    PORT
      LAYER METAL3 ;
        RECT 1048.45 1609.9 1049.85 1612.24 ;
    END
  END n_FNN_input<41>
  PIN n_FNN_input<40>
    DIRECTION INOUT ;
    USE SIGNAL ;
    PORT
      LAYER METAL3 ;
        RECT 1034.45 1609.9 1035.85 1612.24 ;
    END
  END n_FNN_input<40>
  PIN n_FNN_input<39>
    DIRECTION INOUT ;
    USE SIGNAL ;
    PORT
      LAYER METAL3 ;
        RECT 1020.45 1609.9 1021.85 1612.24 ;
    END
  END n_FNN_input<39>
  PIN n_FNN_input<38>
    DIRECTION INOUT ;
    USE SIGNAL ;
    PORT
      LAYER METAL3 ;
        RECT 1006.45 1609.9 1007.85 1612.24 ;
    END
  END n_FNN_input<38>
  PIN n_FNN_input<37>
    DIRECTION INOUT ;
    USE SIGNAL ;
    PORT
      LAYER METAL3 ;
        RECT 992.45 1609.9 993.85 1612.24 ;
    END
  END n_FNN_input<37>
  PIN n_FNN_input<36>
    DIRECTION INOUT ;
    USE SIGNAL ;
    PORT
      LAYER METAL3 ;
        RECT 978.45 1609.9 979.85 1612.24 ;
    END
  END n_FNN_input<36>
  PIN n_FNN_input<35>
    DIRECTION INOUT ;
    USE SIGNAL ;
    PORT
      LAYER METAL3 ;
        RECT 964.45 1609.9 965.85 1612.24 ;
    END
  END n_FNN_input<35>
  PIN n_FNN_input<34>
    DIRECTION INOUT ;
    USE SIGNAL ;
    PORT
      LAYER METAL3 ;
        RECT 950.45 1609.9 951.85 1612.24 ;
    END
  END n_FNN_input<34>
  PIN n_FNN_input<33>
    DIRECTION INOUT ;
    USE SIGNAL ;
    PORT
      LAYER METAL3 ;
        RECT 936.45 1609.9 937.85 1612.24 ;
    END
  END n_FNN_input<33>
  PIN n_FNN_input<32>
    DIRECTION INOUT ;
    USE SIGNAL ;
    PORT
      LAYER METAL3 ;
        RECT 922.45 1609.9 923.85 1612.24 ;
    END
  END n_FNN_input<32>
  PIN n_FNN_input<31>
    DIRECTION INOUT ;
    USE SIGNAL ;
    PORT
      LAYER METAL3 ;
        RECT 908.45 1609.9 909.85 1612.24 ;
    END
  END n_FNN_input<31>
  PIN n_FNN_input<30>
    DIRECTION INOUT ;
    USE SIGNAL ;
    PORT
      LAYER METAL3 ;
        RECT 894.45 1609.9 895.85 1612.24 ;
    END
  END n_FNN_input<30>
  PIN n_FNN_input<29>
    DIRECTION INOUT ;
    USE SIGNAL ;
    PORT
      LAYER METAL3 ;
        RECT 880.45 1609.9 881.85 1612.24 ;
    END
  END n_FNN_input<29>
  PIN n_FNN_input<28>
    DIRECTION INOUT ;
    USE SIGNAL ;
    PORT
      LAYER METAL3 ;
        RECT 866.45 1609.9 867.85 1612.24 ;
    END
  END n_FNN_input<28>
  PIN n_FNN_input<27>
    DIRECTION INOUT ;
    USE SIGNAL ;
    PORT
      LAYER METAL3 ;
        RECT 852.45 1609.9 853.85 1612.24 ;
    END
  END n_FNN_input<27>
  PIN n_FNN_input<26>
    DIRECTION INOUT ;
    USE SIGNAL ;
    PORT
      LAYER METAL3 ;
        RECT 838.45 1609.9 839.85 1612.24 ;
    END
  END n_FNN_input<26>
  PIN n_FNN_input<25>
    DIRECTION INOUT ;
    USE SIGNAL ;
    PORT
      LAYER METAL3 ;
        RECT 824.45 1609.9 825.85 1612.24 ;
    END
  END n_FNN_input<25>
  PIN n_FNN_input<24>
    DIRECTION INOUT ;
    USE SIGNAL ;
    PORT
      LAYER METAL3 ;
        RECT 810.45 1609.9 811.85 1612.24 ;
    END
  END n_FNN_input<24>
  PIN n_FNN_input<23>
    DIRECTION INOUT ;
    USE SIGNAL ;
    PORT
      LAYER METAL3 ;
        RECT 796.45 1609.9 797.85 1612.24 ;
    END
  END n_FNN_input<23>
  PIN n_FNN_input<22>
    DIRECTION INOUT ;
    USE SIGNAL ;
    PORT
      LAYER METAL3 ;
        RECT 782.45 1609.9 783.85 1612.24 ;
    END
  END n_FNN_input<22>
  PIN n_FNN_input<21>
    DIRECTION INOUT ;
    USE SIGNAL ;
    PORT
      LAYER METAL3 ;
        RECT 768.45 1609.9 769.85 1612.24 ;
    END
  END n_FNN_input<21>
  PIN n_FNN_input<20>
    DIRECTION INOUT ;
    USE SIGNAL ;
    PORT
      LAYER METAL3 ;
        RECT 754.45 1609.9 755.85 1612.24 ;
    END
  END n_FNN_input<20>
  PIN n_FNN_input<19>
    DIRECTION INOUT ;
    USE SIGNAL ;
    PORT
      LAYER METAL3 ;
        RECT 740.45 1609.9 741.85 1612.24 ;
    END
  END n_FNN_input<19>
  PIN n_FNN_input<18>
    DIRECTION INOUT ;
    USE SIGNAL ;
    PORT
      LAYER METAL3 ;
        RECT 726.45 1609.9 727.85 1612.24 ;
    END
  END n_FNN_input<18>
  PIN n_FNN_input<17>
    DIRECTION INOUT ;
    USE SIGNAL ;
    PORT
      LAYER METAL3 ;
        RECT 712.45 1609.9 713.85 1612.24 ;
    END
  END n_FNN_input<17>
  PIN n_FNN_input<16>
    DIRECTION INOUT ;
    USE SIGNAL ;
    PORT
      LAYER METAL3 ;
        RECT 698.45 1609.9 699.85 1612.24 ;
    END
  END n_FNN_input<16>
  PIN n_FNN_input<15>
    DIRECTION INOUT ;
    USE SIGNAL ;
    PORT
      LAYER METAL3 ;
        RECT 684.45 1609.9 685.85 1612.24 ;
    END
  END n_FNN_input<15>
  PIN n_FNN_input<14>
    DIRECTION INOUT ;
    USE SIGNAL ;
    PORT
      LAYER METAL3 ;
        RECT 670.45 1609.9 671.85 1612.24 ;
    END
  END n_FNN_input<14>
  PIN n_FNN_input<13>
    DIRECTION INOUT ;
    USE SIGNAL ;
    PORT
      LAYER METAL3 ;
        RECT 656.45 1609.9 657.85 1612.24 ;
    END
  END n_FNN_input<13>
  PIN n_FNN_input<12>
    DIRECTION INOUT ;
    USE SIGNAL ;
    PORT
      LAYER METAL3 ;
        RECT 642.45 1609.9 643.85 1612.24 ;
    END
  END n_FNN_input<12>
  PIN n_FNN_input<11>
    DIRECTION INOUT ;
    USE SIGNAL ;
    PORT
      LAYER METAL3 ;
        RECT 628.45 1609.9 629.85 1612.24 ;
    END
  END n_FNN_input<11>
  PIN n_FNN_input<10>
    DIRECTION INOUT ;
    USE SIGNAL ;
    PORT
      LAYER METAL3 ;
        RECT 614.45 1609.9 615.85 1612.24 ;
    END
  END n_FNN_input<10>
  PIN n_FNN_input<9>
    DIRECTION INOUT ;
    USE SIGNAL ;
    PORT
      LAYER METAL3 ;
        RECT 600.45 1609.9 601.85 1612.24 ;
    END
  END n_FNN_input<9>
  PIN n_FNN_input<8>
    DIRECTION INOUT ;
    USE SIGNAL ;
    PORT
      LAYER METAL3 ;
        RECT 586.45 1609.9 587.85 1612.24 ;
    END
  END n_FNN_input<8>
  PIN n_FNN_input<7>
    DIRECTION INOUT ;
    USE SIGNAL ;
    PORT
      LAYER METAL3 ;
        RECT 572.45 1609.9 573.85 1612.24 ;
    END
  END n_FNN_input<7>
  PIN n_FNN_input<6>
    DIRECTION INOUT ;
    USE SIGNAL ;
    PORT
      LAYER METAL3 ;
        RECT 558.45 1609.9 559.85 1612.24 ;
    END
  END n_FNN_input<6>
  PIN n_FNN_input<5>
    DIRECTION INOUT ;
    USE SIGNAL ;
    PORT
      LAYER METAL3 ;
        RECT 544.45 1609.9 545.85 1612.24 ;
    END
  END n_FNN_input<5>
  PIN n_FNN_input<4>
    DIRECTION INOUT ;
    USE SIGNAL ;
    PORT
      LAYER METAL3 ;
        RECT 530.45 1609.9 531.85 1612.24 ;
    END
  END n_FNN_input<4>
  PIN n_FNN_input<3>
    DIRECTION INOUT ;
    USE SIGNAL ;
    PORT
      LAYER METAL3 ;
        RECT 516.45 1609.9 517.85 1612.24 ;
    END
  END n_FNN_input<3>
  PIN n_FNN_input<2>
    DIRECTION INOUT ;
    USE SIGNAL ;
    PORT
      LAYER METAL3 ;
        RECT 502.45 1609.9 503.85 1612.24 ;
    END
  END n_FNN_input<2>
  PIN n_FNN_input<1>
    DIRECTION INOUT ;
    USE SIGNAL ;
    PORT
      LAYER METAL3 ;
        RECT 488.45 1609.9 489.85 1612.24 ;
    END
  END n_FNN_input<1>
  PIN n_FNN_input<0>
    DIRECTION INOUT ;
    USE SIGNAL ;
    PORT
      LAYER METAL3 ;
        RECT 474.45 1609.9 475.85 1612.24 ;
    END
  END n_FNN_input<0>
  PIN n_FNN_ly0_Dr_En
    DIRECTION INOUT ;
    USE SIGNAL ;
    PORT
      LAYER METAL3 ;
        RECT 460.45 1609.9 461.85 1612.24 ;
    END
  END n_FNN_ly0_Dr_En
  PIN n_FNN_ly0_G_En
    DIRECTION INOUT ;
    USE SIGNAL ;
    PORT
      LAYER METAL3 ;
        RECT 446.45 1609.9 447.85 1612.24 ;
    END
  END n_FNN_ly0_G_En
  PIN n_ActF_Vg_bias
    DIRECTION INOUT ;
    USE SIGNAL ;
    PORT
      LAYER METAL3 ;
        RECT 432.45 1609.9 433.85 1612.24 ;
    END
  END n_ActF_Vg_bias
  PIN n_ActF_selb
    DIRECTION INOUT ;
    USE SIGNAL ;
    PORT
      LAYER METAL3 ;
        RECT 418.45 1609.9 419.85 1612.24 ;
    END
  END n_ActF_selb
  PIN n_ActF_sel
    DIRECTION INOUT ;
    USE SIGNAL ;
    PORT
      LAYER METAL3 ;
        RECT 404.45 1609.9 405.85 1612.24 ;
    END
  END n_ActF_sel
  PIN n_Run_Drainline
    DIRECTION INOUT ;
    USE SIGNAL ;
    PORT
      LAYER METAL3 ;
        RECT 390.45 1609.9 391.85 1612.24 ;
    END
  END n_Run_Drainline
  PIN n_Prog_Drainline
    DIRECTION INOUT ;
    USE SIGNAL ;
    PORT
      LAYER METAL3 ;
        RECT 376.45 1609.9 377.85 1612.24 ;
    END
  END n_Prog_Drainline
  PIN n_FNN_shr_Dr_bit<6>
    DIRECTION INOUT ;
    USE SIGNAL ;
    PORT
      LAYER METAL3 ;
        RECT 362.45 1609.9 363.85 1612.24 ;
    END
  END n_FNN_shr_Dr_bit<6>
  PIN n_FNN_shr_Dr_bit<5>
    DIRECTION INOUT ;
    USE SIGNAL ;
    PORT
      LAYER METAL3 ;
        RECT 348.45 1609.9 349.85 1612.24 ;
    END
  END n_FNN_shr_Dr_bit<5>
  PIN n_FNN_shr_Dr_bit<4>
    DIRECTION INOUT ;
    USE SIGNAL ;
    PORT
      LAYER METAL3 ;
        RECT 334.45 1609.9 335.85 1612.24 ;
    END
  END n_FNN_shr_Dr_bit<4>
  PIN n_FNN_shr_Dr_bit<3>
    DIRECTION INOUT ;
    USE SIGNAL ;
    PORT
      LAYER METAL3 ;
        RECT 320.45 1609.9 321.85 1612.24 ;
    END
  END n_FNN_shr_Dr_bit<3>
  PIN n_FNN_shr_Dr_bit<2>
    DIRECTION INOUT ;
    USE SIGNAL ;
    PORT
      LAYER METAL3 ;
        RECT 306.45 1609.9 307.85 1612.24 ;
    END
  END n_FNN_shr_Dr_bit<2>
  PIN n_FNN_shr_Dr_bit<1>
    DIRECTION INOUT ;
    USE SIGNAL ;
    PORT
      LAYER METAL3 ;
        RECT 292.45 1609.9 293.85 1612.24 ;
    END
  END n_FNN_shr_Dr_bit<1>
  PIN n_FNN_shr_Dr_bit<0>
    DIRECTION INOUT ;
    USE SIGNAL ;
    PORT
      LAYER METAL3 ;
        RECT 278.45 1609.9 279.85 1612.24 ;
    END
  END n_FNN_shr_Dr_bit<0>
  PIN n_FNN_shr_G_bit<7>
    DIRECTION INOUT ;
    USE SIGNAL ;
    PORT
      LAYER METAL3 ;
        RECT 264.45 1609.9 265.85 1612.24 ;
    END
  END n_FNN_shr_G_bit<7>
  PIN n_FNN_shr_G_bit<6>
    DIRECTION INOUT ;
    USE SIGNAL ;
    PORT
      LAYER METAL3 ;
        RECT 250.45 1609.9 251.85 1612.24 ;
    END
  END n_FNN_shr_G_bit<6>
  PIN n_FNN_shr_G_bit<5>
    DIRECTION INOUT ;
    USE SIGNAL ;
    PORT
      LAYER METAL3 ;
        RECT 236.45 1609.9 237.85 1612.24 ;
    END
  END n_FNN_shr_G_bit<5>
  PIN n_FNN_shr_G_bit<4>
    DIRECTION INOUT ;
    USE SIGNAL ;
    PORT
      LAYER METAL3 ;
        RECT 222.45 1609.9 223.85 1612.24 ;
    END
  END n_FNN_shr_G_bit<4>
  PIN n_FNN_shr_G_bit<3>
    DIRECTION INOUT ;
    USE SIGNAL ;
    PORT
      LAYER METAL3 ;
        RECT 208.45 1609.9 209.85 1612.24 ;
    END
  END n_FNN_shr_G_bit<3>
  PIN n_FNN_shr_G_bit<2>
    DIRECTION INOUT ;
    USE SIGNAL ;
    PORT
      LAYER METAL3 ;
        RECT 194.45 1609.9 195.85 1612.24 ;
    END
  END n_FNN_shr_G_bit<2>
  PIN n_FNN_shr_G_bit<1>
    DIRECTION INOUT ;
    USE SIGNAL ;
    PORT
      LAYER METAL3 ;
        RECT 180.45 1609.9 181.85 1612.24 ;
    END
  END n_FNN_shr_G_bit<1>
  PIN n_FNN_shr_G_bit<0>
    DIRECTION INOUT ;
    USE SIGNAL ;
    PORT
      LAYER METAL3 ;
        RECT 166.45 1609.9 167.85 1612.24 ;
    END
  END n_FNN_shr_G_bit<0>
  PIN n_run_hv
    DIRECTION INOUT ;
    USE SIGNAL ;
    PORT
      LAYER METAL3 ;
        RECT 152.45 1609.9 153.85 1612.24 ;
    END
  END n_run_hv
  PIN n_prog_hv
    DIRECTION INOUT ;
    USE SIGNAL ;
    PORT
      LAYER METAL3 ;
        RECT 138.45 1609.9 139.85 1612.24 ;
    END
  END n_prog_hv
  PIN n_VGRUN
    DIRECTION INOUT ;
    USE SIGNAL ;
    PORT
      LAYER METAL3 ;
        RECT 124.45 1609.9 125.85 1612.24 ;
    END
  END n_VGRUN
  PIN n_VGPROG
    DIRECTION INOUT ;
    USE SIGNAL ;
    PORT
      LAYER METAL3 ;
        RECT 110.45 1609.9 111.85 1612.24 ;
    END
  END n_VGPROG
  PIN n_VINJ
    DIRECTION INOUT ;
    USE SIGNAL ;
    PORT
      LAYER METAL3 ;
        RECT 96.45 1609.9 97.85 1612.24 ;
    END
  END n_VINJ
  PIN n_GND
    DIRECTION INOUT ;
    USE SIGNAL ;
    PORT
      LAYER METAL3 ;
        RECT 82.45 1609.9 83.85 1612.24 ;
    END
  END n_GND
  PIN n_AVDD
    DIRECTION INOUT ;
    USE SIGNAL ;
    PORT
      LAYER METAL3 ;
        RECT 68.45 1609.9 69.85 1612.24 ;
    END
  END n_AVDD
  PIN n_DVDD
    DIRECTION INOUT ;
    USE SIGNAL ;
    PORT
      LAYER METAL3 ;
        RECT 54.45 1609.9 55.85 1612.24 ;
    END
  END n_DVDD
  PIN n_VTUN
    DIRECTION INOUT ;
    USE SIGNAL ;
    PORT
      LAYER METAL3 ;
        RECT 40.45 1609.9 41.85 1612.24 ;
    END
  END n_VTUN
  PIN n_FNN_shr_Dr_bit<7>
    DIRECTION INOUT ;
    USE SIGNAL ;
    PORT
      LAYER METAL3 ;
        RECT 368.99 1609.9 370.39 1612.24 ;
    END
  END n_FNN_shr_Dr_bit<7>
  PIN n_FNN_input<63>
    DIRECTION INOUT ;
    USE SIGNAL ;
    PORT
      LAYER METAL3 ;
        RECT 1356.45 1609.9 1357.85 1612.24 ;
    END
  END n_FNN_input<63>
  PIN s_VMM_WTA_out_11
    DIRECTION INOUT ;
    USE SIGNAL ;
    PORT
      LAYER METAL3 ;
        RECT 4573.59 0.0 4574.99 2.8 ;
    END
  END s_VMM_WTA_out_11
  PIN s_FNN_ly1_out_63
    DIRECTION INOUT ;
    USE SIGNAL ;
    PORT
      LAYER METAL3 ;
        RECT 5355.79 0.0 5357.19 2.8 ;
    END
  END s_FNN_ly1_out_63
  PIN s_VMM_WTA_out_10
    DIRECTION INOUT ;
    USE SIGNAL ;
    PORT
      LAYER METAL3 ;
        RECT 4559.59 0.0 4560.99 2.8 ;
    END
  END s_VMM_WTA_out_10
  PIN s_FNN_diocon_dbg
    DIRECTION INOUT ;
    USE SIGNAL ;
    PORT
      LAYER METAL3 ;
        RECT 2850.64 0.0 2852.04 2.8 ;
    END
  END s_FNN_diocon_dbg
END FullyCon_NN

MACRO TSMC350nm_LVLShift_x16
  PIN OUT<2>
    DIRECTION INOUT ;
    USE SIGNAL ;
    PORT
      LAYER METAL2 ;
        RECT 30.67 0.0 32.07 0.85 ;
    END
  END OUT<2>
  PIN OUT<15>
    DIRECTION INOUT ;
    USE SIGNAL ;
    PORT
      LAYER METAL2 ;
        RECT 171.23 0.0 172.63 0.85 ;
    END
  END OUT<15>
  PIN OUT<13>
    DIRECTION INOUT ;
    USE SIGNAL ;
    PORT
      LAYER METAL2 ;
        RECT 148.97 0.0 150.37 0.85 ;
    END
  END OUT<13>
  PIN OUT<14>
    DIRECTION INOUT ;
    USE SIGNAL ;
    PORT
      LAYER METAL2 ;
        RECT 164.23 0.0 165.63 0.85 ;
    END
  END OUT<14>
  PIN OUT<11>
    DIRECTION INOUT ;
    USE SIGNAL ;
    PORT
      LAYER METAL2 ;
        RECT 126.71 0.0 128.11 0.85 ;
    END
  END OUT<11>
  PIN OUT<12>
    DIRECTION INOUT ;
    USE SIGNAL ;
    PORT
      LAYER METAL2 ;
        RECT 141.97 0.0 143.37 0.85 ;
    END
  END OUT<12>
  PIN OUT<9>
    DIRECTION INOUT ;
    USE SIGNAL ;
    PORT
      LAYER METAL2 ;
        RECT 104.45 0.0 105.85 0.85 ;
    END
  END OUT<9>
  PIN OUT<10>
    DIRECTION INOUT ;
    USE SIGNAL ;
    PORT
      LAYER METAL2 ;
        RECT 119.71 0.0 121.11 0.85 ;
    END
  END OUT<10>
  PIN OUT<7>
    DIRECTION INOUT ;
    USE SIGNAL ;
    PORT
      LAYER METAL2 ;
        RECT 82.19 0.0 83.59 0.85 ;
    END
  END OUT<7>
  PIN OUT<8>
    DIRECTION INOUT ;
    USE SIGNAL ;
    PORT
      LAYER METAL2 ;
        RECT 97.45 0.0 98.85 0.85 ;
    END
  END OUT<8>
  PIN OUT<5>
    DIRECTION INOUT ;
    USE SIGNAL ;
    PORT
      LAYER METAL2 ;
        RECT 59.93 0.0 61.33 0.85 ;
    END
  END OUT<5>
  PIN OUT<6>
    DIRECTION INOUT ;
    USE SIGNAL ;
    PORT
      LAYER METAL2 ;
        RECT 75.19 0.0 76.59 0.85 ;
    END
  END OUT<6>
  PIN OUT<3>
    DIRECTION INOUT ;
    USE SIGNAL ;
    PORT
      LAYER METAL2 ;
        RECT 37.67 0.0 39.07 0.85 ;
    END
  END OUT<3>
  PIN OUT<4>
    DIRECTION INOUT ;
    USE SIGNAL ;
    PORT
      LAYER METAL2 ;
        RECT 52.93 0.0 54.33 0.85 ;
    END
  END OUT<4>
  PIN Vin<12>
    DIRECTION INOUT ;
    USE SIGNAL ;
    PORT
      LAYER METAL2 ;
        RECT 141.4 31.5 142.82 32.25 ;
    END
  END Vin<12>
  PIN Vin<1>
    DIRECTION INOUT ;
    USE SIGNAL ;
    PORT
      LAYER METAL2 ;
        RECT 15.96 31.5 17.5 32.25 ;
    END
  END Vin<1>
  PIN Vin<3>
    DIRECTION INOUT ;
    USE SIGNAL ;
    PORT
      LAYER METAL2 ;
        RECT 38.22 31.5 39.9 32.25 ;
    END
  END Vin<3>
  PIN Vin<7>
    DIRECTION INOUT ;
    USE SIGNAL ;
    PORT
      LAYER METAL2 ;
        RECT 82.74 31.5 84.7 32.25 ;
    END
  END Vin<7>
  PIN Vin<15>
    DIRECTION INOUT ;
    USE SIGNAL ;
    PORT
      LAYER METAL2 ;
        RECT 171.78 31.5 173.6 32.25 ;
    END
  END Vin<15>
  PIN OUT<0>
    DIRECTION INOUT ;
    USE SIGNAL ;
    PORT
      LAYER METAL2 ;
        RECT 8.41 0.0 9.81 0.85 ;
    END
  END OUT<0>
  PIN VINJ
    DIRECTION INOUT ;
    USE SIGNAL ;
    PORT
      LAYER METAL2 ;
        RECT 0.0 18.01 1.4 19.6 ;
    END
  END VINJ
  PIN Vin<0>
    DIRECTION INOUT ;
    USE SIGNAL ;
    PORT
      LAYER METAL2 ;
        RECT 7.7 31.5 9.26 32.25 ;
    END
  END Vin<0>
  PIN OUT<1>
    DIRECTION INOUT ;
    USE SIGNAL ;
    PORT
      LAYER METAL2 ;
        RECT 15.41 0.0 16.81 0.85 ;
    END
  END OUT<1>
  PIN DVDD
    DIRECTION INOUT ;
    USE SIGNAL ;
    PORT
      LAYER METAL2 ;
        RECT 0.0 28.0 1.4 29.59 ;
    END
  END DVDD
  PIN Vin<2>
    DIRECTION INOUT ;
    USE SIGNAL ;
    PORT
      LAYER METAL2 ;
        RECT 30.1 31.5 31.52 32.25 ;
    END
  END Vin<2>
  PIN Vin<13>
    DIRECTION INOUT ;
    USE SIGNAL ;
    PORT
      LAYER METAL2 ;
        RECT 149.52 31.5 151.2 32.25 ;
    END
  END Vin<13>
  PIN Vin<11>
    DIRECTION INOUT ;
    USE SIGNAL ;
    PORT
      LAYER METAL2 ;
        RECT 127.26 31.5 128.8 32.25 ;
    END
  END Vin<11>
  PIN Vin<9>
    DIRECTION INOUT ;
    USE SIGNAL ;
    PORT
      LAYER METAL2 ;
        RECT 105.0 31.5 106.4 32.25 ;
    END
  END Vin<9>
  PIN Vin<5>
    DIRECTION INOUT ;
    USE SIGNAL ;
    PORT
      LAYER METAL2 ;
        RECT 60.48 31.5 62.3 32.25 ;
    END
  END Vin<5>
  PIN Vin<8>
    DIRECTION INOUT ;
    USE SIGNAL ;
    PORT
      LAYER METAL2 ;
        RECT 96.6 31.5 98.3 32.25 ;
    END
  END Vin<8>
  PIN Vin<10>
    DIRECTION INOUT ;
    USE SIGNAL ;
    PORT
      LAYER METAL2 ;
        RECT 119.0 31.5 120.56 32.25 ;
    END
  END Vin<10>
  PIN Vin<6>
    DIRECTION INOUT ;
    USE SIGNAL ;
    PORT
      LAYER METAL2 ;
        RECT 74.2 31.5 76.04 32.25 ;
    END
  END Vin<6>
  PIN Vin<4>
    DIRECTION INOUT ;
    USE SIGNAL ;
    PORT
      LAYER METAL2 ;
        RECT 52.5 31.5 53.9 32.25 ;
    END
  END Vin<4>
  PIN Vin<14>
    DIRECTION INOUT ;
    USE SIGNAL ;
    PORT
      LAYER METAL2 ;
        RECT 163.1 31.5 165.08 32.25 ;
    END
  END Vin<14>
  PIN GND
    DIRECTION INOUT ;
    USE SIGNAL ;
    PORT
      LAYER METAL1 ;
        RECT 0.0 23.81 1.4 25.2 ;
    END
  END GND
END TSMC350nm_LVLShift_x16

MACRO TSMC350nm_DigBuffer_x2
  PIN GND
    DIRECTION INOUT ;
    USE SIGNAL ;
    PORT
      LAYER METAL2 ;
        RECT 9.1 0.0 10.5 1.2 ;
    END
  END GND
  PIN VINJ
    DIRECTION INOUT ;
    USE SIGNAL ;
    PORT
      LAYER METAL2 ;
        RECT 36.4 0.0 37.8 1.03 ;
    END
  END VINJ
  PIN Out<1>
    DIRECTION INOUT ;
    USE SIGNAL ;
    PORT
      LAYER METAL2 ;
        RECT 28.7 0.0 30.1 1.2 ;
    END
  END Out<1>
  PIN Out<0>
    DIRECTION INOUT ;
    USE SIGNAL ;
    PORT
      LAYER METAL2 ;
        RECT 17.5 0.0 18.9 1.2 ;
    END
  END Out<0>
  PIN In<1>
    DIRECTION INOUT ;
    USE SIGNAL ;
    PORT
      LAYER METAL1 ;
        RECT 36.4 10.96 37.8 11.74 ;
    END
  END In<1>
  PIN In<0>
    DIRECTION INOUT ;
    USE SIGNAL ;
    PORT
      LAYER METAL1 ;
        RECT 9.8 10.96 11.2 11.74 ;
    END
  END In<0>
END TSMC350nm_DigBuffer_x2

MACRO TSMC350nm_4TGate_ST_BMatrix
  PIN In<0>
    DIRECTION INOUT ;
    USE SIGNAL ;
    PORT
      LAYER METAL1 ;
        RECT 0.0 17.5 0.27 18.0 ;
    END
  END In<0>
  PIN In<1>
    DIRECTION INOUT ;
    USE SIGNAL ;
    PORT
      LAYER METAL1 ;
        RECT 0.0 14.7 0.38 15.2 ;
    END
  END In<1>
  PIN In<2>
    DIRECTION INOUT ;
    USE SIGNAL ;
    PORT
      LAYER METAL1 ;
        RECT 0.0 7.0 0.36 7.5 ;
    END
  END In<2>
  PIN In<3>
    DIRECTION INOUT ;
    USE SIGNAL ;
    PORT
      LAYER METAL1 ;
        RECT 0.0 3.5 0.3 4.0 ;
    END
  END In<3>
  PIN A<0>
    DIRECTION INOUT ;
    USE SIGNAL ;
    PORT
      LAYER METAL1 ;
        RECT 10.6 17.6 12.0 18.9 ;
    END
  END A<0>
  PIN A<1>
    DIRECTION INOUT ;
    USE SIGNAL ;
    PORT
      LAYER METAL1 ;
        RECT 10.6 14.9 12.0 16.2 ;
    END
  END A<1>
  PIN A<2>
    DIRECTION INOUT ;
    USE SIGNAL ;
    PORT
      LAYER METAL1 ;
        RECT 10.6 6.8 12.0 8.1 ;
    END
  END A<2>
  PIN A<3>
    DIRECTION INOUT ;
    USE SIGNAL ;
    PORT
      LAYER METAL1 ;
        RECT 10.6 4.1 12.0 5.4 ;
    END
  END A<3>
  PIN P<0>
    DIRECTION INOUT ;
    USE SIGNAL ;
    PORT
      LAYER METAL1 ;
        RECT 10.6 20.3 12.0 21.6 ;
    END
  END P<0>
  PIN P<1>
    DIRECTION INOUT ;
    USE SIGNAL ;
    PORT
      LAYER METAL1 ;
        RECT 10.6 12.2 12.0 13.5 ;
    END
  END P<1>
  PIN P<2>
    DIRECTION INOUT ;
    USE SIGNAL ;
    PORT
      LAYER METAL1 ;
        RECT 10.6 9.5 12.0 10.8 ;
    END
  END P<2>
  PIN P<3>
    DIRECTION INOUT ;
    USE SIGNAL ;
    PORT
      LAYER METAL1 ;
        RECT 10.6 1.4 12.0 2.7 ;
    END
  END P<3>
  PIN GND_b
    DIRECTION INOUT ;
    USE SIGNAL ;
    PORT
      LAYER METAL2 ;
        RECT 6.35 0.0 7.25 0.88 ;
    END
  END GND_b
  PIN Prog_b
    DIRECTION INOUT ;
    USE SIGNAL ;
    PORT
      LAYER METAL2 ;
        RECT 4.1 0.0 4.7 0.78 ;
    END
  END Prog_b
  PIN VDD_b
    DIRECTION INOUT ;
    USE SIGNAL ;
    PORT
      LAYER METAL2 ;
        RECT 1.81 0.0 2.71 0.71 ;
    END
  END VDD_b
  PIN Prog
    DIRECTION INOUT ;
    USE SIGNAL ;
    PORT
      LAYER METAL2 ;
        RECT 4.1 21.3 4.7 22.0 ;
    END
  END Prog
  PIN VDD
    DIRECTION INOUT ;
    USE SIGNAL ;
    PORT
      LAYER METAL2 ;
        RECT 1.81 21.3 2.71 22.0 ;
    END
  END VDD
  PIN GND
    DIRECTION INOUT ;
    USE SIGNAL ;
    PORT
      LAYER METAL2 ;
        RECT 6.35 21.3 7.25 22.0 ;
    END
  END GND
END TSMC350nm_4TGate_ST_BMatrix

MACRO TSMC350nm_VinjDecode2to4_vtile_spacing
END TSMC350nm_VinjDecode2to4_vtile_spacing

MACRO TSMC350nm_VinjDecode2to4_vtile_D_bridge
END TSMC350nm_VinjDecode2to4_vtile_D_bridge

MACRO TSMC350nm_VinjDecode2to4_vtile
  PIN Vinj
    DIRECTION INOUT ;
    USE SIGNAL ;
    PORT
      LAYER METAL1 ;
        RECT 7.78 11.04 9.06 11.45 ;
    END
  END Vinj
  PIN OUT<0>
    DIRECTION INOUT ;
    USE SIGNAL ;
    PORT
      LAYER METAL1 ;
        RECT 19.66 18.91 20.11 19.59 ;
    END
  END OUT<0>
  PIN OUT<1>
    DIRECTION INOUT ;
    USE SIGNAL ;
    PORT
      LAYER METAL1 ;
        RECT 19.66 13.41 20.12 14.1 ;
    END
  END OUT<1>
  PIN OUT<2>
    DIRECTION INOUT ;
    USE SIGNAL ;
    PORT
      LAYER METAL1 ;
        RECT 19.66 7.92 20.11 8.59 ;
    END
  END OUT<2>
  PIN OUT<3>
    DIRECTION INOUT ;
    USE SIGNAL ;
    PORT
      LAYER METAL1 ;
        RECT 19.66 2.41 20.11 3.09 ;
    END
  END OUT<3>
  PIN ENABLE
    DIRECTION INOUT ;
    USE SIGNAL ;
    PORT
      LAYER METAL1 ;
        RECT 0.01 3.48 0.71 4.21 ;
    END
  END ENABLE
  PIN GND
    DIRECTION INOUT ;
    USE SIGNAL ;
    PORT
      LAYER METAL1 ;
        RECT 19.52 5.0 20.12 5.99 ;
    END
  END GND
  PIN VINJ
    DIRECTION INOUT ;
    USE SIGNAL ;
    PORT
      LAYER METAL1 ;
        RECT 19.15 21.56 20.05 21.96 ;
    END
  END VINJ
  PIN IN<1>
    DIRECTION INOUT ;
    USE SIGNAL ;
    PORT
      LAYER METAL2 ;
        RECT 6.56 20.89 7.5 22.0 ;
    END
  END IN<1>
  PIN IN<0>
    DIRECTION INOUT ;
    USE SIGNAL ;
    PORT
      LAYER METAL2 ;
        RECT 3.9 20.96 4.5 22.0 ;
    END
  END IN<0>
END TSMC350nm_VinjDecode2to4_vtile

MACRO TSMC350nm_VinjDecode2to4_vtile_C_bridge
END TSMC350nm_VinjDecode2to4_vtile_C_bridge

MACRO TSMC350nm_VinjDecode2to4_vtile_B_bridge
END TSMC350nm_VinjDecode2to4_vtile_B_bridge

MACRO TSMC350nm_VinjDecode2to4_vtile_A_bridge
END TSMC350nm_VinjDecode2to4_vtile_A_bridge

MACRO TSMC350nm_drainSelect_progrundrains
  PIN prog_drain<3>
    DIRECTION INOUT ;
    USE SIGNAL ;
    PORT
      LAYER METAL1 ;
        RECT 30.93 0.93 31.86 1.43 ;
    END
  END prog_drain<3>
  PIN prog_drain<2>
    DIRECTION INOUT ;
    USE SIGNAL ;
    PORT
      LAYER METAL1 ;
        RECT 30.97 9.62 31.86 10.12 ;
    END
  END prog_drain<2>
  PIN prog_drain<1>
    DIRECTION INOUT ;
    USE SIGNAL ;
    PORT
      LAYER METAL1 ;
        RECT 31.0 13.97 31.86 14.47 ;
    END
  END prog_drain<1>
  PIN run_drain<3>
    DIRECTION INOUT ;
    USE SIGNAL ;
    PORT
      LAYER METAL1 ;
        RECT 31.01 2.45 31.86 2.95 ;
    END
  END run_drain<3>
  PIN run_drain<2>
    DIRECTION INOUT ;
    USE SIGNAL ;
    PORT
      LAYER METAL1 ;
        RECT 30.94 5.31 31.86 5.81 ;
    END
  END run_drain<2>
  PIN prog_drain<0>
    DIRECTION INOUT ;
    USE SIGNAL ;
    PORT
      LAYER METAL1 ;
        RECT 31.12 20.75 31.86 21.25 ;
    END
  END prog_drain<0>
  PIN GND
    DIRECTION INOUT ;
    USE SIGNAL ;
    PORT
      LAYER METAL2 ;
        RECT 4.19 21.33 4.99 22.0 ;
    END
  END GND
  PIN VINJ
    DIRECTION INOUT ;
    USE SIGNAL ;
    PORT
      LAYER METAL1 ;
        RECT 1.4 21.5 2.8 22.0 ;
    END
  END VINJ
  PIN run_drain<0>
    DIRECTION INOUT ;
    USE SIGNAL ;
    PORT
      LAYER METAL1 ;
        RECT 31.01 19.56 31.86 20.06 ;
    END
  END run_drain<0>
  PIN run_drain<1>
    DIRECTION INOUT ;
    USE SIGNAL ;
    PORT
      LAYER METAL1 ;
        RECT 31.04 16.75 31.86 17.24 ;
    END
  END run_drain<1>
  PIN SELECT<3>
    DIRECTION INOUT ;
    USE SIGNAL ;
    PORT
      LAYER METAL1 ;
        RECT 0.0 2.54 0.67 2.97 ;
    END
  END SELECT<3>
  PIN SELET<2>
    DIRECTION INOUT ;
    USE SIGNAL ;
    PORT
      LAYER METAL1 ;
        RECT 0.0 8.03 0.67 8.46 ;
    END
  END SELET<2>
  PIN SELECT<1>
    DIRECTION INOUT ;
    USE SIGNAL ;
    PORT
      LAYER METAL1 ;
        RECT 0.0 13.54 0.67 13.97 ;
    END
  END SELECT<1>
  PIN SELECT<0>
    DIRECTION INOUT ;
    USE SIGNAL ;
    PORT
      LAYER METAL1 ;
        RECT 0.0 18.9 0.67 19.6 ;
    END
  END SELECT<0>
  PIN VINJ_b
    DIRECTION INOUT ;
    USE SIGNAL ;
    PORT
      LAYER METAL2 ;
        RECT 21.94 0.0 23.29 0.58 ;
    END
  END VINJ_b
  PIN GND_b
    DIRECTION INOUT ;
    USE SIGNAL ;
    PORT
      LAYER METAL2 ;
        RECT 17.16 0.0 18.16 0.58 ;
    END
  END GND_b
  PIN run_drainrail
    DIRECTION INOUT ;
    USE SIGNAL ;
    PORT
      LAYER METAL2 ;
        RECT 27.01 21.19 27.71 22.0 ;
    END
  END run_drainrail
  PIN prog_drainrail
    DIRECTION INOUT ;
    USE SIGNAL ;
    PORT
      LAYER METAL2 ;
        RECT 7.36 21.34 8.16 22.0 ;
    END
  END prog_drainrail
END TSMC350nm_drainSelect_progrundrains

MACRO TSMC350nm_4TGate_ST_draincutoff
  PIN In<0>
    DIRECTION INOUT ;
    USE SIGNAL ;
    PORT
      LAYER METAL1 ;
        RECT 9.96 17.5 10.6 18.45 ;
    END
  END In<0>
  PIN In<1>
    DIRECTION INOUT ;
    USE SIGNAL ;
    PORT
      LAYER METAL1 ;
        RECT 9.91 14.7 10.6 15.93 ;
    END
  END In<1>
  PIN In<2>
    DIRECTION INOUT ;
    USE SIGNAL ;
    PORT
      LAYER METAL1 ;
        RECT 10.01 6.9 10.6 7.8 ;
    END
  END In<2>
  PIN In<3>
    DIRECTION INOUT ;
    USE SIGNAL ;
    PORT
      LAYER METAL1 ;
        RECT 10.02 3.5 10.6 4.3 ;
    END
  END In<3>
  PIN A<0>
    DIRECTION INOUT ;
    USE SIGNAL ;
    PORT
      LAYER METAL1 ;
        RECT 0.0 19.56 1.4 20.06 ;
    END
  END A<0>
  PIN A<1>
    DIRECTION INOUT ;
    USE SIGNAL ;
    PORT
      LAYER METAL1 ;
        RECT 0.0 16.75 1.4 17.25 ;
    END
  END A<1>
  PIN A<2>
    DIRECTION INOUT ;
    USE SIGNAL ;
    PORT
      LAYER METAL1 ;
        RECT 0.0 5.3 1.4 5.8 ;
    END
  END A<2>
  PIN A<3>
    DIRECTION INOUT ;
    USE SIGNAL ;
    PORT
      LAYER METAL1 ;
        RECT 0.0 2.45 1.4 2.95 ;
    END
  END A<3>
  PIN P<0>
    DIRECTION INOUT ;
    USE SIGNAL ;
    PORT
      LAYER METAL1 ;
        RECT 0.0 20.75 1.4 21.25 ;
    END
  END P<0>
  PIN P<1>
    DIRECTION INOUT ;
    USE SIGNAL ;
    PORT
      LAYER METAL1 ;
        RECT 0.0 13.97 1.4 14.47 ;
    END
  END P<1>
  PIN P<2>
    DIRECTION INOUT ;
    USE SIGNAL ;
    PORT
      LAYER METAL1 ;
        RECT 0.0 9.62 1.4 10.12 ;
    END
  END P<2>
  PIN P<3>
    DIRECTION INOUT ;
    USE SIGNAL ;
    PORT
      LAYER METAL1 ;
        RECT 0.0 0.93 1.4 1.43 ;
    END
  END P<3>
  PIN PR<0>
    DIRECTION INOUT ;
    USE SIGNAL ;
    PORT
      LAYER METAL1 ;
        RECT 10.0 20.3 10.6 21.25 ;
    END
  END PR<0>
  PIN PR<1>
    DIRECTION INOUT ;
    USE SIGNAL ;
    PORT
      LAYER METAL1 ;
        RECT 10.13 11.9 10.6 12.8 ;
    END
  END PR<1>
  PIN PR<2>
    DIRECTION INOUT ;
    USE SIGNAL ;
    PORT
      LAYER METAL1 ;
        RECT 10.0 9.4 10.6 10.3 ;
    END
  END PR<2>
  PIN PR<3>
    DIRECTION INOUT ;
    USE SIGNAL ;
    PORT
      LAYER METAL1 ;
        RECT 10.0 0.7 10.6 1.6 ;
    END
  END PR<3>
  PIN VDD_b
    DIRECTION INOUT ;
    USE SIGNAL ;
    PORT
      LAYER METAL2 ;
        RECT 7.89 0.0 8.79 0.54 ;
    END
  END VDD_b
  PIN RUN
    DIRECTION INOUT ;
    USE SIGNAL ;
    PORT
      LAYER METAL2 ;
        RECT 5.9 21.13 6.5 22.0 ;
    END
  END RUN
  PIN VDD
    DIRECTION INOUT ;
    USE SIGNAL ;
    PORT
      LAYER METAL2 ;
        RECT 7.89 21.3 8.79 22.0 ;
    END
  END VDD
  PIN GND
    DIRECTION INOUT ;
    USE SIGNAL ;
    PORT
      LAYER METAL2 ;
        RECT 3.35 21.3 4.25 22.0 ;
    END
  END GND
  PIN GND_b
    DIRECTION INOUT ;
    USE SIGNAL ;
    PORT
      LAYER METAL2 ;
        RECT 3.35 0.0 4.25 0.73 ;
    END
  END GND_b
  PIN RUN_b
    DIRECTION INOUT ;
    USE SIGNAL ;
    PORT
      LAYER METAL2 ;
        RECT 5.9 0.0 6.5 0.71 ;
    END
  END RUN_b
END TSMC350nm_4TGate_ST_draincutoff

MACRO TSMC350nm_IndirectSwitches
  PIN GND_B<1>
    DIRECTION INOUT ;
    USE SIGNAL ;
    PORT
      LAYER METAL2 ;
        RECT 15.41 0.0 16.01 0.85 ;
    END
  END GND_B<1>
  PIN GND_B<0>
    DIRECTION INOUT ;
    USE SIGNAL ;
    PORT
      LAYER METAL2 ;
        RECT 11.2 0.0 11.8 0.85 ;
    END
  END GND_B<0>
  PIN GND
    DIRECTION INOUT ;
    USE SIGNAL ;
    PORT
      LAYER METAL2 ;
        RECT 11.2 3.21 11.8 3.6 ;
    END
  END GND
  PIN GND_T
    DIRECTION INOUT ;
    USE SIGNAL ;
    PORT
      LAYER METAL2 ;
        RECT 15.4 21.0 16.2 22.0 ;
    END
  END GND_T
  PIN VINJ_T
    DIRECTION INOUT ;
    USE SIGNAL ;
    PORT
      LAYER METAL2 ;
        RECT 6.3 21.04 7.32 22.0 ;
    END
  END VINJ_T
  PIN VDD<1>
    DIRECTION INOUT ;
    USE SIGNAL ;
    PORT
      LAYER METAL2 ;
        RECT 24.5 0.0 25.1 0.75 ;
    END
  END VDD<1>
  PIN VTUN
    DIRECTION INOUT ;
    USE SIGNAL ;
    PORT
      LAYER METAL2 ;
        RECT 13.3 0.0 13.9 0.82 ;
    END
  END VTUN
  PIN VINJ
    DIRECTION INOUT ;
    USE SIGNAL ;
    PORT
      LAYER METAL2 ;
        RECT 4.2 0.0 4.8 1.0 ;
    END
  END VINJ
  PIN VDD<0>
    DIRECTION INOUT ;
    USE SIGNAL ;
    PORT
      LAYER METAL2 ;
        RECT 2.1 0.0 2.7 1.09 ;
    END
  END VDD<0>
  PIN Vg<0>
    DIRECTION INOUT ;
    USE SIGNAL ;
    PORT
      LAYER METAL2 ;
        RECT 8.4 0.005 9.0 0.825 ;
    END
  END Vg<0>
  PIN CTRL_B<0>
    DIRECTION INOUT ;
    USE SIGNAL ;
    PORT
      LAYER METAL2 ;
        RECT 6.3 0.01 6.9 0.76 ;
    END
  END CTRL_B<0>
  PIN CTRL_B<1>
    DIRECTION INOUT ;
    USE SIGNAL ;
    PORT
      LAYER METAL2 ;
        RECT 20.3 0.01 20.9 0.75 ;
    END
  END CTRL_B<1>
  PIN Vg<1>
    DIRECTION INOUT ;
    USE SIGNAL ;
    PORT
      LAYER METAL2 ;
        RECT 18.2 0.0 18.8 0.76 ;
    END
  END Vg<1>
  PIN decode<0>
    DIRECTION INOUT ;
    USE SIGNAL ;
    PORT
      LAYER METAL2 ;
        RECT 3.46 21.16 4.8 22.0 ;
    END
  END decode<0>
  PIN RUN_IN<1>
    DIRECTION INOUT ;
    USE SIGNAL ;
    PORT
      LAYER METAL2 ;
        RECT 17.5 21.01 18.1 22.0 ;
    END
  END RUN_IN<1>
  PIN RUN_IN<0>
    DIRECTION INOUT ;
    USE SIGNAL ;
    PORT
      LAYER METAL2 ;
        RECT 10.5 20.9 11.1 22.0 ;
    END
  END RUN_IN<0>
  PIN VPWR<1>
    DIRECTION INOUT ;
    USE SIGNAL ;
    PORT
      LAYER METAL2 ;
        RECT 21.7 21.08 22.3 22.0 ;
    END
  END VPWR<1>
  PIN decode<1>
    DIRECTION INOUT ;
    USE SIGNAL ;
    PORT
      LAYER METAL2 ;
        RECT 23.8 21.09 25.0 22.0 ;
    END
  END decode<1>
  PIN VPWR<0>
    DIRECTION INOUT ;
    USE SIGNAL ;
    PORT
      LAYER METAL2 ;
        RECT 1.71 21.21 2.43 22.0 ;
    END
  END VPWR<0>
  PIN VTUN_T
    DIRECTION INOUT ;
    USE SIGNAL ;
    PORT
      LAYER METAL2 ;
        RECT 12.6 21.12 13.7 22.0 ;
    END
  END VTUN_T
  PIN vtun_r
    DIRECTION INOUT ;
    USE SIGNAL ;
    PORT
      LAYER METAL1 ;
        RECT 26.17 0.9 27.46 2.17 ;
    END
  END vtun_r
  PIN vgsel_r
    DIRECTION INOUT ;
    USE SIGNAL ;
    PORT
      LAYER METAL1 ;
        RECT 26.52 3.15 27.46 4.45 ;
    END
  END vgsel_r
  PIN prog_r
    DIRECTION INOUT ;
    USE SIGNAL ;
    PORT
      LAYER METAL1 ;
        RECT 26.59 9.15 27.46 10.55 ;
    END
  END prog_r
  PIN run_r
    DIRECTION INOUT ;
    USE SIGNAL ;
    PORT
      LAYER METAL1 ;
        RECT 26.28 6.05 27.46 7.29 ;
    END
  END run_r
  PIN RUN
    DIRECTION INOUT ;
    USE SIGNAL ;
    PORT
      LAYER METAL1 ;
        RECT 0.0 6.05 0.91 7.29 ;
    END
  END RUN
  PIN PROG
    DIRECTION INOUT ;
    USE SIGNAL ;
    PORT
      LAYER METAL1 ;
        RECT 0.0 9.15 0.87 10.55 ;
    END
  END PROG
  PIN Vgsel
    DIRECTION INOUT ;
    USE SIGNAL ;
    PORT
      LAYER METAL1 ;
        RECT 0.0 3.72 0.91 4.45 ;
    END
  END Vgsel
  PIN vtun_l
    DIRECTION INOUT ;
    USE SIGNAL ;
    PORT
      LAYER METAL1 ;
        RECT 0.0 0.9 1.31 1.88 ;
    END
  END vtun_l
END TSMC350nm_IndirectSwitches

MACRO TSMC350nm_AnalogBuffer
  PIN Vd_P
    DIRECTION INOUT ;
    USE SIGNAL ;
    PORT
      LAYER METAL1 ;
        RECT 0.0 9.34 1.4 10.74 ;
    END
  END Vd_P
  PIN Vin
    DIRECTION INOUT ;
    USE SIGNAL ;
    PORT
      LAYER METAL1 ;
        RECT 0.0 1.34 1.4 2.74 ;
    END
  END Vin
  PIN VDD_b
    DIRECTION INOUT ;
    USE SIGNAL ;
    PORT
      LAYER METAL2 ;
        RECT 78.18 0.0 79.58 1.4 ;
    END
  END VDD_b
  PIN GND_b
    DIRECTION INOUT ;
    USE SIGNAL ;
    PORT
      LAYER METAL2 ;
        RECT 43.36 0.0 44.76 1.4 ;
    END
  END GND_b
  PIN VTUN_b
    DIRECTION INOUT ;
    USE SIGNAL ;
    PORT
      LAYER METAL2 ;
        RECT 1.9 0.0 3.3 1.4 ;
    END
  END VTUN_b
  PIN Vg_b
    DIRECTION INOUT ;
    USE SIGNAL ;
    PORT
      LAYER METAL2 ;
        RECT 4.75 0.0 6.15 1.4 ;
    END
  END Vg_b
  PIN VINJ_b
    DIRECTION INOUT ;
    USE SIGNAL ;
    PORT
      LAYER METAL2 ;
        RECT 8.37 0.0 9.77 1.4 ;
    END
  END VINJ_b
  PIN Vsel_b
    DIRECTION INOUT ;
    USE SIGNAL ;
    PORT
      LAYER METAL2 ;
        RECT 12.03 0.0 13.43 1.4 ;
    END
  END Vsel_b
  PIN Vout
    DIRECTION INOUT ;
    USE SIGNAL ;
    PORT
      LAYER METAL2 ;
        RECT 87.38 16.98 88.78 18.38 ;
    END
  END Vout
  PIN VDD
    DIRECTION INOUT ;
    USE SIGNAL ;
    PORT
      LAYER METAL2 ;
        RECT 78.18 20.6 79.58 22.0 ;
    END
  END VDD
  PIN GND
    DIRECTION INOUT ;
    USE SIGNAL ;
    PORT
      LAYER METAL2 ;
        RECT 43.36 20.6 44.76 22.0 ;
    END
  END GND
  PIN Vsel
    DIRECTION INOUT ;
    USE SIGNAL ;
    PORT
      LAYER METAL2 ;
        RECT 12.03 20.6 13.43 22.0 ;
    END
  END Vsel
  PIN VINJ
    DIRECTION INOUT ;
    USE SIGNAL ;
    PORT
      LAYER METAL2 ;
        RECT 8.37 20.6 9.77 22.0 ;
    END
  END VINJ
  PIN Vg
    DIRECTION INOUT ;
    USE SIGNAL ;
    PORT
      LAYER METAL2 ;
        RECT 4.75 20.6 6.15 22.0 ;
    END
  END Vg
  PIN VTUN
    DIRECTION INOUT ;
    USE SIGNAL ;
    PORT
      LAYER METAL2 ;
        RECT 1.9 20.6 3.3 22.0 ;
    END
  END VTUN
END TSMC350nm_AnalogBuffer

MACRO frame_6p9mm_6p2mm_digbuf
  PIN buf_vdd_W<6>
    DIRECTION INOUT ;
    USE SIGNAL ;
    PORT
      LAYER METAL1 ;
        RECT 193.55 3991.65 194.95 3993.05 ;
    END
  END buf_vdd_W<6>
  PIN buf_vdd_W<5>
    DIRECTION INOUT ;
    USE SIGNAL ;
    PORT
      LAYER METAL1 ;
        RECT 193.55 4097.65 194.95 4099.05 ;
    END
  END buf_vdd_W<5>
  PIN buf_vdd_W<4>
    DIRECTION INOUT ;
    USE SIGNAL ;
    PORT
      LAYER METAL1 ;
        RECT 193.55 4203.65 194.95 4205.05 ;
    END
  END buf_vdd_W<4>
  PIN buf_vdd_W<3>
    DIRECTION INOUT ;
    USE SIGNAL ;
    PORT
      LAYER METAL1 ;
        RECT 193.55 4309.65 194.95 4311.05 ;
    END
  END buf_vdd_W<3>
  PIN buf_vdd_W<2>
    DIRECTION INOUT ;
    USE SIGNAL ;
    PORT
      LAYER METAL1 ;
        RECT 193.55 4415.65 194.95 4417.05 ;
    END
  END buf_vdd_W<2>
  PIN buf_vdd_E
    DIRECTION INOUT ;
    USE SIGNAL ;
    PORT
      LAYER METAL1 ;
        RECT 6705.05 4392.65 6706.45 4394.05 ;
    END
  END buf_vdd_E
  PIN buf_vdd_N<5>
    DIRECTION INOUT ;
    USE SIGNAL ;
    PORT
      LAYER METAL1 ;
        RECT 6110.8 5963.9 6112.2 5965.3 ;
    END
  END buf_vdd_N<5>
  PIN buf_vdd_N<2>
    DIRECTION INOUT ;
    USE SIGNAL ;
    PORT
      LAYER METAL1 ;
        RECT 2718.8 5963.9 2720.2 5965.3 ;
    END
  END buf_vdd_N<2>
  PIN buf_vdd_N<3>
    DIRECTION INOUT ;
    USE SIGNAL ;
    PORT
      LAYER METAL1 ;
        RECT 3142.8 5963.9 3144.2 5965.3 ;
    END
  END buf_vdd_N<3>
  PIN buf_vdd_N<1>
    DIRECTION INOUT ;
    USE SIGNAL ;
    PORT
      LAYER METAL1 ;
        RECT 2294.8 5963.9 2296.2 5965.3 ;
    END
  END buf_vdd_N<1>
  PIN buf_vdd_N<4>
    DIRECTION INOUT ;
    USE SIGNAL ;
    PORT
      LAYER METAL1 ;
        RECT 3884.8 5963.9 3886.2 5965.3 ;
    END
  END buf_vdd_N<4>
  PIN buf_vdd_N<0>
    DIRECTION INOUT ;
    USE SIGNAL ;
    PORT
      LAYER METAL1 ;
        RECT 916.8 5963.9 918.2 5965.3 ;
    END
  END buf_vdd_N<0>
  PIN buf_vdd_W<1>
    DIRECTION INOUT ;
    USE SIGNAL ;
    PORT
      LAYER METAL1 ;
        RECT 193.55 4521.65 194.95 4523.05 ;
    END
  END buf_vdd_W<1>
  PIN buf_vdd_W<0>
    DIRECTION INOUT ;
    USE SIGNAL ;
    PORT
      LAYER METAL1 ;
        RECT 193.55 4839.65 194.95 4841.05 ;
    END
  END buf_vdd_W<0>
  PIN buf_vdd_W<10>
    DIRECTION INOUT ;
    USE SIGNAL ;
    PORT
      LAYER METAL1 ;
        RECT 193.55 3567.65 194.95 3569.05 ;
    END
  END buf_vdd_W<10>
  PIN buf_vdd_W<9>
    DIRECTION INOUT ;
    USE SIGNAL ;
    PORT
      LAYER METAL1 ;
        RECT 193.55 3673.65 194.95 3675.05 ;
    END
  END buf_vdd_W<9>
  PIN buf_vdd_W<8>
    DIRECTION INOUT ;
    USE SIGNAL ;
    PORT
      LAYER METAL1 ;
        RECT 193.55 3779.65 194.95 3781.05 ;
    END
  END buf_vdd_W<8>
  PIN buf_vdd_W<7>
    DIRECTION INOUT ;
    USE SIGNAL ;
    PORT
      LAYER METAL1 ;
        RECT 193.55 3885.65 194.95 3887.05 ;
    END
  END buf_vdd_W<7>
  PIN gnd_W<1>
    DIRECTION INOUT ;
    USE SIGNAL ;
    PORT
      LAYER METAL2 ;
        RECT 194.1 5354.96 194.89 5362.75 ;
    END
  END gnd_W<1>
  PIN gnd_W<0>
    DIRECTION INOUT ;
    USE SIGNAL ;
    PORT
      LAYER METAL2 ;
        RECT 194.1 5672.95 194.9 5680.75 ;
    END
  END gnd_W<0>
  PIN VINJ_W
    DIRECTION INOUT ;
    USE SIGNAL ;
    PORT
      LAYER METAL2 ;
        RECT 194.1 2704.95 194.9 2712.75 ;
    END
  END VINJ_W
  PIN avdd_W
    DIRECTION INOUT ;
    USE SIGNAL ;
    PORT
      LAYER METAL2 ;
        RECT 194.1 2810.95 194.9 2818.75 ;
    END
  END avdd_W
  PIN esd_vdd_W
    DIRECTION INOUT ;
    USE SIGNAL ;
    PORT
      LAYER METAL2 ;
        RECT 194.1 2916.95 194.9 2924.75 ;
    END
  END esd_vdd_W
  PIN gnd_W<2>
    DIRECTION INOUT ;
    USE SIGNAL ;
    PORT
      LAYER METAL2 ;
        RECT 194.1 3022.96 194.88 3030.75 ;
    END
  END gnd_W<2>
  PIN VINJ_S<0>
    DIRECTION INOUT ;
    USE SIGNAL ;
    PORT
      LAYER METAL2 ;
        RECT 584.1 194.95 591.9 195.75 ;
    END
  END VINJ_S<0>
  PIN avdd_S<0>
    DIRECTION INOUT ;
    USE SIGNAL ;
    PORT
      LAYER METAL2 ;
        RECT 478.1 194.95 485.9 195.75 ;
    END
  END avdd_S<0>
  PIN esd_vdd_S<0>
    DIRECTION INOUT ;
    USE SIGNAL ;
    PORT
      LAYER METAL2 ;
        RECT 372.1 194.96 379.9 195.75 ;
    END
  END esd_vdd_S<0>
  PIN gnd_S<0>
    DIRECTION INOUT ;
    USE SIGNAL ;
    PORT
      LAYER METAL2 ;
        RECT 266.1 194.95 273.9 195.75 ;
    END
  END gnd_S<0>
  PIN VINJ_S<1>
    DIRECTION INOUT ;
    USE SIGNAL ;
    PORT
      LAYER METAL2 ;
        RECT 3552.1 194.95 3559.9 195.75 ;
    END
  END VINJ_S<1>
  PIN avdd_S<1>
    DIRECTION INOUT ;
    USE SIGNAL ;
    PORT
      LAYER METAL2 ;
        RECT 3446.1 194.95 3453.9 195.75 ;
    END
  END avdd_S<1>
  PIN esd_vdd_S<1>
    DIRECTION INOUT ;
    USE SIGNAL ;
    PORT
      LAYER METAL2 ;
        RECT 3340.1 194.95 3347.9 195.75 ;
    END
  END esd_vdd_S<1>
  PIN gnd_S<1>
    DIRECTION INOUT ;
    USE SIGNAL ;
    PORT
      LAYER METAL2 ;
        RECT 3234.1 194.95 3241.9 195.75 ;
    END
  END gnd_S<1>
  PIN VINJ_S<2>
    DIRECTION INOUT ;
    USE SIGNAL ;
    PORT
      LAYER METAL2 ;
        RECT 6520.1 194.95 6527.9 195.75 ;
    END
  END VINJ_S<2>
  PIN avdd_S<2>
    DIRECTION INOUT ;
    USE SIGNAL ;
    PORT
      LAYER METAL2 ;
        RECT 6414.1 194.95 6421.9 195.75 ;
    END
  END avdd_S<2>
  PIN esd_vdd_S<2>
    DIRECTION INOUT ;
    USE SIGNAL ;
    PORT
      LAYER METAL2 ;
        RECT 6308.1 194.95 6315.9 195.75 ;
    END
  END esd_vdd_S<2>
  PIN gnd_S<2>
    DIRECTION INOUT ;
    USE SIGNAL ;
    PORT
      LAYER METAL2 ;
        RECT 6202.1 194.95 6209.9 195.75 ;
    END
  END gnd_S<2>
  PIN VINJ_E
    DIRECTION INOUT ;
    USE SIGNAL ;
    PORT
      LAYER METAL2 ;
        RECT 6705.1 2704.95 6705.9 2712.75 ;
    END
  END VINJ_E
  PIN avdd_E
    DIRECTION INOUT ;
    USE SIGNAL ;
    PORT
      LAYER METAL2 ;
        RECT 6705.1 2810.95 6705.9 2818.75 ;
    END
  END avdd_E
  PIN esd_vdd_E
    DIRECTION INOUT ;
    USE SIGNAL ;
    PORT
      LAYER METAL2 ;
        RECT 6705.1 2916.95 6705.9 2924.75 ;
    END
  END esd_vdd_E
  PIN gnd_E<2>
    DIRECTION INOUT ;
    USE SIGNAL ;
    PORT
      LAYER METAL2 ;
        RECT 6705.1 3022.95 6705.9 3030.75 ;
    END
  END gnd_E<2>
  PIN gnd_E<1>
    DIRECTION INOUT ;
    USE SIGNAL ;
    PORT
      LAYER METAL2 ;
        RECT 6705.1 5354.95 6705.9 5362.75 ;
    END
  END gnd_E<1>
  PIN gnd_E<0>
    DIRECTION INOUT ;
    USE SIGNAL ;
    PORT
      LAYER METAL2 ;
        RECT 6705.1 5672.95 6705.9 5680.75 ;
    END
  END gnd_E<0>
  PIN VINJ_N<2>
    DIRECTION INOUT ;
    USE SIGNAL ;
    PORT
      LAYER METAL2 ;
        RECT 6520.1 5963.95 6527.9 5964.75 ;
    END
  END VINJ_N<2>
  PIN avdd_N<2>
    DIRECTION INOUT ;
    USE SIGNAL ;
    PORT
      LAYER METAL2 ;
        RECT 6414.1 5963.95 6421.9 5964.75 ;
    END
  END avdd_N<2>
  PIN esd_vdd_N<2>
    DIRECTION INOUT ;
    USE SIGNAL ;
    PORT
      LAYER METAL2 ;
        RECT 6308.1 5963.95 6315.9 5964.75 ;
    END
  END esd_vdd_N<2>
  PIN gnd_N<8>
    DIRECTION INOUT ;
    USE SIGNAL ;
    PORT
      LAYER METAL2 ;
        RECT 6202.1 5963.95 6209.9 5964.75 ;
    END
  END gnd_N<8>
  PIN gnd_N<7>
    DIRECTION INOUT ;
    USE SIGNAL ;
    PORT
      LAYER METAL2 ;
        RECT 5990.1 5963.95 5997.9 5964.75 ;
    END
  END gnd_N<7>
  PIN gnd_N<6>
    DIRECTION INOUT ;
    USE SIGNAL ;
    PORT
      LAYER METAL2 ;
        RECT 3976.1 5963.95 3983.9 5964.75 ;
    END
  END gnd_N<6>
  PIN gnd_N<5>
    DIRECTION INOUT ;
    USE SIGNAL ;
    PORT
      LAYER METAL2 ;
        RECT 3764.1 5963.95 3771.9 5964.75 ;
    END
  END gnd_N<5>
  PIN VINJ_N<1>
    DIRECTION INOUT ;
    USE SIGNAL ;
    PORT
      LAYER METAL2 ;
        RECT 3552.1 5963.95 3559.9 5964.75 ;
    END
  END VINJ_N<1>
  PIN avdd_N<1>
    DIRECTION INOUT ;
    USE SIGNAL ;
    PORT
      LAYER METAL2 ;
        RECT 3446.1 5963.95 3453.9 5964.75 ;
    END
  END avdd_N<1>
  PIN esd_vdd_N<1>
    DIRECTION INOUT ;
    USE SIGNAL ;
    PORT
      LAYER METAL2 ;
        RECT 3340.1 5963.95 3347.9 5964.75 ;
    END
  END esd_vdd_N<1>
  PIN gnd_N<4>
    DIRECTION INOUT ;
    USE SIGNAL ;
    PORT
      LAYER METAL2 ;
        RECT 3234.1 5963.95 3241.9 5964.75 ;
    END
  END gnd_N<4>
  PIN gnd_N<3>
    DIRECTION INOUT ;
    USE SIGNAL ;
    PORT
      LAYER METAL2 ;
        RECT 3022.1 5963.95 3029.91 5964.75 ;
    END
  END gnd_N<3>
  PIN gnd_N<2>
    DIRECTION INOUT ;
    USE SIGNAL ;
    PORT
      LAYER METAL2 ;
        RECT 1008.1 5963.95 1015.9 5964.75 ;
    END
  END gnd_N<2>
  PIN gnd_N<1>
    DIRECTION INOUT ;
    USE SIGNAL ;
    PORT
      LAYER METAL2 ;
        RECT 796.1 5963.95 803.9 5964.75 ;
    END
  END gnd_N<1>
  PIN VINJ_N<0>
    DIRECTION INOUT ;
    USE SIGNAL ;
    PORT
      LAYER METAL2 ;
        RECT 584.1 5963.95 591.9 5964.75 ;
    END
  END VINJ_N<0>
  PIN avdd_N<0>
    DIRECTION INOUT ;
    USE SIGNAL ;
    PORT
      LAYER METAL2 ;
        RECT 478.1 5963.96 485.9 5964.75 ;
    END
  END avdd_N<0>
  PIN esd_vdd_N<0>
    DIRECTION INOUT ;
    USE SIGNAL ;
    PORT
      LAYER METAL2 ;
        RECT 372.1 5963.95 379.9 5964.75 ;
    END
  END esd_vdd_N<0>
  PIN gnd_N<0>
    DIRECTION INOUT ;
    USE SIGNAL ;
    PORT
      LAYER METAL2 ;
        RECT 266.1 5963.95 273.9 5964.75 ;
    END
  END gnd_N<0>
  PIN DVDD_N<2>
    DIRECTION INOUT ;
    USE SIGNAL ;
    PORT
      LAYER METAL2 ;
        RECT 6626.1 5963.95 6633.9 5964.75 ;
    END
  END DVDD_N<2>
  PIN IO_N_CLK<3>
    DIRECTION INOUT ;
    USE SIGNAL ;
    PORT
      LAYER METAL2 ;
        RECT 6096.1 5963.95 6103.9 5964.75 ;
    END
  END IO_N_CLK<3>
  PIN IO_N<35>
    DIRECTION INOUT ;
    USE SIGNAL ;
    PORT
      LAYER METAL2 ;
        RECT 5884.1 5963.95 5891.9 5964.75 ;
    END
  END IO_N<35>
  PIN IO_N<34>
    DIRECTION INOUT ;
    USE SIGNAL ;
    PORT
      LAYER METAL2 ;
        RECT 5778.1 5963.95 5785.9 5964.75 ;
    END
  END IO_N<34>
  PIN IO_N<33>
    DIRECTION INOUT ;
    USE SIGNAL ;
    PORT
      LAYER METAL2 ;
        RECT 5672.1 5963.95 5679.9 5964.75 ;
    END
  END IO_N<33>
  PIN IO_N<32>
    DIRECTION INOUT ;
    USE SIGNAL ;
    PORT
      LAYER METAL2 ;
        RECT 5566.1 5963.95 5573.9 5964.75 ;
    END
  END IO_N<32>
  PIN IO_N<31>
    DIRECTION INOUT ;
    USE SIGNAL ;
    PORT
      LAYER METAL2 ;
        RECT 5460.1 5963.95 5467.9 5964.75 ;
    END
  END IO_N<31>
  PIN IO_N<30>
    DIRECTION INOUT ;
    USE SIGNAL ;
    PORT
      LAYER METAL2 ;
        RECT 5354.1 5963.95 5361.9 5964.75 ;
    END
  END IO_N<30>
  PIN IO_N<29>
    DIRECTION INOUT ;
    USE SIGNAL ;
    PORT
      LAYER METAL2 ;
        RECT 5248.1 5963.95 5255.9 5964.75 ;
    END
  END IO_N<29>
  PIN IO_N<28>
    DIRECTION INOUT ;
    USE SIGNAL ;
    PORT
      LAYER METAL2 ;
        RECT 5142.1 5963.95 5149.9 5964.75 ;
    END
  END IO_N<28>
  PIN IO_N<27>
    DIRECTION INOUT ;
    USE SIGNAL ;
    PORT
      LAYER METAL2 ;
        RECT 5036.1 5963.95 5043.9 5964.75 ;
    END
  END IO_N<27>
  PIN IO_N<26>
    DIRECTION INOUT ;
    USE SIGNAL ;
    PORT
      LAYER METAL2 ;
        RECT 4930.1 5963.95 4937.9 5964.75 ;
    END
  END IO_N<26>
  PIN IO_N<25>
    DIRECTION INOUT ;
    USE SIGNAL ;
    PORT
      LAYER METAL2 ;
        RECT 4824.1 5963.95 4831.9 5964.75 ;
    END
  END IO_N<25>
  PIN IO_N<24>
    DIRECTION INOUT ;
    USE SIGNAL ;
    PORT
      LAYER METAL2 ;
        RECT 4718.1 5963.95 4725.9 5964.75 ;
    END
  END IO_N<24>
  PIN IO_N<23>
    DIRECTION INOUT ;
    USE SIGNAL ;
    PORT
      LAYER METAL2 ;
        RECT 4612.1 5963.95 4619.9 5964.75 ;
    END
  END IO_N<23>
  PIN IO_N<22>
    DIRECTION INOUT ;
    USE SIGNAL ;
    PORT
      LAYER METAL2 ;
        RECT 4506.1 5963.95 4513.9 5964.75 ;
    END
  END IO_N<22>
  PIN IO_N<21>
    DIRECTION INOUT ;
    USE SIGNAL ;
    PORT
      LAYER METAL2 ;
        RECT 4400.1 5963.95 4407.9 5964.75 ;
    END
  END IO_N<21>
  PIN IO_N<20>
    DIRECTION INOUT ;
    USE SIGNAL ;
    PORT
      LAYER METAL2 ;
        RECT 4294.1 5963.95 4301.9 5964.75 ;
    END
  END IO_N<20>
  PIN IO_N<19>
    DIRECTION INOUT ;
    USE SIGNAL ;
    PORT
      LAYER METAL2 ;
        RECT 4188.1 5963.95 4195.9 5964.75 ;
    END
  END IO_N<19>
  PIN IO_N<18>
    DIRECTION INOUT ;
    USE SIGNAL ;
    PORT
      LAYER METAL2 ;
        RECT 4082.1 5963.95 4089.9 5964.75 ;
    END
  END IO_N<18>
  PIN IO_N_CLK<2>
    DIRECTION INOUT ;
    USE SIGNAL ;
    PORT
      LAYER METAL2 ;
        RECT 3870.1 5963.95 3877.9 5964.75 ;
    END
  END IO_N_CLK<2>
  PIN DVDD_N<1>
    DIRECTION INOUT ;
    USE SIGNAL ;
    PORT
      LAYER METAL2 ;
        RECT 3658.1 5963.95 3665.9 5964.75 ;
    END
  END DVDD_N<1>
  PIN IO_N_CLK<1>
    DIRECTION INOUT ;
    USE SIGNAL ;
    PORT
      LAYER METAL2 ;
        RECT 3128.1 5963.95 3135.9 5964.75 ;
    END
  END IO_N_CLK<1>
  PIN IO_N<17>
    DIRECTION INOUT ;
    USE SIGNAL ;
    PORT
      LAYER METAL2 ;
        RECT 2916.1 5963.95 2923.9 5964.75 ;
    END
  END IO_N<17>
  PIN IO_N<16>
    DIRECTION INOUT ;
    USE SIGNAL ;
    PORT
      LAYER METAL2 ;
        RECT 2810.1 5963.95 2817.9 5964.75 ;
    END
  END IO_N<16>
  PIN IO_N<15>
    DIRECTION INOUT ;
    USE SIGNAL ;
    PORT
      LAYER METAL2 ;
        RECT 2704.1 5963.95 2711.9 5964.75 ;
    END
  END IO_N<15>
  PIN IO_N<14>
    DIRECTION INOUT ;
    USE SIGNAL ;
    PORT
      LAYER METAL2 ;
        RECT 2598.1 5963.95 2605.9 5964.75 ;
    END
  END IO_N<14>
  PIN IO_N<13>
    DIRECTION INOUT ;
    USE SIGNAL ;
    PORT
      LAYER METAL2 ;
        RECT 2492.1 5963.95 2499.9 5964.75 ;
    END
  END IO_N<13>
  PIN IO_N<12>
    DIRECTION INOUT ;
    USE SIGNAL ;
    PORT
      LAYER METAL2 ;
        RECT 2386.1 5963.95 2393.9 5964.75 ;
    END
  END IO_N<12>
  PIN IO_N<11>
    DIRECTION INOUT ;
    USE SIGNAL ;
    PORT
      LAYER METAL2 ;
        RECT 2280.1 5963.95 2287.9 5964.75 ;
    END
  END IO_N<11>
  PIN IO_N<10>
    DIRECTION INOUT ;
    USE SIGNAL ;
    PORT
      LAYER METAL2 ;
        RECT 2174.1 5963.95 2181.9 5964.75 ;
    END
  END IO_N<10>
  PIN IO_N<9>
    DIRECTION INOUT ;
    USE SIGNAL ;
    PORT
      LAYER METAL2 ;
        RECT 2068.1 5963.95 2075.9 5964.75 ;
    END
  END IO_N<9>
  PIN IO_N<8>
    DIRECTION INOUT ;
    USE SIGNAL ;
    PORT
      LAYER METAL2 ;
        RECT 1962.1 5963.95 1969.9 5964.75 ;
    END
  END IO_N<8>
  PIN IO_N<7>
    DIRECTION INOUT ;
    USE SIGNAL ;
    PORT
      LAYER METAL2 ;
        RECT 1856.1 5963.95 1863.9 5964.75 ;
    END
  END IO_N<7>
  PIN IO_N<6>
    DIRECTION INOUT ;
    USE SIGNAL ;
    PORT
      LAYER METAL2 ;
        RECT 1750.1 5963.95 1757.9 5964.75 ;
    END
  END IO_N<6>
  PIN IO_N<5>
    DIRECTION INOUT ;
    USE SIGNAL ;
    PORT
      LAYER METAL2 ;
        RECT 1644.1 5963.95 1651.9 5964.75 ;
    END
  END IO_N<5>
  PIN IO_N<4>
    DIRECTION INOUT ;
    USE SIGNAL ;
    PORT
      LAYER METAL2 ;
        RECT 1538.1 5963.95 1545.9 5964.75 ;
    END
  END IO_N<4>
  PIN IO_N<3>
    DIRECTION INOUT ;
    USE SIGNAL ;
    PORT
      LAYER METAL2 ;
        RECT 1432.1 5963.95 1439.9 5964.75 ;
    END
  END IO_N<3>
  PIN IO_N<2>
    DIRECTION INOUT ;
    USE SIGNAL ;
    PORT
      LAYER METAL2 ;
        RECT 1326.1 5963.95 1333.9 5964.75 ;
    END
  END IO_N<2>
  PIN IO_N<1>
    DIRECTION INOUT ;
    USE SIGNAL ;
    PORT
      LAYER METAL2 ;
        RECT 1220.1 5963.95 1227.9 5964.75 ;
    END
  END IO_N<1>
  PIN IO_N<0>
    DIRECTION INOUT ;
    USE SIGNAL ;
    PORT
      LAYER METAL2 ;
        RECT 1114.1 5963.95 1121.9 5964.75 ;
    END
  END IO_N<0>
  PIN IO_N_CLK<0>
    DIRECTION INOUT ;
    USE SIGNAL ;
    PORT
      LAYER METAL2 ;
        RECT 902.1 5963.95 909.9 5964.75 ;
    END
  END IO_N_CLK<0>
  PIN DVDD_N<0>
    DIRECTION INOUT ;
    USE SIGNAL ;
    PORT
      LAYER METAL2 ;
        RECT 690.1 5963.95 697.9 5964.75 ;
    END
  END DVDD_N<0>
  PIN IO_W<1>
    DIRECTION INOUT ;
    USE SIGNAL ;
    PORT
      LAYER METAL2 ;
        RECT 194.1 5142.95 194.9 5150.75 ;
    END
  END IO_W<1>
  PIN IO_W<0>
    DIRECTION INOUT ;
    USE SIGNAL ;
    PORT
      LAYER METAL2 ;
        RECT 194.1 5248.95 194.9 5256.75 ;
    END
  END IO_W<0>
  PIN IO_E_RES<1>
    DIRECTION INOUT ;
    USE SIGNAL ;
    PORT
      LAYER METAL2 ;
        RECT 6705.1 5460.95 6705.9 5468.75 ;
    END
  END IO_E_RES<1>
  PIN IO_E_RES<0>
    DIRECTION INOUT ;
    USE SIGNAL ;
    PORT
      LAYER METAL2 ;
        RECT 6705.1 5566.95 6705.9 5574.75 ;
    END
  END IO_E_RES<0>
  PIN IO_Bare_E<1>
    DIRECTION INOUT ;
    USE SIGNAL ;
    PORT
      LAYER METAL2 ;
        RECT 6705.1 5778.95 6705.9 5786.75 ;
    END
  END IO_Bare_E<1>
  PIN IO_Bare_E<0>
    DIRECTION INOUT ;
    USE SIGNAL ;
    PORT
      LAYER METAL2 ;
        RECT 6705.1 5884.95 6705.9 5892.75 ;
    END
  END IO_Bare_E<0>
  PIN IO_W_RES<1>
    DIRECTION INOUT ;
    USE SIGNAL ;
    PORT
      LAYER METAL2 ;
        RECT 194.1 5460.95 194.9 5468.75 ;
    END
  END IO_W_RES<1>
  PIN IO_W_RES<0>
    DIRECTION INOUT ;
    USE SIGNAL ;
    PORT
      LAYER METAL2 ;
        RECT 194.1 5566.95 194.9 5574.75 ;
    END
  END IO_W_RES<0>
  PIN IO_Bare_W<1>
    DIRECTION INOUT ;
    USE SIGNAL ;
    PORT
      LAYER METAL2 ;
        RECT 194.1 5778.95 194.9 5786.75 ;
    END
  END IO_Bare_W<1>
  PIN IO_Bare_W<0>
    DIRECTION INOUT ;
    USE SIGNAL ;
    PORT
      LAYER METAL2 ;
        RECT 194.1 5884.95 194.9 5892.75 ;
    END
  END IO_Bare_W<0>
  PIN DVDD_S<2>
    DIRECTION INOUT ;
    USE SIGNAL ;
    PORT
      LAYER METAL2 ;
        RECT 6626.1 194.95 6633.9 195.75 ;
    END
  END DVDD_S<2>
  PIN IO_S<45>
    DIRECTION INOUT ;
    USE SIGNAL ;
    PORT
      LAYER METAL2 ;
        RECT 6096.1 194.95 6103.9 195.75 ;
    END
  END IO_S<45>
  PIN IO_S<44>
    DIRECTION INOUT ;
    USE SIGNAL ;
    PORT
      LAYER METAL2 ;
        RECT 5990.1 194.95 5997.9 195.75 ;
    END
  END IO_S<44>
  PIN IO_S<43>
    DIRECTION INOUT ;
    USE SIGNAL ;
    PORT
      LAYER METAL2 ;
        RECT 5884.1 194.95 5891.9 195.75 ;
    END
  END IO_S<43>
  PIN IO_S<42>
    DIRECTION INOUT ;
    USE SIGNAL ;
    PORT
      LAYER METAL2 ;
        RECT 5778.1 194.95 5785.9 195.75 ;
    END
  END IO_S<42>
  PIN IO_S<41>
    DIRECTION INOUT ;
    USE SIGNAL ;
    PORT
      LAYER METAL2 ;
        RECT 5672.1 194.95 5679.9 195.75 ;
    END
  END IO_S<41>
  PIN IO_S<40>
    DIRECTION INOUT ;
    USE SIGNAL ;
    PORT
      LAYER METAL2 ;
        RECT 5566.1 194.95 5573.9 195.75 ;
    END
  END IO_S<40>
  PIN IO_S<39>
    DIRECTION INOUT ;
    USE SIGNAL ;
    PORT
      LAYER METAL2 ;
        RECT 5460.1 194.95 5467.9 195.75 ;
    END
  END IO_S<39>
  PIN IO_S<38>
    DIRECTION INOUT ;
    USE SIGNAL ;
    PORT
      LAYER METAL2 ;
        RECT 5354.1 194.95 5361.9 195.75 ;
    END
  END IO_S<38>
  PIN IO_S<37>
    DIRECTION INOUT ;
    USE SIGNAL ;
    PORT
      LAYER METAL2 ;
        RECT 5248.1 194.95 5255.9 195.75 ;
    END
  END IO_S<37>
  PIN IO_S<36>
    DIRECTION INOUT ;
    USE SIGNAL ;
    PORT
      LAYER METAL2 ;
        RECT 5142.1 194.95 5149.9 195.75 ;
    END
  END IO_S<36>
  PIN IO_S<35>
    DIRECTION INOUT ;
    USE SIGNAL ;
    PORT
      LAYER METAL2 ;
        RECT 5036.1 194.95 5043.9 195.75 ;
    END
  END IO_S<35>
  PIN IO_S<34>
    DIRECTION INOUT ;
    USE SIGNAL ;
    PORT
      LAYER METAL2 ;
        RECT 4930.1 194.95 4937.9 195.75 ;
    END
  END IO_S<34>
  PIN IO_S<33>
    DIRECTION INOUT ;
    USE SIGNAL ;
    PORT
      LAYER METAL2 ;
        RECT 4824.1 194.95 4831.9 195.75 ;
    END
  END IO_S<33>
  PIN IO_S<32>
    DIRECTION INOUT ;
    USE SIGNAL ;
    PORT
      LAYER METAL2 ;
        RECT 4718.1 194.95 4725.9 195.75 ;
    END
  END IO_S<32>
  PIN IO_S<31>
    DIRECTION INOUT ;
    USE SIGNAL ;
    PORT
      LAYER METAL2 ;
        RECT 4612.1 194.95 4619.9 195.75 ;
    END
  END IO_S<31>
  PIN IO_S<30>
    DIRECTION INOUT ;
    USE SIGNAL ;
    PORT
      LAYER METAL2 ;
        RECT 4506.1 194.95 4513.9 195.75 ;
    END
  END IO_S<30>
  PIN IO_S<29>
    DIRECTION INOUT ;
    USE SIGNAL ;
    PORT
      LAYER METAL2 ;
        RECT 4400.1 194.95 4407.9 195.75 ;
    END
  END IO_S<29>
  PIN IO_S<28>
    DIRECTION INOUT ;
    USE SIGNAL ;
    PORT
      LAYER METAL2 ;
        RECT 4294.1 194.95 4301.9 195.75 ;
    END
  END IO_S<28>
  PIN IO_S<27>
    DIRECTION INOUT ;
    USE SIGNAL ;
    PORT
      LAYER METAL2 ;
        RECT 4188.1 194.95 4195.9 195.75 ;
    END
  END IO_S<27>
  PIN IO_S<26>
    DIRECTION INOUT ;
    USE SIGNAL ;
    PORT
      LAYER METAL2 ;
        RECT 4082.1 194.95 4089.9 195.75 ;
    END
  END IO_S<26>
  PIN IO_S<25>
    DIRECTION INOUT ;
    USE SIGNAL ;
    PORT
      LAYER METAL2 ;
        RECT 3976.1 194.95 3983.9 195.75 ;
    END
  END IO_S<25>
  PIN IO_S<24>
    DIRECTION INOUT ;
    USE SIGNAL ;
    PORT
      LAYER METAL2 ;
        RECT 3870.1 194.95 3877.9 195.75 ;
    END
  END IO_S<24>
  PIN IO_S<23>
    DIRECTION INOUT ;
    USE SIGNAL ;
    PORT
      LAYER METAL2 ;
        RECT 3764.1 194.95 3771.9 195.75 ;
    END
  END IO_S<23>
  PIN DVDD_S<1>
    DIRECTION INOUT ;
    USE SIGNAL ;
    PORT
      LAYER METAL2 ;
        RECT 3658.1 194.95 3665.9 195.75 ;
    END
  END DVDD_S<1>
  PIN IO_S<22>
    DIRECTION INOUT ;
    USE SIGNAL ;
    PORT
      LAYER METAL2 ;
        RECT 3128.1 194.95 3135.9 195.75 ;
    END
  END IO_S<22>
  PIN IO_S<21>
    DIRECTION INOUT ;
    USE SIGNAL ;
    PORT
      LAYER METAL2 ;
        RECT 3022.1 194.95 3029.9 195.75 ;
    END
  END IO_S<21>
  PIN IO_S<20>
    DIRECTION INOUT ;
    USE SIGNAL ;
    PORT
      LAYER METAL2 ;
        RECT 2916.1 194.95 2923.9 195.75 ;
    END
  END IO_S<20>
  PIN IO_S<19>
    DIRECTION INOUT ;
    USE SIGNAL ;
    PORT
      LAYER METAL2 ;
        RECT 2810.1 194.95 2817.9 195.75 ;
    END
  END IO_S<19>
  PIN IO_S<18>
    DIRECTION INOUT ;
    USE SIGNAL ;
    PORT
      LAYER METAL2 ;
        RECT 2704.1 194.95 2711.9 195.75 ;
    END
  END IO_S<18>
  PIN IO_S<17>
    DIRECTION INOUT ;
    USE SIGNAL ;
    PORT
      LAYER METAL2 ;
        RECT 2598.1 194.95 2605.9 195.75 ;
    END
  END IO_S<17>
  PIN IO_S<16>
    DIRECTION INOUT ;
    USE SIGNAL ;
    PORT
      LAYER METAL2 ;
        RECT 2492.1 194.95 2499.9 195.75 ;
    END
  END IO_S<16>
  PIN IO_S<15>
    DIRECTION INOUT ;
    USE SIGNAL ;
    PORT
      LAYER METAL2 ;
        RECT 2386.1 194.95 2393.9 195.75 ;
    END
  END IO_S<15>
  PIN IO_S<14>
    DIRECTION INOUT ;
    USE SIGNAL ;
    PORT
      LAYER METAL2 ;
        RECT 2280.1 194.95 2287.9 195.75 ;
    END
  END IO_S<14>
  PIN IO_S<13>
    DIRECTION INOUT ;
    USE SIGNAL ;
    PORT
      LAYER METAL2 ;
        RECT 2174.1 194.95 2181.9 195.75 ;
    END
  END IO_S<13>
  PIN IO_S<12>
    DIRECTION INOUT ;
    USE SIGNAL ;
    PORT
      LAYER METAL2 ;
        RECT 2068.1 194.95 2075.9 195.75 ;
    END
  END IO_S<12>
  PIN IO_S<11>
    DIRECTION INOUT ;
    USE SIGNAL ;
    PORT
      LAYER METAL2 ;
        RECT 1962.1 194.95 1969.9 195.75 ;
    END
  END IO_S<11>
  PIN IO_S<10>
    DIRECTION INOUT ;
    USE SIGNAL ;
    PORT
      LAYER METAL2 ;
        RECT 1856.1 194.95 1863.9 195.75 ;
    END
  END IO_S<10>
  PIN IO_S<9>
    DIRECTION INOUT ;
    USE SIGNAL ;
    PORT
      LAYER METAL2 ;
        RECT 1750.1 194.95 1757.9 195.75 ;
    END
  END IO_S<9>
  PIN IO_S<8>
    DIRECTION INOUT ;
    USE SIGNAL ;
    PORT
      LAYER METAL2 ;
        RECT 1644.1 194.95 1651.9 195.75 ;
    END
  END IO_S<8>
  PIN IO_S<7>
    DIRECTION INOUT ;
    USE SIGNAL ;
    PORT
      LAYER METAL2 ;
        RECT 1538.1 194.95 1545.9 195.75 ;
    END
  END IO_S<7>
  PIN IO_S<6>
    DIRECTION INOUT ;
    USE SIGNAL ;
    PORT
      LAYER METAL2 ;
        RECT 1432.1 194.95 1439.9 195.75 ;
    END
  END IO_S<6>
  PIN IO_S<5>
    DIRECTION INOUT ;
    USE SIGNAL ;
    PORT
      LAYER METAL2 ;
        RECT 1326.1 194.95 1333.9 195.75 ;
    END
  END IO_S<5>
  PIN IO_S<4>
    DIRECTION INOUT ;
    USE SIGNAL ;
    PORT
      LAYER METAL2 ;
        RECT 1220.1 194.95 1227.9 195.75 ;
    END
  END IO_S<4>
  PIN IO_S<3>
    DIRECTION INOUT ;
    USE SIGNAL ;
    PORT
      LAYER METAL2 ;
        RECT 1114.1 194.95 1121.9 195.75 ;
    END
  END IO_S<3>
  PIN IO_S<2>
    DIRECTION INOUT ;
    USE SIGNAL ;
    PORT
      LAYER METAL2 ;
        RECT 1008.1 194.95 1015.9 195.75 ;
    END
  END IO_S<2>
  PIN IO_S<1>
    DIRECTION INOUT ;
    USE SIGNAL ;
    PORT
      LAYER METAL2 ;
        RECT 902.1 194.95 909.9 195.75 ;
    END
  END IO_S<1>
  PIN IO_S<0>
    DIRECTION INOUT ;
    USE SIGNAL ;
    PORT
      LAYER METAL2 ;
        RECT 796.1 194.95 803.9 195.75 ;
    END
  END IO_S<0>
  PIN DVDD_S<0>
    DIRECTION INOUT ;
    USE SIGNAL ;
    PORT
      LAYER METAL2 ;
        RECT 690.1 194.95 697.9 195.75 ;
    END
  END DVDD_S<0>
  PIN IO_E<8>
    DIRECTION INOUT ;
    USE SIGNAL ;
    PORT
      LAYER METAL2 ;
        RECT 6705.1 4400.95 6705.9 4408.75 ;
    END
  END IO_E<8>
  PIN IO_E<7>
    DIRECTION INOUT ;
    USE SIGNAL ;
    PORT
      LAYER METAL2 ;
        RECT 6705.1 4506.95 6705.9 4514.75 ;
    END
  END IO_E<7>
  PIN IO_E<6>
    DIRECTION INOUT ;
    USE SIGNAL ;
    PORT
      LAYER METAL2 ;
        RECT 6705.1 4612.95 6705.9 4620.75 ;
    END
  END IO_E<6>
  PIN IO_E<5>
    DIRECTION INOUT ;
    USE SIGNAL ;
    PORT
      LAYER METAL2 ;
        RECT 6705.1 4718.95 6705.9 4726.75 ;
    END
  END IO_E<5>
  PIN IO_E<4>
    DIRECTION INOUT ;
    USE SIGNAL ;
    PORT
      LAYER METAL2 ;
        RECT 6705.1 4824.95 6705.9 4832.75 ;
    END
  END IO_E<4>
  PIN IO_E<3>
    DIRECTION INOUT ;
    USE SIGNAL ;
    PORT
      LAYER METAL2 ;
        RECT 6705.1 4930.95 6705.9 4938.75 ;
    END
  END IO_E<3>
  PIN IO_E<2>
    DIRECTION INOUT ;
    USE SIGNAL ;
    PORT
      LAYER METAL2 ;
        RECT 6705.1 5036.95 6705.9 5044.75 ;
    END
  END IO_E<2>
  PIN IO_E<1>
    DIRECTION INOUT ;
    USE SIGNAL ;
    PORT
      LAYER METAL2 ;
        RECT 6705.1 5142.95 6705.9 5150.75 ;
    END
  END IO_E<1>
  PIN IO_E<0>
    DIRECTION INOUT ;
    USE SIGNAL ;
    PORT
      LAYER METAL2 ;
        RECT 6705.1 5248.95 6705.9 5256.75 ;
    END
  END IO_E<0>
  PIN IO_W<42>
    DIRECTION INOUT ;
    USE SIGNAL ;
    PORT
      LAYER METAL2 ;
        RECT 194.1 266.95 194.9 274.75 ;
    END
  END IO_W<42>
  PIN IO_W<41>
    DIRECTION INOUT ;
    USE SIGNAL ;
    PORT
      LAYER METAL2 ;
        RECT 194.1 372.95 194.9 380.75 ;
    END
  END IO_W<41>
  PIN IO_W<40>
    DIRECTION INOUT ;
    USE SIGNAL ;
    PORT
      LAYER METAL2 ;
        RECT 194.1 478.95 194.9 486.75 ;
    END
  END IO_W<40>
  PIN IO_W<39>
    DIRECTION INOUT ;
    USE SIGNAL ;
    PORT
      LAYER METAL2 ;
        RECT 194.1 584.95 194.9 592.75 ;
    END
  END IO_W<39>
  PIN IO_W<38>
    DIRECTION INOUT ;
    USE SIGNAL ;
    PORT
      LAYER METAL2 ;
        RECT 194.1 690.95 194.9 698.75 ;
    END
  END IO_W<38>
  PIN IO_W<37>
    DIRECTION INOUT ;
    USE SIGNAL ;
    PORT
      LAYER METAL2 ;
        RECT 194.1 796.95 194.9 804.75 ;
    END
  END IO_W<37>
  PIN IO_W<36>
    DIRECTION INOUT ;
    USE SIGNAL ;
    PORT
      LAYER METAL2 ;
        RECT 194.1 902.95 194.9 910.75 ;
    END
  END IO_W<36>
  PIN IO_W<35>
    DIRECTION INOUT ;
    USE SIGNAL ;
    PORT
      LAYER METAL2 ;
        RECT 194.1 1008.95 194.9 1016.75 ;
    END
  END IO_W<35>
  PIN IO_W<34>
    DIRECTION INOUT ;
    USE SIGNAL ;
    PORT
      LAYER METAL2 ;
        RECT 194.1 1114.95 194.9 1122.75 ;
    END
  END IO_W<34>
  PIN IO_W<33>
    DIRECTION INOUT ;
    USE SIGNAL ;
    PORT
      LAYER METAL2 ;
        RECT 194.1 1220.95 194.9 1228.75 ;
    END
  END IO_W<33>
  PIN IO_W<32>
    DIRECTION INOUT ;
    USE SIGNAL ;
    PORT
      LAYER METAL2 ;
        RECT 194.1 1326.95 194.9 1334.75 ;
    END
  END IO_W<32>
  PIN IO_W<31>
    DIRECTION INOUT ;
    USE SIGNAL ;
    PORT
      LAYER METAL2 ;
        RECT 194.1 1432.95 194.9 1440.75 ;
    END
  END IO_W<31>
  PIN IO_W<30>
    DIRECTION INOUT ;
    USE SIGNAL ;
    PORT
      LAYER METAL2 ;
        RECT 194.1 1538.95 194.9 1546.75 ;
    END
  END IO_W<30>
  PIN IO_W<29>
    DIRECTION INOUT ;
    USE SIGNAL ;
    PORT
      LAYER METAL2 ;
        RECT 194.1 1644.95 194.9 1652.75 ;
    END
  END IO_W<29>
  PIN IO_W<28>
    DIRECTION INOUT ;
    USE SIGNAL ;
    PORT
      LAYER METAL2 ;
        RECT 194.1 1750.95 194.9 1758.75 ;
    END
  END IO_W<28>
  PIN IO_W<27>
    DIRECTION INOUT ;
    USE SIGNAL ;
    PORT
      LAYER METAL2 ;
        RECT 194.1 1856.95 194.9 1864.75 ;
    END
  END IO_W<27>
  PIN IO_W<26>
    DIRECTION INOUT ;
    USE SIGNAL ;
    PORT
      LAYER METAL2 ;
        RECT 194.1 1962.95 194.9 1970.75 ;
    END
  END IO_W<26>
  PIN IO_W<25>
    DIRECTION INOUT ;
    USE SIGNAL ;
    PORT
      LAYER METAL2 ;
        RECT 194.1 2068.95 194.9 2076.75 ;
    END
  END IO_W<25>
  PIN IO_W<24>
    DIRECTION INOUT ;
    USE SIGNAL ;
    PORT
      LAYER METAL2 ;
        RECT 194.1 2174.95 194.9 2182.75 ;
    END
  END IO_W<24>
  PIN IO_W<23>
    DIRECTION INOUT ;
    USE SIGNAL ;
    PORT
      LAYER METAL2 ;
        RECT 194.1 2280.95 194.9 2288.75 ;
    END
  END IO_W<23>
  PIN IO_W<22>
    DIRECTION INOUT ;
    USE SIGNAL ;
    PORT
      LAYER METAL2 ;
        RECT 194.1 2386.95 194.9 2394.75 ;
    END
  END IO_W<22>
  PIN IO_W<21>
    DIRECTION INOUT ;
    USE SIGNAL ;
    PORT
      LAYER METAL2 ;
        RECT 194.1 2492.95 194.9 2500.75 ;
    END
  END IO_W<21>
  PIN DVDD_W<0>
    DIRECTION INOUT ;
    USE SIGNAL ;
    PORT
      LAYER METAL2 ;
        RECT 194.1 2598.95 194.9 2606.75 ;
    END
  END DVDD_W<0>
  PIN IO_W<20>
    DIRECTION INOUT ;
    USE SIGNAL ;
    PORT
      LAYER METAL2 ;
        RECT 194.1 3128.95 194.9 3136.75 ;
    END
  END IO_W<20>
  PIN IO_W<19>
    DIRECTION INOUT ;
    USE SIGNAL ;
    PORT
      LAYER METAL2 ;
        RECT 194.1 3234.95 194.9 3242.75 ;
    END
  END IO_W<19>
  PIN IO_W<18>
    DIRECTION INOUT ;
    USE SIGNAL ;
    PORT
      LAYER METAL2 ;
        RECT 194.1 3340.95 194.9 3348.75 ;
    END
  END IO_W<18>
  PIN IO_W<17>
    DIRECTION INOUT ;
    USE SIGNAL ;
    PORT
      LAYER METAL2 ;
        RECT 194.1 3446.95 194.9 3454.75 ;
    END
  END IO_W<17>
  PIN IO_W<16>
    DIRECTION INOUT ;
    USE SIGNAL ;
    PORT
      LAYER METAL2 ;
        RECT 194.1 3552.95 194.9 3560.75 ;
    END
  END IO_W<16>
  PIN IO_W<15>
    DIRECTION INOUT ;
    USE SIGNAL ;
    PORT
      LAYER METAL2 ;
        RECT 194.1 3658.95 194.9 3666.75 ;
    END
  END IO_W<15>
  PIN IO_W<14>
    DIRECTION INOUT ;
    USE SIGNAL ;
    PORT
      LAYER METAL2 ;
        RECT 194.1 3764.95 194.9 3772.75 ;
    END
  END IO_W<14>
  PIN IO_W<13>
    DIRECTION INOUT ;
    USE SIGNAL ;
    PORT
      LAYER METAL2 ;
        RECT 194.1 3870.95 194.9 3878.75 ;
    END
  END IO_W<13>
  PIN IO_W<12>
    DIRECTION INOUT ;
    USE SIGNAL ;
    PORT
      LAYER METAL2 ;
        RECT 194.1 3976.95 194.9 3984.75 ;
    END
  END IO_W<12>
  PIN IO_W<11>
    DIRECTION INOUT ;
    USE SIGNAL ;
    PORT
      LAYER METAL2 ;
        RECT 194.1 4082.95 194.9 4090.75 ;
    END
  END IO_W<11>
  PIN IO_W<10>
    DIRECTION INOUT ;
    USE SIGNAL ;
    PORT
      LAYER METAL2 ;
        RECT 194.1 4188.95 194.9 4196.75 ;
    END
  END IO_W<10>
  PIN IO_W<9>
    DIRECTION INOUT ;
    USE SIGNAL ;
    PORT
      LAYER METAL2 ;
        RECT 194.1 4294.95 194.9 4302.75 ;
    END
  END IO_W<9>
  PIN IO_W<8>
    DIRECTION INOUT ;
    USE SIGNAL ;
    PORT
      LAYER METAL2 ;
        RECT 194.1 4400.95 194.9 4408.75 ;
    END
  END IO_W<8>
  PIN IO_W<7>
    DIRECTION INOUT ;
    USE SIGNAL ;
    PORT
      LAYER METAL2 ;
        RECT 194.1 4506.95 194.9 4514.75 ;
    END
  END IO_W<7>
  PIN IO_W<6>
    DIRECTION INOUT ;
    USE SIGNAL ;
    PORT
      LAYER METAL2 ;
        RECT 194.1 4612.95 194.9 4620.75 ;
    END
  END IO_W<6>
  PIN IO_W<5>
    DIRECTION INOUT ;
    USE SIGNAL ;
    PORT
      LAYER METAL2 ;
        RECT 194.1 4718.95 194.9 4726.75 ;
    END
  END IO_W<5>
  PIN IO_W<4>
    DIRECTION INOUT ;
    USE SIGNAL ;
    PORT
      LAYER METAL2 ;
        RECT 194.1 4824.95 194.9 4832.75 ;
    END
  END IO_W<4>
  PIN IO_W<3>
    DIRECTION INOUT ;
    USE SIGNAL ;
    PORT
      LAYER METAL2 ;
        RECT 194.1 4930.95 194.9 4938.75 ;
    END
  END IO_W<3>
  PIN IO_W<2>
    DIRECTION INOUT ;
    USE SIGNAL ;
    PORT
      LAYER METAL2 ;
        RECT 194.1 5036.95 194.9 5044.75 ;
    END
  END IO_W<2>
  PIN IO_E<42>
    DIRECTION INOUT ;
    USE SIGNAL ;
    PORT
      LAYER METAL2 ;
        RECT 6705.1 266.95 6705.9 274.75 ;
    END
  END IO_E<42>
  PIN IO_E<41>
    DIRECTION INOUT ;
    USE SIGNAL ;
    PORT
      LAYER METAL2 ;
        RECT 6705.1 372.95 6705.9 380.75 ;
    END
  END IO_E<41>
  PIN IO_E<40>
    DIRECTION INOUT ;
    USE SIGNAL ;
    PORT
      LAYER METAL2 ;
        RECT 6705.1 478.95 6705.9 486.75 ;
    END
  END IO_E<40>
  PIN IO_E<39>
    DIRECTION INOUT ;
    USE SIGNAL ;
    PORT
      LAYER METAL2 ;
        RECT 6705.1 584.95 6705.9 592.75 ;
    END
  END IO_E<39>
  PIN IO_E<38>
    DIRECTION INOUT ;
    USE SIGNAL ;
    PORT
      LAYER METAL2 ;
        RECT 6705.1 690.95 6705.9 698.75 ;
    END
  END IO_E<38>
  PIN IO_E<37>
    DIRECTION INOUT ;
    USE SIGNAL ;
    PORT
      LAYER METAL2 ;
        RECT 6705.1 796.95 6705.9 804.75 ;
    END
  END IO_E<37>
  PIN IO_E<36>
    DIRECTION INOUT ;
    USE SIGNAL ;
    PORT
      LAYER METAL2 ;
        RECT 6705.1 902.95 6705.9 910.75 ;
    END
  END IO_E<36>
  PIN IO_E<35>
    DIRECTION INOUT ;
    USE SIGNAL ;
    PORT
      LAYER METAL2 ;
        RECT 6705.1 1008.95 6705.9 1016.75 ;
    END
  END IO_E<35>
  PIN IO_E<34>
    DIRECTION INOUT ;
    USE SIGNAL ;
    PORT
      LAYER METAL2 ;
        RECT 6705.1 1114.95 6705.9 1122.75 ;
    END
  END IO_E<34>
  PIN IO_E<33>
    DIRECTION INOUT ;
    USE SIGNAL ;
    PORT
      LAYER METAL2 ;
        RECT 6705.1 1220.95 6705.9 1228.75 ;
    END
  END IO_E<33>
  PIN IO_E<32>
    DIRECTION INOUT ;
    USE SIGNAL ;
    PORT
      LAYER METAL2 ;
        RECT 6705.1 1326.95 6705.9 1334.75 ;
    END
  END IO_E<32>
  PIN IO_E<31>
    DIRECTION INOUT ;
    USE SIGNAL ;
    PORT
      LAYER METAL2 ;
        RECT 6705.1 1432.95 6705.9 1440.75 ;
    END
  END IO_E<31>
  PIN IO_E<30>
    DIRECTION INOUT ;
    USE SIGNAL ;
    PORT
      LAYER METAL2 ;
        RECT 6705.1 1538.95 6705.9 1546.75 ;
    END
  END IO_E<30>
  PIN IO_E<29>
    DIRECTION INOUT ;
    USE SIGNAL ;
    PORT
      LAYER METAL2 ;
        RECT 6705.1 1644.95 6705.9 1652.75 ;
    END
  END IO_E<29>
  PIN IO_E<28>
    DIRECTION INOUT ;
    USE SIGNAL ;
    PORT
      LAYER METAL2 ;
        RECT 6705.1 1750.95 6705.9 1758.75 ;
    END
  END IO_E<28>
  PIN IO_E<27>
    DIRECTION INOUT ;
    USE SIGNAL ;
    PORT
      LAYER METAL2 ;
        RECT 6705.1 1856.95 6705.9 1864.75 ;
    END
  END IO_E<27>
  PIN IO_E<26>
    DIRECTION INOUT ;
    USE SIGNAL ;
    PORT
      LAYER METAL2 ;
        RECT 6705.1 1962.95 6705.9 1970.75 ;
    END
  END IO_E<26>
  PIN IO_E<25>
    DIRECTION INOUT ;
    USE SIGNAL ;
    PORT
      LAYER METAL2 ;
        RECT 6705.1 2068.95 6705.9 2076.75 ;
    END
  END IO_E<25>
  PIN IO_E<24>
    DIRECTION INOUT ;
    USE SIGNAL ;
    PORT
      LAYER METAL2 ;
        RECT 6705.1 2174.95 6705.9 2182.75 ;
    END
  END IO_E<24>
  PIN IO_E<23>
    DIRECTION INOUT ;
    USE SIGNAL ;
    PORT
      LAYER METAL2 ;
        RECT 6705.1 2280.95 6705.9 2288.75 ;
    END
  END IO_E<23>
  PIN IO_E<22>
    DIRECTION INOUT ;
    USE SIGNAL ;
    PORT
      LAYER METAL2 ;
        RECT 6705.1 2386.95 6705.9 2394.75 ;
    END
  END IO_E<22>
  PIN IO_E<21>
    DIRECTION INOUT ;
    USE SIGNAL ;
    PORT
      LAYER METAL2 ;
        RECT 6705.1 2492.95 6705.9 2500.75 ;
    END
  END IO_E<21>
  PIN DVDD_E<0>
    DIRECTION INOUT ;
    USE SIGNAL ;
    PORT
      LAYER METAL2 ;
        RECT 6705.1 2598.95 6705.9 2606.75 ;
    END
  END DVDD_E<0>
  PIN IO_E<20>
    DIRECTION INOUT ;
    USE SIGNAL ;
    PORT
      LAYER METAL2 ;
        RECT 6705.1 3128.95 6705.9 3136.75 ;
    END
  END IO_E<20>
  PIN IO_E<19>
    DIRECTION INOUT ;
    USE SIGNAL ;
    PORT
      LAYER METAL2 ;
        RECT 6705.1 3234.95 6705.9 3242.75 ;
    END
  END IO_E<19>
  PIN IO_E<18>
    DIRECTION INOUT ;
    USE SIGNAL ;
    PORT
      LAYER METAL2 ;
        RECT 6705.1 3340.95 6705.9 3348.75 ;
    END
  END IO_E<18>
  PIN IO_E<17>
    DIRECTION INOUT ;
    USE SIGNAL ;
    PORT
      LAYER METAL2 ;
        RECT 6705.1 3446.95 6705.9 3454.75 ;
    END
  END IO_E<17>
  PIN IO_E<16>
    DIRECTION INOUT ;
    USE SIGNAL ;
    PORT
      LAYER METAL2 ;
        RECT 6705.1 3552.95 6705.9 3560.75 ;
    END
  END IO_E<16>
  PIN IO_E<15>
    DIRECTION INOUT ;
    USE SIGNAL ;
    PORT
      LAYER METAL2 ;
        RECT 6705.1 3658.95 6705.9 3666.75 ;
    END
  END IO_E<15>
  PIN IO_E<14>
    DIRECTION INOUT ;
    USE SIGNAL ;
    PORT
      LAYER METAL2 ;
        RECT 6705.1 3764.95 6705.9 3772.75 ;
    END
  END IO_E<14>
  PIN IO_E<13>
    DIRECTION INOUT ;
    USE SIGNAL ;
    PORT
      LAYER METAL2 ;
        RECT 6705.1 3870.95 6705.9 3878.75 ;
    END
  END IO_E<13>
  PIN IO_E<12>
    DIRECTION INOUT ;
    USE SIGNAL ;
    PORT
      LAYER METAL2 ;
        RECT 6705.1 3976.95 6705.9 3984.75 ;
    END
  END IO_E<12>
  PIN IO_E<11>
    DIRECTION INOUT ;
    USE SIGNAL ;
    PORT
      LAYER METAL2 ;
        RECT 6705.1 4082.95 6705.9 4090.75 ;
    END
  END IO_E<11>
  PIN IO_E<10>
    DIRECTION INOUT ;
    USE SIGNAL ;
    PORT
      LAYER METAL2 ;
        RECT 6705.1 4188.95 6705.9 4196.75 ;
    END
  END IO_E<10>
  PIN IO_E<9>
    DIRECTION INOUT ;
    USE SIGNAL ;
    PORT
      LAYER METAL2 ;
        RECT 6705.1 4294.95 6705.9 4302.75 ;
    END
  END IO_E<9>
  PIN AVDD
    DIRECTION INOUT ;
    USE SIGNAL ;
    PORT
      LAYER METAL4 ;
        RECT 188.06 5964.84 192.24 5967.47 ;
    END
  END AVDD
  PIN GND
    DIRECTION INOUT ;
    USE SIGNAL ;
    PORT
      LAYER METAL4 ;
        RECT 180.1 5975.17 185.76 5977.6 ;
    END
  END GND
  PIN VINJ
    DIRECTION INOUT ;
    USE SIGNAL ;
    PORT
      LAYER METAL4 ;
        RECT 167.76 5980.57 172.21 5982.86 ;
    END
  END VINJ
  PIN ESDVDD
    DIRECTION INOUT ;
    USE SIGNAL ;
    PORT
      LAYER METAL4 ;
        RECT 164.19 5989.57 166.58 5990.75 ;
    END
  END ESDVDD
END frame_6p9mm_6p2mm_digbuf

MACRO TSMC350nm_VerticalScanner_STD
  PIN In<3>
    DIRECTION INOUT ;
    USE SIGNAL ;
    PORT
      LAYER METAL1 ;
        RECT 0.0 3.5 1.4 4.9 ;
    END
  END In<3>
  PIN In<2>
    DIRECTION INOUT ;
    USE SIGNAL ;
    PORT
      LAYER METAL1 ;
        RECT 0.0 6.3 1.5 7.7 ;
    END
  END In<2>
  PIN In<1>
    DIRECTION INOUT ;
    USE SIGNAL ;
    PORT
      LAYER METAL1 ;
        RECT 0.0 14.0 1.4 15.4 ;
    END
  END In<1>
  PIN In<0>
    DIRECTION INOUT ;
    USE SIGNAL ;
    PORT
      LAYER METAL1 ;
        RECT 0.0 17.5 1.4 18.9 ;
    END
  END In<0>
  PIN RSTBar_b
    DIRECTION INOUT ;
    USE SIGNAL ;
    PORT
      LAYER METAL2 ;
        RECT 156.1 0.0 157.5 1.23 ;
    END
  END RSTBar_b
  PIN CLK_b
    DIRECTION INOUT ;
    USE SIGNAL ;
    PORT
      LAYER METAL2 ;
        RECT 149.8 0.0 151.2 1.23 ;
    END
  END CLK_b
  PIN Out
    DIRECTION INOUT ;
    USE SIGNAL ;
    PORT
      LAYER METAL2 ;
        RECT 5.15 20.68 6.65 22.0 ;
    END
  END Out
  PIN Out_b
    DIRECTION INOUT ;
    USE SIGNAL ;
    PORT
      LAYER METAL2 ;
        RECT 5.15 0.0 6.65 1.27 ;
    END
  END Out_b
  PIN VDD_b
    DIRECTION INOUT ;
    USE SIGNAL ;
    PORT
      LAYER METAL2 ;
        RECT 45.86 0.0 47.36 1.28 ;
    END
  END VDD_b
  PIN GND_b
    DIRECTION INOUT ;
    USE SIGNAL ;
    PORT
      LAYER METAL2 ;
        RECT 53.79 0.0 55.29 1.23 ;
    END
  END GND_b
  PIN VDD
    DIRECTION INOUT ;
    USE SIGNAL ;
    PORT
      LAYER METAL2 ;
        RECT 45.86 20.77 47.36 22.0 ;
    END
  END VDD
  PIN GND
    DIRECTION INOUT ;
    USE SIGNAL ;
    PORT
      LAYER METAL2 ;
        RECT 53.79 20.84 55.29 22.0 ;
    END
  END GND
  PIN Din
    DIRECTION INOUT ;
    USE SIGNAL ;
    PORT
      LAYER METAL2 ;
        RECT 42.0 20.77 43.4 22.0 ;
    END
  END Din
  PIN Qout
    DIRECTION INOUT ;
    USE SIGNAL ;
    PORT
      LAYER METAL2 ;
        RECT 42.0 0.0 43.4 1.23 ;
    END
  END Qout
  PIN RSTBar
    DIRECTION INOUT ;
    USE SIGNAL ;
    PORT
      LAYER METAL2 ;
        RECT 156.1 20.77 157.5 22.0 ;
    END
  END RSTBar
  PIN CLK
    DIRECTION INOUT ;
    USE SIGNAL ;
    PORT
      LAYER METAL2 ;
        RECT 149.8 20.77 151.2 22.0 ;
    END
  END CLK
END TSMC350nm_VerticalScanner_STD

END LIBRARY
